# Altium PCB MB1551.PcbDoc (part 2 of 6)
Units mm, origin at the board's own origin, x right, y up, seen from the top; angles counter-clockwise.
Board outline 100 x 70 mm, 6 copper layers (Top Layer, Signal Layer 1, Signal Layer 2, Signal Layer 3, Signal Layer 4, Bottom Layer), stack 1.49 mm thick; 325 components, 276 nets, 1540 pads, 1100 vias.

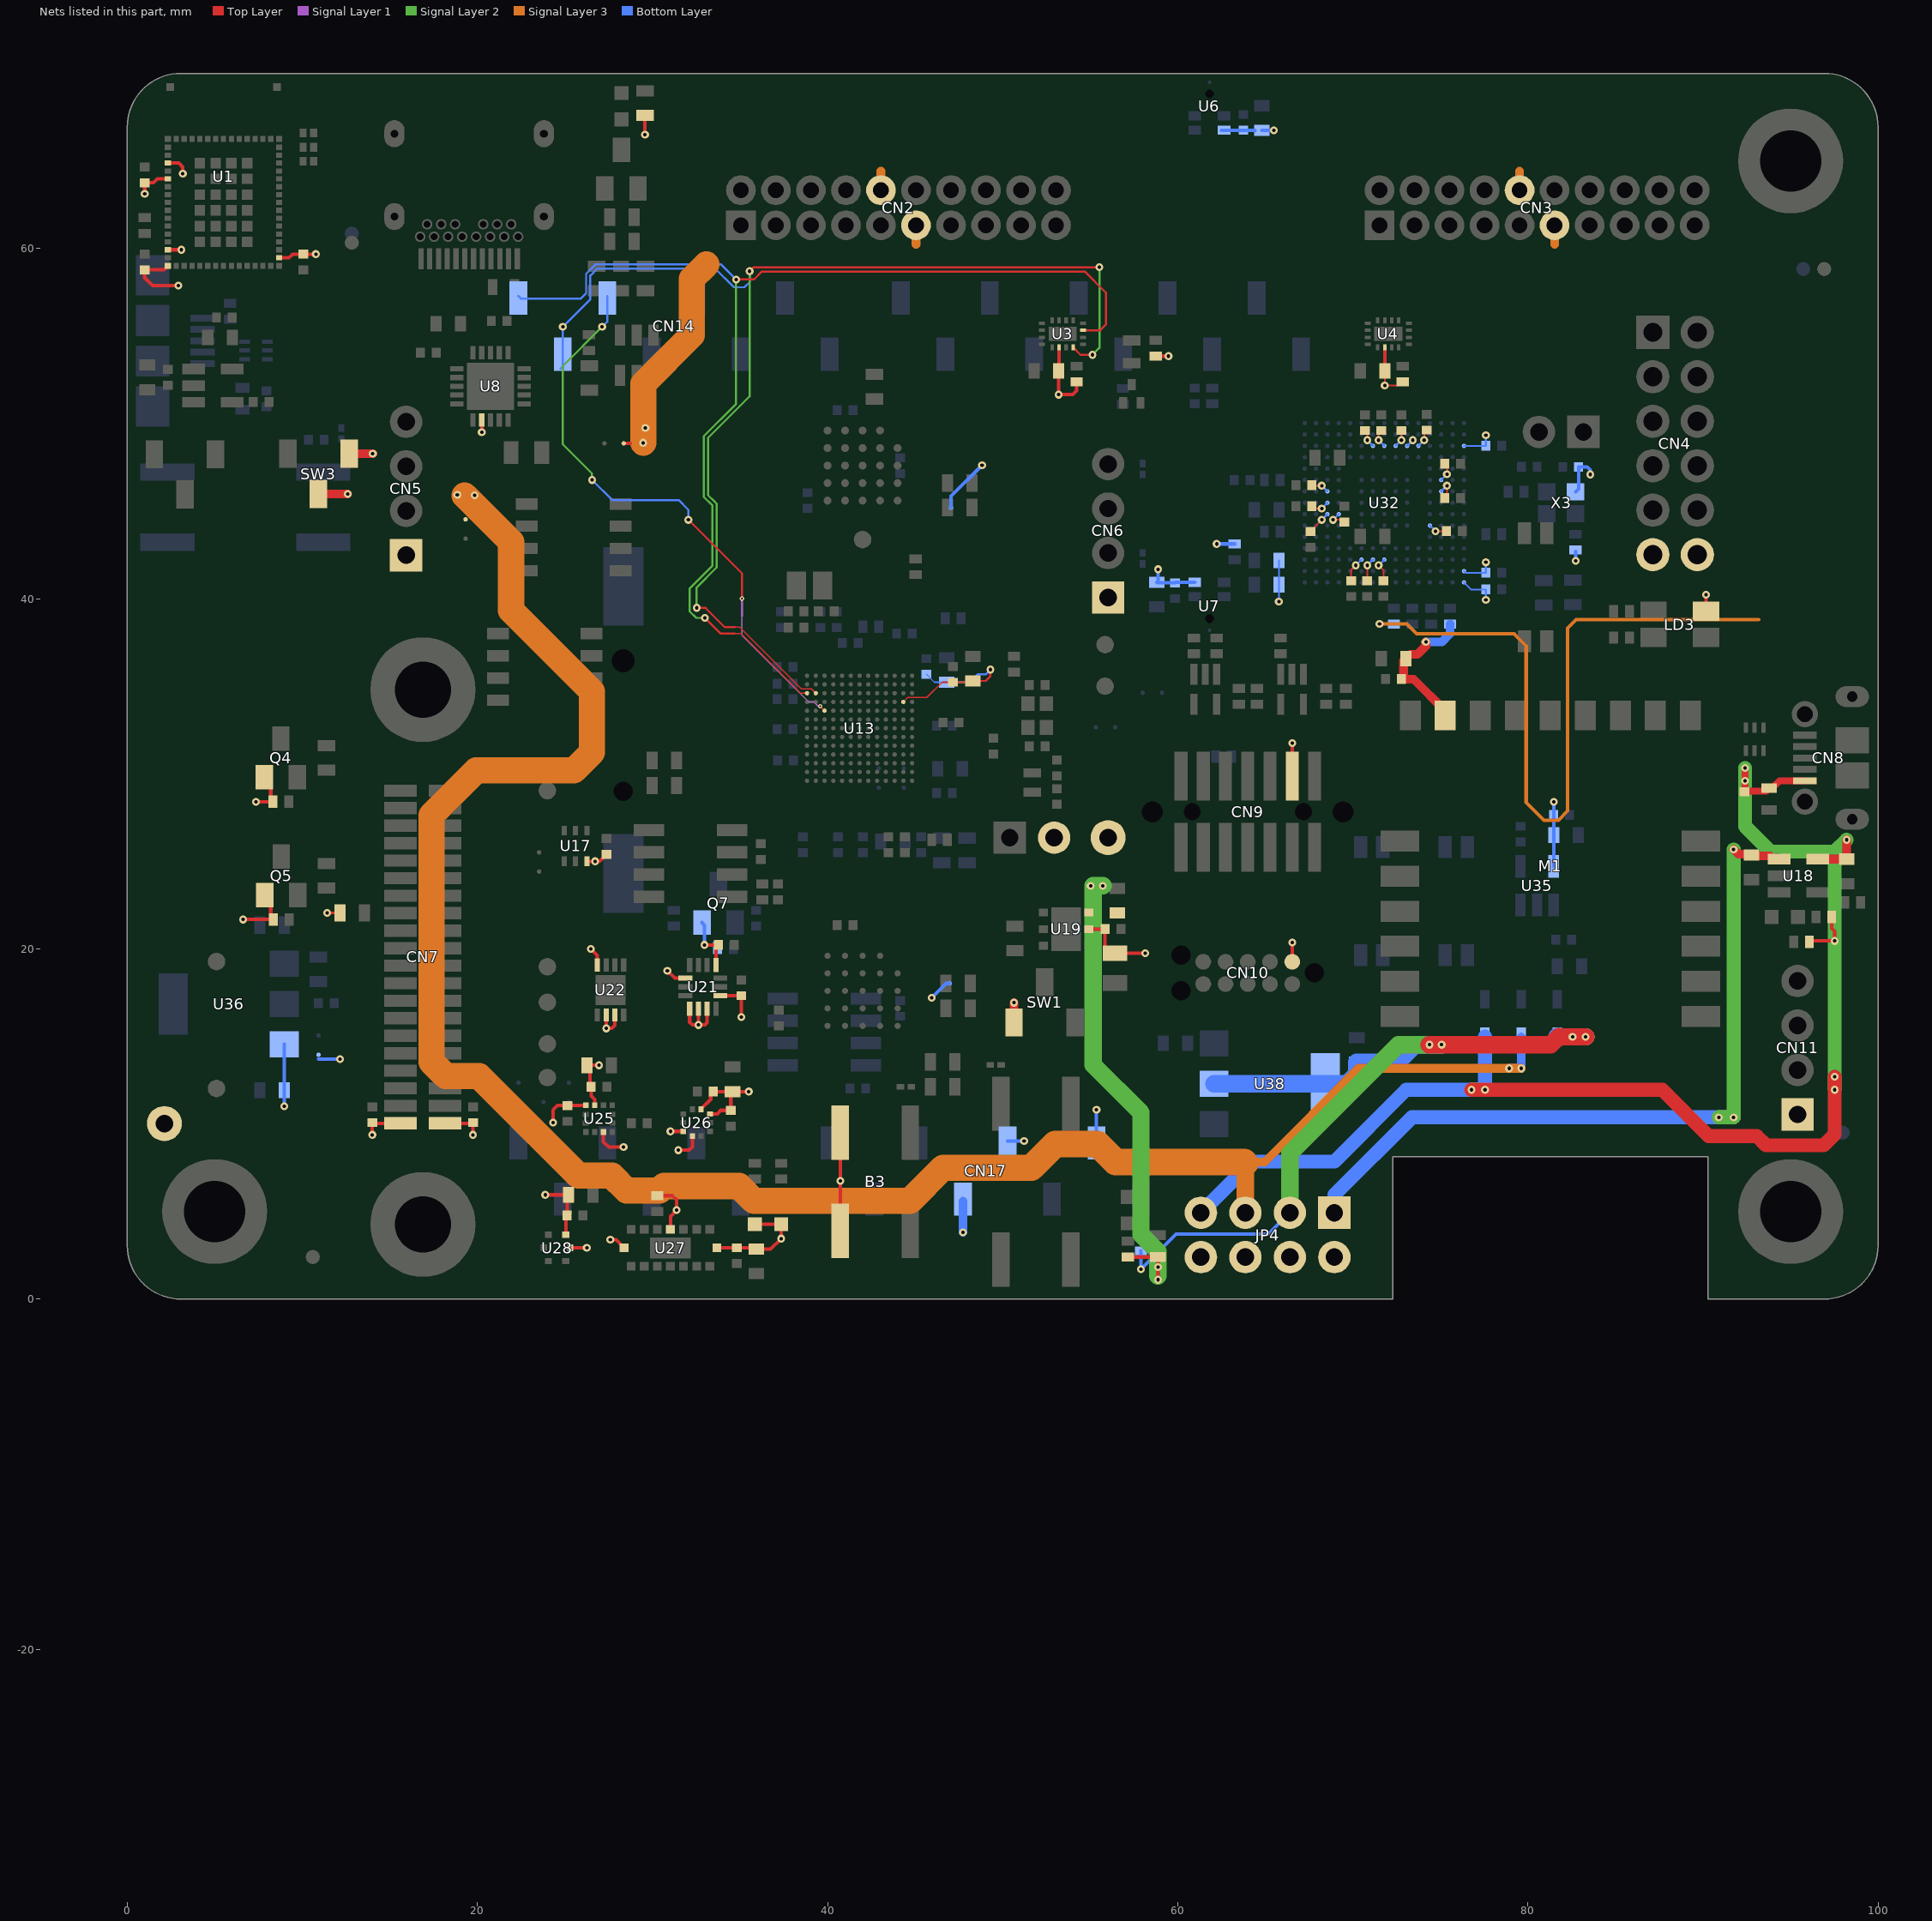
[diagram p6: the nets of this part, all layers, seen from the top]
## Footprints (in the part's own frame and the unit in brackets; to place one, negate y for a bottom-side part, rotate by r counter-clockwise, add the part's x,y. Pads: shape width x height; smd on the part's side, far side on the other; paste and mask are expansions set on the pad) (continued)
ICC_UFQFN16-EPAD_2P6X1P8_P040 [mm]
  rect 0.2x0.35 smd mask+0.05: 1(-0.6,-0.775) 2(-0.2,-0.775) 3(0.2,-0.775) 4(0.6,-0.775) 9(0.6,0.775) 10(0.2,0.775) 11(-0.2,0.775) 12(-0.6,0.775)
  rect 0.35x0.2 smd mask+0.05: 5(1.175,-0.6) 6(1.175,-0.2) 7(1.175,0.2) 8(1.175,0.6) 13(-1.175,0.6) 14(-1.175,0.2) 15(-1.175,-0.2) 16(-1.175,-0.6)
  rect 1.6x0.8 smd mask+0.05: 17(0,0)
  silkscreen extent -1.33,-0.92 1.33,0.92, body extent -1.33,-0.92 1.33,0.92, height 0.56
ICC_VISHAY_VEML6030_2X2_P065 [mm] "MCD-02336"
  rect 0.55x0.3 smd mask+0.05: 1(0.875,-0.65) 2(0.875,0) 3(0.875,0.65) 4(-0.875,0.65) 5(-0.875,0) 6(-0.875,-0.65)
  silkscreen extent -1.05,-1.17 1.22,1.05, body extent -1,-1 1,1, height 0.87
L0805_H0P9 [mm]
  rect 1.1x1.6 smd mask+0.05: 1(-0.75,0) 2(0.75,0)
  silkscreen extent -0.08,-0.7 0.08,0.7, body extent -1.07,-0.7 1.07,0.7, height 1.2
LED_0603_GREEN [mm]
  rect 0.8x0.8 smd mask+0.05: 1(-0.75,0) 2(0.75,0)
  silkscreen extent -0.25,-0.4 1.25,0.4, body extent -0.8,-0.4 0.8,0.4, height 0.6
LED_0603_OSRAM_LG-Q396-PS-35_GREEN_1A2K_H0P4 [mm]
  rect 0.8x0.8 smd mask+0.05: 1(-0.75,0) 2(0.75,0)
  silkscreen extent -0.85,-0.53 1.28,0.53, body extent -0.85,-0.45 0.85,0.45, height 0.6
LED_0603_RED [mm]
  rect 0.8x0.8 smd mask+0.05: 1(-0.75,0) 2(0.75,0)
  silkscreen extent -0.25,-0.4 1.25,0.4, body extent -0.8,-0.4 0.8,0.4, height 0.6
LED_0603_SMD-B_BLUE_H0P4 [mm]
  rect 0.6x1 smd mask+0.05: 1(-0.65,0) 2(0.65,0)
  silkscreen extent -0.23,-0.45 1.07,0.45, body extent -0.85,-0.45 0.85,0.45, height 0.5
LED_0603_VISHAY_VLMS1300-GS08_RED_1A2K_H0P8 [mm]
  rect 0.8x0.8 smd mask+0.05: 1(-0.75,0) 2(0.75,0)
  silkscreen extent -0.85,-0.53 1.28,0.53, body extent -0.85,-0.45 0.85,0.45, height 0.8
LED_BI-GR_HSMF-A201-A00J1 [mm] "MCD-00051"
  rect 1.1x1.5 smd mask+0.05: 1(-0.75,-1.5) 2(-0.75,1.5) 3(0.75,1.5) 4(0.75,-1.5)
  silkscreen extent -1.65,-1.85 1.5,1.7, body extent -1.5,-1.85 1.5,1.85, height 2.1
LOGO_ETIQUETTE [mm]
  silkscreen extent 0,0 27,10
MIC_STM_MP23DB01MMTR [mm]
  rect 0.725x0.522 smd mask+0.05: 1(-0.838,1.364) 2(-0.838,0.542) 4(0.838,0.542) 5(0.838,1.364)
  round 0.2 smd mask+0.05: 3(0,-1.373)
  round 0 hole 0.5 unplated mask+0.05: 6(0,-0.71)
  Top Layer circle w0.3: c0,-0.71 r0.663
  silkscreen extent -1.33,-1.75 1.33,1.75, body extent -1.33,-1.76 1.33,1.75, height 1.09
MIRE_PLACE_SMD_0P8MM [mm]
  round 0.8 smd paste-10 mask+0.2: 1(0,0)
  Top Layer keep-out circle w0.01: c0,0 r0.804
MOD_DORY_STM_86P_7P3X11_H1P342 [mm] "MCD-01965"
  rect 0.35x0.35 smd mask+0.038: 1(-3.175,2.075) 17(-3.175,-5.175) 31(3.175,-5.175) 47(3.175,2.075)
  rect 0.35x0.3 smd mask+0.038: 2(-3.175,1.6) 3(-3.175,1.15) 4(-3.175,0.7) 5(-3.175,0.25) 6(-3.175,-0.2) 7(-3.175,-0.65) 8(-3.175,-1.1) 9(-3.175,-1.55) 10(-3.175,-2) 11(-3.175,-2.45) 12(-3.175,-2.9) 13(-3.175,-3.35) 14(-3.175,-3.8) 15(-3.175,-4.25) 16(-3.175,-4.7) 32(3.175,-4.7) 33(3.175,-4.25) 34(3.175,-3.8) 35(3.175,-3.35) 36(3.175,-2.9) 37(3.175,-2.45) 38(3.175,-2) 39(3.175,-1.55) 40(3.175,-1.1) 41(3.175,-0.65) 42(3.175,-0.2) 43(3.175,0.25) 44(3.175,0.7) 45(3.175,1.15) 46(3.175,1.6)
  rect 0.3x0.35 smd mask+0.038: 18(-2.7,-5.175) 19(-2.25,-5.175) 20(-1.8,-5.175) 21(-1.35,-5.175) 22(-0.9,-5.175) 23(-0.45,-5.175) 24(0,-5.175) 25(0.45,-5.175) 26(0.9,-5.175) 27(1.35,-5.175) 28(1.8,-5.175) 29(2.25,-5.175) 30(2.7,-5.175) 48(2.7,2.075) 49(2.25,2.075) 50(1.8,2.075) 51(1.35,2.075) 52(0.9,2.075) 53(0.45,2.075) 54(0,2.075) 55(-0.45,2.075) 56(-0.9,2.075) 57(-1.35,2.075) 58(-1.8,2.075) 59(-2.25,2.075) 60(-2.7,2.075)
  rect 0.6x0.6 smd mask+0.038: 61(-1.35,0.7) 62(-1.35,-0.2) 63(-1.35,-1.1) 64(-1.35,-2) 65(-1.35,-2.9) 66(-1.35,-3.8) 67(-0.45,-3.8) 68(0.45,-3.8) 69(1.35,-3.8) 70(1.35,-2.9) 71(1.35,-2) 72(1.35,-1.1) 73(1.35,-0.2) 74(1.35,0.7) 75(0.45,0.7) 76(-0.45,0.7) 77(-0.45,-0.2) 78(-0.45,-1.1) 79(-0.45,-2) 80(-0.45,-2.9) 81(0.45,-2.9) 82(0.45,-2) 83(0.45,-1.1) 84(0.45,-0.2)
  rect 0.43x0.43 smd mask+0.05: 85(-3.05,5.035) 86(3.05,5.035)
  silkscreen extent -3.85,-5.69 3.7,5.72, body extent -3.7,-5.62 3.7,5.55, height 1.41
MOD_WIFI_MXCHIP_EMW3080-BP [mm] "MCD-01500"
  rect 2.2x1.2 smd mask+0.05: 3(-8.6,17) 4(-8.6,15) 5(-8.6,13) 6(-8.6,11) 7(-8.6,9) 8(-8.6,7) 18(8.6,7) 19(8.6,9) 20(8.6,11) 21(8.6,13) 22(8.6,15) 23(8.6,17)
  rect 1.2x1.7 smd mask+0.05: 9(-8,-0.175) 10(-6,-0.175) 11(-4,-0.175) 12(-2,-0.175) 13(0,-0.175) 14(2,-0.175) 15(4,-0.175) 16(6,-0.175) 17(8,-0.175)
  Top Layer pour cut-out: -8.75,-0.85 -8.75,2.15 -7.25,2.15 -7.25,-0.85
  Top Layer pour cut-out: -6.75,-0.85 -6.75,2.15 -5.25,2.15 -5.25,-0.85
  Top Layer pour cut-out: -4.75,-0.85 -4.75,2.15 -3.25,2.15 -3.25,-0.85
  Top Layer pour cut-out: -2.75,-0.85 -2.75,2.15 -1.25,2.15 -1.25,-0.85
  Top Layer pour cut-out: -0.75,-0.85 -0.75,2.15 0.75,2.15 0.75,-0.85
  Top Layer pour cut-out: 1.25,-0.85 1.25,2.15 2.75,2.15 2.75,-0.85
  Top Layer pour cut-out: 3.25,-0.85 3.25,2.15 4.75,2.15 4.75,-0.85
  Top Layer pour cut-out: 5.25,-0.85 5.25,2.15 6.75,2.15 6.75,-0.85
  Top Layer pour cut-out: 7.25,-0.85 7.25,2.15 8.75,2.15 8.75,-0.85
  Keep-Out Layer region: 9,33 -9,33 -9,25 9,25
  silkscreen extent -9,0 9,33, body extent -9,0 9,33, height 2.45
MOS_SOT23 [mm]
  rect 1x1.4 smd mask+0.05: 1(-0.95,-1.1) 2(0.95,-1.1) 3(0,1.1)
  silkscreen extent -1.63,-0.82 1.63,0.82, body extent -1.56,-1.25 1.56,1.25, height 1.1
MOS_SOT23-5L [mm]
  rect 0.6x1.3 smd mask+0.05: 1(-0.95,-1.1) 2(0,-1.1) 3(0.95,-1.1) 4(0.95,1.1) 5(-0.95,1.1)
  silkscreen extent -1.6,-0.95 1.6,0.97, body extent -1.52,-1.25 1.52,1.25, height 1.45
NPN_SOT23 [mm]
  rect 1x1.4 smd mask+0.05: 1(-0.95,-1.1) 2(0.95,-1.1) 3(0,1.1)
  silkscreen extent -1.63,-0.82 1.63,0.82, body extent -1.56,-1.25 1.56,1.25, height 1.1
NPN_SOT416-FL_EMT3F_1616_SC89 [mm]
  rect 0.46x0.65 smd mask+0.05: 1(-0.5,-0.525) 2(0.5,-0.525) 3(0,0.525)
  silkscreen extent -0.85,-0.48 0.85,0.48, body extent -0.85,-0.85 0.85,0.85, height 0.85
OSC_NDK_NZ2520SB_4P [mm]
  rect 1x1 smd mask+0.05: 1(-0.825,-0.625) 2(0.825,-0.625) 3(0.825,0.625) 4(-0.825,0.625)
  silkscreen extent -1.43,-1.22 1.2,1.05, body extent -1.3,-1.05 1.3,1.05, height 0.91
PowerFLAT_5x6 [mm] "MCD-02152"
  rect 0.65x1.25 smd mask+0.05: 1(1.905,2.675) 2(0.635,2.675) 3(-0.635,2.675) 4(-1.905,2.675) 5(-1.905,-2.675) 6(-0.635,-2.675) 7(0.635,-2.675) 8(1.905,-2.675)
  Top Layer region: 0.2,-3.3 0.95,-3.3 0.95,-2.75 1.575,-2.75 1.575,-3.3 2.3,-3.3 2.3,-2.3 2.7,-2.3 2.7,-1.5 2.3,-1.5 2.3,0.15 2.7,0.15 2.7,0.975 2.3,0.975 2.3,1.15 0.2,1.15
  Top Layer region: -0.2,-3.3 -0.95,-3.3 -0.95,-2.75 -1.575,-2.75 -1.575,-3.3 -2.3,-3.3 -2.3,-2.3 -2.7,-2.3 -2.7,-1.5 -2.3,-1.5 -2.3,0.15 -2.7,0.15 -2.7,0.975 -2.3,0.975 -2.3,1.15 -0.2,1.15
  silkscreen extent -2.5,-3 2.5,3, body extent -2.6,-3.08 2.6,3.07, height 1
PTH_M1261-3005-N_3P5X6_M3_H14 [mm]
  round 6 hole 3.5 mask+0.05: 1(0,0)
  silkscreen extent -3.25,-3.25 3.25,3.25, body extent -2.5,-2.5 2.5,2.5, height 14
R0402 [mm]
  rect 0.51x0.7 smd mask+0.05: 1(-0.45,0) 2(0.45,0)
  silkscreen extent 0,-0.3 0,0.3, body extent -0.52,-0.3 0.52,0.3, height 0.4
R0603 [mm]
  rect 0.64x1 smd mask+0.05: 1(-0.7,0) 2(0.7,0)
  silkscreen extent -1.05,-0.58 1.05,0.58, body extent -0.9,-0.5 0.9,0.5, height 0.56
R0805_H0P5 [mm] "MCD-01537"
  rect 0.85x1.3 smd mask+0.05: 1(-0.875,0) 2(0.875,0)
  silkscreen extent -0.33,-0.67 0.33,0.67, body extent -1.05,-0.68 1.05,0.68, height 0.6
REG_SOT23-5L [mm]
  rect 0.6x1.3 smd mask+0.05: 1(-0.95,-1.1) 2(0,-1.1) 3(0.95,-1.1) 4(0.95,1.1) 5(-0.95,1.1)
  silkscreen extent -1.6,-0.95 1.6,0.97, body extent -1.52,-1.25 1.52,1.25, height 1.1
REG_SOT223-TAB [mm]
  rect 1.5x1.65 smd mask+0.05: 1(-2.3,-3.175) 2(0,-3.175) 3(2.3,-3.175)
  rect 3.5x1.65 smd mask+0.05: 4(0,3.175)
  silkscreen extent -3.35,-2.15 3.35,2.12, body extent -3.35,-3.48 3.35,3.48, height 1.8
SOLDER-BRIDGE_R0603-0R [mil]
  round 10 smd paste-393.7: 1(-19.68,0) 2(23.62,0)
  Top Layer region: -47.24,-19.68 -47.24,19.69 -15.75,19.69 3.94,0 -15.75,-19.68 -47.24,-19.68
  Top Layer region: -5.91,19.69 13.78,0 -5.91,-19.68 47.24,-19.68 47.24,19.69 -5.91,19.69
  silkscreen extent -50,-23 50,23, body extent -36,-20 36,20, height 22
SWI_C&K_KSC321GLFS_BLACK [mm] "BLACK"
  rect 3.1x1 smd mask+0.05: 1(-4.45,2) 2(4.45,2) 3(-4.45,-2) 4(4.45,-2)
  silkscreen extent -3.25,-3.25 3.25,3.25, body extent -5,-3.25 5,3.25, height 3.5
SWI_C&K_KSC721JLFS_BLUE [mm] "MCD-01800"
  rect 3.1x1 smd mask+0.05: 1(-2.8,2) 2(2.8,2) 3(-2.8,-2) 4(2.8,-2)
  silkscreen extent -3.25,-3.25 3.25,3.25, body extent -3.4,-3.25 3.4,3.25, height 4.3
SWI_CJS-1200A1 [mm] "MCD-02279"
  rect 1x1.6 smd mask+0.05: 1(-1.75,-1.15) 2(0,1.15) 3(1.75,-1.15)
  silkscreen extent -2.7,-1.25 2.7,1.25, body extent -2.7,-1.4 2.7,1.4, height 2.6
SWI_MULTICOMP_MCDHN-02F-V_4P [mm] "MCD-02105"
  rect 0.76x1.25 smd mask+0.05: 1(-0.635,-3.075) 2(0.635,-3.075) 3(0.635,3.075) 4(-0.635,3.075)
  silkscreen extent -1.89,-2.25 1.89,2.25, body extent -1.89,-3.35 1.88,3.35, height 1.6
TP_PTH_1MM_2MM [mm] "MCD-01506"
  round 2 hole 1 mask+0.05: 1(0,0)
  silkscreen extent -1.2,-1.2 1.2,1.2
TP_SMD_1MM [mm]
  round 1 smd paste-10 mask+0.05: 1(0,0)
  silkscreen extent -0.7,-0.7 0.7,0.7

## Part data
B1 B2: library part MCD-00175, "Switch HW BLACK High3.5mm 2Newtons", Manufacturer=C&K, Manufacturer_Part_Number=KSC321GLFS
B3: library part MCD-01800, "Switch HW BLUE High4.3mm 2.25 Newtons, BEND type", Manufacturer=C&K, Manufacturer_Part_Number=KSC721JLFS
C1 C2 C3 C17 C39 C40 C43 C56 C66 C67 C90 C91 C92 C93 C95 C97 C98 C99 C100 C101 C103 C107 C109 C110 C111 C119: library part MCD-00006, "Capacitor, MLCC, 100nF, 16V, X7R, 10%, 0402, T=0.5mm", Alternate_Manufacturer=MURATA, Alternate_Manufacturer_Part_Number=GCM155R71C104KA55D, Manufacturer=YAGEO, Manufacturer_Part_Number=CC0402KRX7R7BB104, Package=C0402
C4: library part MCD-00637, "Capacitor, MLCC, 10pF, 50V, NPO, 5%, 0603, T=0,8mm", Manufacturer=YAGEO, Manufacturer_Part_Number=CC0603JRNPO9BN100, Package=C0603
C5 C6 C8 C9 C38 C52 C53 C84 C94 C102 C106 C113 C118: library part MCD-00010, "Capacitor, MLCC, 1uF, 16V, X5R, 10%, 0603, T=0,8mm", Manufacturer=YAGEO, Manufacturer_Part_Number=CC0603KRX5R7BB105, Package=C0603
C10: library part MCD-00198, "Capacitor, MLCC, 1nF, 16V, X7R, +/-10%, 0402, T=0.5mm", Manufacturer=YAGEO, Manufacturer_Part_Number=CC0402KRX7R7BB102, Package=0402
C11: library part MCD-01099, "Capacitor,100nF,50V,X7R,10%,0603", Manufacturer=YAGEO, Manufacturer_Part_Number=CC0603KRX7R9BB104, Package=C0603
C12: library part MCD-00011, "Capacitor,10nF,16V,X7R,10%,0402,YAGEO", Manufacturer=YAGEO, Manufacturer_Part_Number=CC0402KRX7R7BB103
C13 C14 C15 C16 C21 C22 C23 C24 C25 C28 C29 C31 C32 C33 C42 C51 C57 C59 C63 C64 C65 C68 C71 C72 C77 C79 C80 C85 C87 C104 C112 C125 C126 C127: library part MCD-00006, "Capacitor, MLCC, 100nF, 16V, X7R, 10%, 0402, T=0.5mm", Manufacturer=YAGEO, Manufacturer_Part_Number=CC0402KRX7R7BB104, Package=C0402
C18: library part MCD-00012, "Capacitor,2.2uF,10V, X5R,10%,0603,YAGEO", Alternate_Manufacturer=KEMET, Alternate_Manufacturer_Part_Number=C0603C225K8PACTU, Manufacturer=YAGEO, Manufacturer_Part_Number=CC0603KRX5R6BB225
C19 C26: library part MCD-00006, "Capacitor,100nF,16V,X7R,10%,0402,YAGEO", Manufacturer=YAGEO, Manufacturer_Part_Number=CC0402KRX7R7BB104
C20 C30 C37 C83: library part MCD-00012, "Capacitor, MLCC, 2.2uF, 10V, X5R, 10%, 0603, T=0,8mm", Alternate_Manufacturer=KEMET, Alternate_Manufacturer_Part_Number=C0603C225K8PACTU, Manufacturer=YAGEO, Manufacturer_Part_Number=CC0603KRX5R6BB225, Package=C0603
C27: library part MCD-00243, "Capacitor,10uF,6V3,X5R,10%,0603,YAGEO", Manufacturer=YAGEO, Manufacturer_Part_Number=CC0603KRX5R5BB106
C34 C36 C48 C49: library part MCD-01823, "Capacitor,MLCC,2.2uF,6V3,X5R,10%,0402,T=0.5", Manufacturer=MURATA, Manufacturer_Part_Number=GRM155R60J225KE95D, Package=C0402
C35 C47 C75: library part MCD-00205, "Capacitor, MLCC, 100pF, 50V, NPO, 5%, 0402, T=0,5mm", Manufacturer=YAGEO, Manufacturer_Part_Number=CC0402JRNPO9BN101, Package=C0402
C41 C44: library part MCD-02215, "Capacitor, MLCC, 0.5pF, 50V, C0G, +-0.1pF, 0402, T=0.5mm", Alternate_Manufacturer=N/A, Manufacturer=MURATA, Manufacturer_Part_Number=GJM1555C1HR50BB01D, Package=C0402
C45 C46: library part MCD-00556, "Capacitor, MLCC, 3.9pF, 50V, NPO, +/-0.25pF, 0402, T=0.5mm", Manufacturer=YAGEO, Manufacturer_Part_Number=CC0402CRNPO9BN3R9, Package=0402
C50: library part MCD-01716, "Capacitor, MLCC, 10uF, 6V3, X5R, +/-20%, 0402, T=0.5mm", Manufacturer=YAGEO, Manufacturer_Part_Number=CC0402MRX5R5BB106, Package=C0402
C54 C62 C73 C86 C108: library part MCD-00009, "Capacitor, MLCC, 4.7uF, 16V, X5R, 10%, 0603, T=0.8mm", Manufacturer=YAGEO, Manufacturer_Part_Number=CC0603KRX5R7BB475, Package=C0603
C55 C60 C76 C78 C82 C114: library part MCD-00102, "Capacitor, MLCC, 100nF, 16V, X7R, 10%, 0402, T=0,5mm", Alternate_Manufacturer=MURATA, Alternate_Manufacturer_Part_Number=GCM155R71C104KA55D, Manufacturer=YAGEO, Manufacturer_Part_Number=CC0402KRX7R7BB104, Package=C0402
C58: library part MCD-00014, "Capacitor, MLCC, 10uF, 25V, X5R, 10%, 0805, T=0,85mm", Manufacturer=YAGEO, Manufacturer_Part_Number=CC0805KRX5R8BB106, Package=C0805
C61: library part MCD-01124, "Capacitor, MLCC, 10µF, 10V, X5R, 10%, 0603, T=0.8mm", Manufacturer=MURATA, Manufacturer_Part_Number=GRM188R61A106KAAL, Package=C0603
C69: library part MCD-00602, "Capacitor, MLCC, 220nF, 16V, 0402, X7R, 10%, T=0,5mm", Manufacturer=MURATA, Manufacturer_Part_Number=GRM155R71C223KA01J, Package=C0402
C70: library part MCD-01540, "Capacitor,X5R,2.2uF, 15%, 50V, 0603", Manufacturer=MURATA, Manufacturer_Part_Number=GRM188R61H225KE11, Package=0603
C74: library part MCD-00006, "Capacitor,100nF,16V,X7R,10%,0402", Manufacturer=YAGEO, Manufacturer_Part_Number=CC0402KRX7R7BB104, Package=C0402
C81: library part MCD-00016, "Capacitor, MLCC, 20pF, 50V, NPO, 5%, 0402, T=0,5mm", Manufacturer=YAGEO, Manufacturer_Part_Number=CC0402JRNPO9BN200, Package=C0402
C88 C89 C96 C115: library part MCD-01355, "Capacitor, MLCC, 10uF, 4V, X5R, 20%, 0402, T=0,5mm", Manufacturer=MURATA, Manufacturer_Part_Number=GRM155R60G106ME44, Package=C0402
C105: library part MCD-00011, "Capacitor, MLCC, 10nF, 16V, X7R, 10%, 0402, T=0.5mm", Manufacturer=YAGEO, Manufacturer_Part_Number=CC0402KRX7R7BB103, Package=C0402
C116 C117: library part MCD-00099, "Capacitor, MLCC, 10uF, 10V, X5R, 10%, 0603, T=0,8mm", Manufacturer=MURATA, Manufacturer_Part_Number=GRM188R61A106KE69D, Package=C0603
C120 C121: library part MCD-01579, "Capacitor, MLCC, 330pF, 50V, NPO, +/-5%, 0402, T=0,5mm", Manufacturer=YAGEO, Manufacturer_Part_Number=CC0402JRNPO9BN331, Package=C0402
C122 C123 C124: library part MCD-02284, "Capacitor, MLCC, 3.3pF, 50V, NPO, +-0.05pF, 0201, T=0.3mm\".", Alternate_Manufacturer=N/A, Manufacturer=MURATA, Manufacturer_Part_Number=GRM0335C2A3R3WA01J, Package=C0201
CN1: library part MCD-01108, "USB tyce C certified receptacle for 1.6mm pcb height", Manufacturer="CHANT SINCERE (COXOC)", Manufacturer_Part_Number=317JD24BZTF3K3C3
CN2 CN3: library part MCD-00309, "Socket 10x2, 2.00mm, RA, TH, Height 6.35mm/2.29mm", Manufacturer=SAMTEC, Manufacturer_Part_Number=SQT-110-01-F-D-RA
CN4: library part MCD-00308, "Socket, 6x2, 2.54mm, TH, RA, Height 8.51mm/7.62mm", Manufacturer=SAMTEC, Manufacturer_Part_Number=SSW-106-02-F-D-RA
CN5 CN6 CN11: library part MCD-00029, "Header, 4x1, 2,54mm, VR, TH, Height 5.84mm/2.54mm", Manufacturer=SAMTEC, Manufacturer_Part_Number=TSW-104-07-x-S
CN7: library part MCD-00138, "Socket, 20x2, 1.0mm, VR, SMT, Height 2.26mm. Symbol & Footprint dedicated to MB1183 & MB1379 camera modules (not in line with Samtec datasheet)", Manufacturer=SAMTEC, Manufacturer_Part_Number=CLM-120-02-L-D
CN8: library part MCD-00028, "USB-MICRO-B, 0.65mm, RA, SMT, Bottom Mount,", Manufacturer=MOLEX, Manufacturer_Part_Number=1050170001
CN9: library part MCD-01226, "Header 5x2, 1.27mm, Dual row, Straight, Surface mount, vertical male connector. 3.05mm lead. Mates with FFSD connector. Footprint compatible with FTSH-107-01-L-DV,-K,-A,-P,-ES (STDC14 MEDIUM)", Manufacturer=SAMTEC, Manufacturer_Part_Number=FTSH-105-01-L-DV-K
CN10: library part MCD-00031, "Tag_Connector Header, 10x2, No legs", Manufacturer="TAG-CONNECT LLC", Manufacturer_Part_Number=TC2050-IDC-NL-FP
CN12: library part MCD-01075, "USB, micro AB receptacle,10104111-0001LF", Manufacturer=FCI, Manufacturer_Part_Number=10104111-0001LF
CN13: library part MCD-02342, "Socket, 10x1, 2.54mm, VR, SMT, Height 7.37mm", Manufacturer=SAMTEC, Manufacturer_Part_Number=SSM-110-L-SV, Package="Surface Mount"
CN14 CN17: library part MCD-02345, "Socket, 8x1, 2.54mm, VR, SMT, Height 7.37mm", Manufacturer=SAMTEC, Manufacturer_Part_Number=SSM-108-L-SV, Package="Surface Mount"
CN15: library part MCD-00558, "Battery Coin Cell holder, CR1220_12mm, Height 4.25mm", Manufacturer=HARWIN, Manufacturer_Part_Number=S8411-45R
CN16: library part MCD-02346, "Socket, 6x1, 2.54mm, VR, SMT, Height 7.37mm", Manufacturer=SAMTEC, Manufacturer_Part_Number=SSM-106-L-SV, Package="Surface Mount"
D2 D3 D4: library part MCD-00034, Manufacturer=STMICROELECTRONICS
H1 H3 H4: library part MCD-00035, "POSITION HOLE C6D3R5"
JP1 JP3: library part MCD-00045, "Header, 2x1, 2,54mm, VR, TH, Height 5.84mm/2.54mm", Manufacturer=SAMTEC, Manufacturer_Part_Number=TSW-102-07-x-S
JP4: library part MCD-00633, "Header, 4x2, 2,54mm, VR, TH, Height 5.84mm/2.54mm", Manufacturer=SAMTEC, Manufacturer_Part_Number=TSW-104-07-x-D
L1: library part MCD-01060, "Inductor, 2.2uH, 20%, Isat 0.7A, DCR 0.156Ohm, 0805", Manufacturer=MURATA, Manufacturer_Part_Number=LQM21PN2R2MGH, Package=L0805
LD1: library part MCD-00050, "LED, Green, 0603", Manufacturer=EVERLIGHT, Manufacturer_Part_Number=19-213SYGC/S530-E2/TR8, Package="LED 0603"
LD2: library part MCD-01131, "LED Blue, 0603 SMD, Forward Voltage Min=2,8V, Max=3,1V", Manufacturer=EVERLIGHT, Manufacturer_Part_Number=19-217-BHC-ZL1M2RY-3T, Package=0603
LD3: library part MCD-00051, "LED Bicolor", Alternate_Manufacturer=EVERLUCK, Alternate_Manufacturer_Part_Number=LE-RGW35280, Manufacturer="AVAGO TECHNOLOGIES", Manufacturer_Part_Number=HSMF-A201-A00J1
LD4: library part MCD-00049, "LED, Red, 0603", Manufacturer=EVERLIGHT, Manufacturer_Part_Number=19-213-R6C-AP1Q2B/3T, Package="LED 0603"
LD5 LD7: library part MCD-00588, "LED Green, 0603 SMD, Forward Voltage Typ=2V, Max=2.5V", Alternate_Manufacturer="VISHAY SEMICONDUCTOR OPTO DIVISION", Alternate_Manufacturer_Part_Number=VLMTG1300-GS08, Manufacturer="OSRAM OPTO SEMICONDUCTORS", Manufacturer_Part_Number="LG Q396-PS-35", Package="LED 0603"
LD6: library part MCD-00587, "LED Red, 0603 SMD, 2V Forward Voltage", Alternate_Manufacturer="OSRAM OPTO SEMICONDUCTORS", Alternate_Manufacturer_Part_Number="LS Q976-NR-1", Manufacturer=VISHAY, Manufacturer_Part_Number=VLMS1300-GS08, Package="LED 0603"
M1: library part MCD-01500, "Wi-Fi module 33x18mm, UART-SPI interface", Manufacturer=MXCHIP
Q1: library part MCD-00073, "NPN Bipolar Transistor", Manufacturer=NXP, Manufacturer_Part_Number=BSR14
Q2 Q6: library part MCD-02152, "Dual N-channel 30 V, 0.016 Ω typ., 40 A, STripFET™ H5 Power MOSFET", Alternate_Manufacturer=N/A, Manufacturer=STMICROELECTRONICS, Package="PowerFLAT 5x6"
Q3: library part MCD-00280, "Buffer transistor", Manufacturer=ROHM
Q4 Q5: library part MCD-01164, "N-channel Digital FET", Manufacturer=FAIRCHILD, Manufacturer_Part_Number=FDV303N, Package=SOT-23
Q7: library part MCD-01219, "MOSFET, P-Channel , Vds: -20V, Id: -2.8A, Vgs(th): -0.9V, Vgs(max): +/-12V, Rdson:135mohm@Vgs=-1.8V, Qg=7.7nC", Manufacturer=NXP, Package=SOT-23-3
R1: library part MCD-00225, "Resistor,510R,0603,1%,1/10W", Manufacturer=YAGEO, Manufacturer_Part_Number=RC0603FR-07510RL, Package=R0603
R2: library part MCD-00430, "Resistor,22K,0603,1%,1/10W", Manufacturer=YAGEO, Manufacturer_Part_Number=RC0603FR-0722KL, Package=R0603
R3 R10 R11 R31 R43 R52 R53 R66: library part MCD-00053, "Resistor,10K,0402,1%,1/16W", Manufacturer=YAGEO, Manufacturer_Part_Number=RC0402FR-0710KL, Package=R0402
R4: library part MCD-00222, "Resistor,47K,0603,1%,1/10W", Manufacturer=YAGEO, Manufacturer_Part_Number=RC0603FR-0747KL, Package=R0603
R5: library part MCD-00458, "Resistor,330K,0603,1%,1/10W", Manufacturer=YAGEO, Manufacturer_Part_Number=RC0603FR-07330KL, Package=R0603
R6: library part MCD-01171, "Resistor,49K9,0603,1%", Manufacturer=YAGEO, Manufacturer_Part_Number=RC0603FR-0749K9L, Package=R0603
R7 R12 R15 R32 R35 R37 R64 R65: library part MCD-00220, "Resistor,10K,0603,1%,1/10W", Manufacturer=YAGEO, Manufacturer_Part_Number=RC0603FR-0710KL, Package=R0603
R8: library part MCD-00433, "Resistor,2K4,0402,1%,1/16W", Manufacturer=YAGEO, Manufacturer_Part_Number=RC0402FR-072K4L, Package=R0402
R9: library part MCD-00064, "Resistor,510R,0402,1%,1/16W", Manufacturer=YAGEO, Manufacturer_Part_Number=RC0402FR-07510RL, Package=R0402
R13: library part MCD-02151, "Current Detection Resistor, 0R047, 0805, 1%, 1/4W", Alternate_Manufacturer=N/A, Manufacturer=YAGEO, Manufacturer_Part_Number=RL0805FR-7W0R047L, Package=R0805
R14 R26 R30 R38: library part MCD-00056, "Resistor,0R,0603,5%,1/10W", Manufacturer=YAGEO, Manufacturer_Part_Number=RC0603JR-070RL, Package=R0603
R16 R17: library part MCD-00062, "Resistor,330R,0402,1%,1/16W", Manufacturer=YAGEO, Manufacturer_Part_Number=RC0402FR-07330RL, Package=R0402
R18 R19 R20 R22 R23 R24: library part MCD-00481, "Resistor,47R,0402,1%,1/16W", Manufacturer=YAGEO, Manufacturer_Part_Number=RC0402FR-0747RL, Package=R0402
R21 R47 R48: library part MCD-00052, "Resistor,0R,0402,5%,1/16W", Manufacturer=YAGEO, Manufacturer_Part_Number=RC0402JR-070RL, Package=R0402
R25 R49 R50 R58: library part MCD-00119, "Resistor,100R,0402,1%,1/16W", Manufacturer=YAGEO, Manufacturer_Part_Number=RC0402FR-07100RL, Package=R0402
R27 R28 R59 R60: library part MCD-00352, "Resistor,3K3,0603,1%,1/10W", Manufacturer=YAGEO, Manufacturer_Part_Number=RC0603FR-073K3L, Package=R0603
R29 R34 R54 R55 R56: library part MCD-00065, "Resistor,4K7,0402,1%,1/16W", Alternate_Manufacturer=YAGEO, Alternate_Manufacturer_Part_Number=RT0402FRE074K7L, Manufacturer_Part_Number=RC0402FR-074K7L, Package=R0402
R33 R63: library part MCD-00061, "Resistor,1K,0402,1%,1/16W", Manufacturer=YAGEO, Manufacturer_Part_Number=RC0402FR-071KL, Package=R0402
R36 R46: library part MCD-00059, "Resistor,100K,0402,1%,1/16W", Alternate_Manufacturer=YAGEO, Alternate_Manufacturer_Part_Number=RT0402FRE07100KL, Manufacturer_Part_Number=RC0402FR-07100KL, Package=R0402
R39: library part MCD-00418, "Resistor,200R,0603,1%,1/10W", Manufacturer=YAGEO, Manufacturer_Part_Number=RC0603FR-07200RL, Package=R0603
R40: library part MCD-00422, "Resistor,20K,0603,1%,1/10W", Manufacturer=YAGEO, Manufacturer_Part_Number=RC0603FR-0720KL, Package=R0603
R41: library part MCD-00461, "Resistor,360R,0402,1%,1/16W", Manufacturer=YAGEO, Manufacturer_Part_Number=RC0402FR-07360RL, Package=R0402
R42: library part MCD-00441, "Resistor,270R,0402,1%,1/16W", Manufacturer=YAGEO, Manufacturer_Part_Number=RC0402FR-07270RL, Package=R0402
R44: library part MCD-00499, "Resistor,620R,0402,1%,1/16W", Manufacturer=YAGEO, Manufacturer_Part_Number=RC0402FR-07620RL, Package=R0402
R45 R71: library part MCD-00053, "Resistor, 10K, 0402, +/-1%, 1/16W", Manufacturer=YAGEO, Manufacturer_Part_Number=RC0402FR-0710KL, Package=0402
R51: library part MCD-00185, "Resistor,3K,0402,1%,1/16W", Manufacturer=YAGEO, Manufacturer_Part_Number=RC0402FR-073KL, Package=R0402
R57: library part MCD-00055, "Resistor,2K7,0402,1%,1/16W", Manufacturer=YAGEO, Manufacturer_Part_Number=RC0402FR-072K7L, Package=R0402
R61: library part MCD-00394, "Resistor,150,0603,1%,1/10W", Manufacturer=YAGEO, Manufacturer_Part_Number=RC0603FR-07150RL, Package=R0603
R62: library part MCD-00338, "Resistor,120R,0603,1%,1/10W", Manufacturer=YAGEO, Manufacturer_Part_Number=RC0603FR-07120RL, Package=R0603
R67 R68 R69 R70: library part MCD-00455, "Resistor, 33R, 0402, +/-1%, 1/16W", Manufacturer=YAGEO, Manufacturer_Part_Number=RC0402FR-0733RL, Package=0402
R72: library part MCD-00059, "Resistor, 100K, 0402, +/-1%, 1/16W", Manufacturer=YAGEO, Manufacturer_Part_Number=RC0402FR-07100KL, Package=0402
SB2 SB3 SB4 SB5 SB6 SB7 SB8 SB9 SB10 SB11 SB12 SB13 SB15 SB16 SB17: library part MCD-00071, "Solder Bridge ON"
SW1 SW3 SW6: library part MCD-02279, "SLIDE SWITCHE (SMD) serie CJS", Alternate_Manufacturer=N/A, Manufacturer="NIDEC Copal", Package="SMD Package"
SW2 SW4 SW5: library part MCD-02105, "DIP Switch Slide Type x2 poles 25mA 24VDC 100mR SMD", Alternate_Manufacturer=N/A, Manufacturer=MULTICOMP, Manufacturer_Part_Number=MCDHN-02F-V
TP1 TP2 TP3 TP4 TP6 TP7 TP8 TP9 TP10 TP11: library part MCD-00074, "Test Point 1mm", Manufacturer=n/a
TP5 TP12: library part MCD-01506, "Test Point trought hole 1mm/2mm", Manufacturer=n/a
U1: library part MCD-01965, "STM32 BLE module based on STM32WB55", Alternate_Manufacturer=N/A, Manufacturer=STMICROELECTRONICS, Manufacturer_HQ_COO=EU, Manufacturer_Part_Number=STM32WB5MMGH6, Package=WLCSP100
U2: library part MCD-01207, "High power Transient voltage suppressor:25V/35A EOS and ESD transients protection.", Manufacturer=STMICROELECTRONICS, Manufacturer_Part_Number=ESDA25P35-1U1M, Package=QFN1610
U3 U4: library part MCD-00317, "Low voltage high bandwidth quad SPDT switch", Manufacturer=STMICROELECTRONICS
U5: library part MCD-00163, "Very low capacitance ESD protection", Manufacturer=STMICROELECTRONICS
U6 U7: library part MCD-02122, "MEMS sensors , omnidirectionnal digital microphone", Alternate_Manufacturer=N/A, Manufacturer=STMICROELECTRONICS, Manufacturer_Part_Number=MP23DB01HPTR, Package="RHLGA 5"
U8: library part MCD-02130, "USB Type-C Port Protection for USB DRP Power Delivery, PPS compliant", Alternate_Manufacturer=N/A, Manufacturer=STMICROELECTRONICS, Package=QFN-20L
U9: library part MCD-00246, "Memory,Octo-SPI-NOR,512Mb,2048x16,133MHz,3V,DTR,BGA24, CMOS MXSMIO", Manufacturer=MACRONIX, Manufacturer_Part_Number=MX25LM51245GXDI00, Package=BGA24
U10: library part MCD-00086, "Ultra low drop-low noise BiCMOS voltage, regulators low ESR capacitors compatible", Manufacturer=STM
U11 U12: library part MCD-00136, "Dual Transil array for ESD protection", Manufacturer=STMICROELECTRONICS
U13: library part MCD-02055, "STM32U585AII6Q MCU,Low Power BGA169 7x7, pitch0.5, with encryption, Q for Int SMPS.", Manufacturer=STMICROELECTRONICS, Package=BGA169
U14 U30: library part MCD-00649, "Common mode filter with ESD protection for USB 2.0 interface", Manufacturer=STMICROELECTRONICS
U15 U29: library part MCD-01026, "High power transient voltage suppressor", Manufacturer=STMICROELECTRONICS, Manufacturer_Part_Number=ESDA7P120-1U1M, Package=QFN1610
U16: library part MCD-02399, "Authentication, state-of-the-art security for peripherals and IoT devices", Manufacturer=STMICROELECTRONICS, Manufacturer_Part_Number=STSAFA110S8SPL03, Package=SO8N
U17: library part MCD-02336, "High Accuracy Ambient Light Sensor with I2C Interface", Manufacturer=VISHAY, Package="surface mount"
U18: library part MCD-00159, "500mA, Enhanced single channel power switches with active high enable pin", Alternate_Manufacturer="TEXAS INSTRUMENTS", Alternate_Manufacturer_Part_Number=TPS2051C, Manufacturer=STMICROELECTRONICS
U19: library part MCD-01127, "IC REG LDO 3.3V 1.3A 6DFN", Manufacturer=STMICROELECTRONICS, Package=DFN6
U20: library part MCD-01391, "Memory, DDR Octal SPI PSRAM, 64Mb, 8Mx8, up to 133MHz@3V0, 104MHz@3V3, PASR", Manufacturer=APMEMORY, Manufacturer_Part_Number=APS6408L-3OB-BA, Package="MiniBGA 24 6x8x1.2"
U21: library part MCD-02160, "iNEMO inertial module: 3D accelerometer and 3D gyroscope, with digital output for industrial applications", Alternate_Manufacturer=N/A, Manufacturer=STMICROELECTRONICS, Package=LGA-14L
U22: library part MCD-01871, "I2C Memory 3V3, 256Kbits, 2x3,0.55mm, UFDFPN8", Manufacturer=STMICROELECTRONICS, Manufacturer_Part_Number=M24256-DFMC6TG
U23 U24 U33 U34 U39: library part MCD-00170, "ESD protection 6V1", Manufacturer=STMICROELECTRONICS, Manufacturer_Part_Number=ESDALC6V1-1U2
U25: library part MCD-01713, "High-accuracy, ultra-low-power, 3-axis, digital output magnetometer", Manufacturer=STMICROELECTRONICS, Package=LGA-12
U26: library part MCD-01702, "High-performance MEMS nano pressure sensor:260-1260 hPa absolute digital output barometer", Manufacturer=STMICROELECTRONICS, Package=HLGA-10L
U27: library part MCD-02257, "Time-of-Flight mini depth camera", Alternate_Manufacturer=N/A, Manufacturer=STMICROELECTRONICS, Manufacturer_HQ_COO=EU, Manufacturer_Part_Number=VL53L5CXV0GC/1, Package="Optical LGA16 without liner"
U28: library part MCD-01447, "Capacitive digital sensor for relative humidity and temperature", Manufacturer=STMICROELECTRONICS, Package=HLGA-6L
U31: library part MCD-00251, "High power transient voltage suppressor, 7V breakdown", Manufacturer=STMICROELECTRONICS, Manufacturer_Part_Number=ESDA7P60-1U1M
U32: library part MCD-00596, "STM32F723IEK  (STM32F7) BGA176", Manufacturer=STMICROELECTRONICS, Manufacturer_Part_Number=STM32F723IEK6
U35: library part MCD-00086, "Ultra low drop-low noise BiCMOS voltage, regulators low ESR capacitors compatible", Manufacturer=STMICROELECTRONICS
U36: library part MCD-00721, "LDO Voltage Regulator, Adjustable, 15V in, 1.1V drop, 1.25V to 15V/0.8A out, SOT-223-3", Manufacturer=STMICROELECTRONICS, Manufacturer_Part_Number=LD1117STR, Package=SOT223
U37: library part MCD-01790, "Quad-SPI PSRAM APS1604M-3SQR-SN with SOP-8L package", Manufacturer=APMEMORY, Package=SO8
U38: library part MCD-00088, "IC REG LDO 5V 0.8A SOT223", Manufacturer=STMICROELECTRONICS
X1: library part MCD-01476, "Crystal 16 MHz, 8pF, -+20 PPM, R=200Ω, SMD", Manufacturer=NDK, Manufacturer_Part_Number="NX2016SA 16 MHz EXS00A-CS07826", Package=NX2016SA
X2: library part MCD-02291, "Crystal 32.768kHz, 9pF, -+20ppm, 70Kohm max, SMD", Alternate_Manufacturer=N/A, Manufacturer=NDK, Manufacturer_Part_Number="NX1610SE 32.768KHz EXS00A-MU01499", Package=NX1610SE
X3: library part MCD-00597, "Oscillator 25Mhz, +-50ppm, Vcc:3.3V typ, square wave: [0.1Vcc;0.9Vcc], Enable pin, SMD", Alternate_Manufacturer=NDK, Alternate_Manufacturer_Part_Number="NZ2520SB 25MHz END4869B", Manufacturer_Part_Number="NZ2520SH 25MHz END4869C"

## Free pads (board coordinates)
  round 0.508 on Mech16: 1(23.967,-32.118) 1(72.814,-32.118)

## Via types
v1: diameter 0.45, hole 0.2, Top Layer to Bottom Layer, tented both sides, 922 vias
v2: diameter 0.25, hole 0.1, Top Layer to Signal Layer 1, tented top, 142 vias
v3: diameter 0.25, hole 0.1, Signal Layer 1 to Signal Layer 2, 36 vias

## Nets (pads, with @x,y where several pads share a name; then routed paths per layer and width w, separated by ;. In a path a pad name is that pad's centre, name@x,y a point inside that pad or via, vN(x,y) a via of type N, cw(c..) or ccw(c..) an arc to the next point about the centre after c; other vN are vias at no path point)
2V8: C66.2 C67.2 CN7.39 CN7.40 Q4.1 Q5.1 R29.2 R34.2 SB9.2 TP12.1 | length 11.8
  Top Layer w0.2: v1(6.625,21.675) R34.2@8.35,21.675 8.2,21.825 8.2,22.725 Q5.1@7.85,23.075 ; v1(7.35,28.4) R29.2@8.325,28.4 8.2,28.525 8.2,29.425 Q4.1@7.825,29.8 ; v1(14,9.375) C66.2@14,10.075 14.04,10.035 CN7.39@15.61,10.035 ; CN7.40@18.16,10.035 19.71,10.035 C67.2@19.75,10.075 v1(19.75,9.375)
  Bottom Layer w0.2: 10.925,13.7 v1(12.15,13.7)
3V3: B3.3 B3.4 C5.1 C6.1 C8.2 C9.2 C37.2 C40.2 C51.1 C56.1 C57.1 C58.2 C59.1 C61.2 C62.2 C63.1 C64.1 C65.1 C68.1 C70.2 C71.1 C72.1 C73.2 C126.1 C127.1 CN4.6 CN4.12 CN9.3 CN10.1 CN11.1 CN17.2 CN17.4 JP3.2 LD6.1 LD7.1 M1.16 Q7.2 R1.1 R9.1 R10.2 R11.2 R32.2 R43.2 R54.2 R66.2 R72.2 SB2.1 SB8.1 SW1.1 SW3.1 TP5.1 U3.2 U4.2 U6.5 U7.5 U8.2 U17.6 U19.2 U21.1 U21.2 U21.3 U21.5 U21.8 U21.12 U22.2 U22.3 U22.8 U25.3 U25.9 U25.10 U26.1 U26.5 U26.6 U26.10 U27.A4 U27.B1 U27.B7 U28.1 U28.6 | length 95.3
  Top Layer w0.1: C9.2@71.825,53.2 C9.2@71.825,53 v1(71.825,52.175) 72.65,52.175 R11.2@72.85,52.375
  Top Layer w0.15: v1(11.425,22.05) R32.2@12.15,22.05
  Top Layer w0.2: v1(20.25,49.5) U8.2@20.25,50.2 ; v1(23.875,5.95) C70.2@25.2,5.95 25.125,5.875 C71.1@25.125,4.775 25.05,4.7 U28.1@25.05,3.675 ; v1(24.325,10.075) 24.325,10.8 24.575,11.05 26.187,11.05 U25.10@26.2,11.063 ; U28.6@25.3,2.925 v1(26.25,2.925) ; U17.6@26.255,25 26.975,25 27.195,25.22 27.195,25.245 27.35,25.4 C51.1@27.375,25.4 ; v1(26.475,20) 26.856,19.619 U22.8@26.856,19.072 ; U25.9@26.7,11.063 26.7,11.4 26.5,11.6 C63.1@26.5,12.125 26.425,12.2 26.425,13.175 C61.2@26.25,13.35 v1(26.95,13.35) ; U25.3@27.2,9.537 27.2,8.975 27.5,8.675 v1(28.35,8.675) ; U22.2@27.356,16.222 v1(27.356,15.456) 27.681,15.456 27.856,15.631 U22.3@27.856,16.222 ; v1(27.595,3.384) 27.916,3.384 U27.B1@28.375,2.925 ; v1(29.575,66.5) R1.1@29.575,67.6 ; R43.2@30.275,5.9 31.141,5.9 31.375,5.666 v1(31.375,5.075) 31.025,4.725 U27.A4@31.025,3.975 ; v1(30.85,18.75) 31.275,18.325 U21.12@31.875,18.325 ; v1(31.025,9.575) U26.5@31.763,9.575 ; v1(31.475,8.5) 32.088,8.5 32.275,8.688 U26.6@32.275,9.313 ; U21.1@32.125,16.575 32.125,15.8 32.275,15.65 v1(32.625,15.65) ; U21.2@32.625,16.575 v1(32.625,15.65) ; U26.1@32.775,10.838 32.775,10.85 33.325,11.4 33.325,11.7 C64.1@33.475,11.85 C62.2@34.575,11.85 ; v1(32.975,20.225) C57.1@33.775,20.225 33.625,20.075 U21.8@33.625,19.075 ; U21.3@33.125,16.575 33.125,15.775 33,15.65 v1(32.625,15.65) ; U26.10@33.288,10.575 33.7,10.575 33.9,10.775 C68.1@34.475,10.775 34.475,11.75 C62.2@34.575,11.85 ; U27.B7@33.675,2.925 C72.1@34.825,2.925 35.85,2.925 C73.2@35.925,2.85 36.75,2.85 v1(37.35,3.45) LD7.1@37.35,4.275 LD6.1@35.85,4.275 ; U21.5@33.875,17.325 C59.1@35.075,17.325 v1(35.075,16.1) ; v1(35.5,11.85) C62.2@34.575,11.85 ; B3.4@40.725,3.9 B3.3@40.725,9.5 ; U3.2@53.225,54.35 53.225,53.025 C8.2@53.2,53 v1(53.2,51.65) 54,51.65 54.225,51.875 R10.2@54.225,52.375 ; U19.2@54.925,21.125 C56.1@55.85,21.125 55.85,19.75 C58.2@56.425,19.75 v1(58.15,19.75) ; R9.1@58.75,53.85 v1(59.475,53.85) ; CN10.1@66.54,19.26 v1(66.54,20.365) ; CN9.3@66.54,29.857 v1(66.54,31.747) ; C9.2@71.825,53.2 U4.2@71.825,54.35
  Top Layer w0.5: SW3.1@12.675,48.275 v1(14.025,48.275) ; SW1.1@50.65,15.8 v1(50.65,16.925) ; v1(74.175,37.525) 74.175,37.3 73.7,36.825 73.275,36.825 C37.2@73.025,36.575 72.9,36.45 72.9,35.525 C40.2@72.775,35.4 73.475,35.4 75.28,33.595 M1.16@75.28,33.322
  Bottom Layer w0.2: Q7.2@32.825,21.5 32.975,21.35 v1(32.975,20.225) 33.57,20.225 33.725,20.07 R72.2@33.725,20.05 ; v1(45.95,17.2) 46.775,18.025 SB8.1@46.975,18.025 ; SB2.1@47.05,45.2 47.05,45.85 v1(48.825,47.625) ; CN17.4@50.28,9.024 v1(51.226,9.024) ; CN17.2@55.36,9.024 v1(55.36,10.81) ; v1(58.875,41.675) 58.875,41.003 C6.1@58.799,40.927 58.824,40.902 C127.1@59.849,40.902 59.882,40.935 U7.5@60.974,40.935 ; v1(62.225,43.125) R66.2@63.25,43.125 ; U6.5@62.513,66.742 64.401,66.742 C5.1@64.412,66.731 ; C5.1@64.8,66.75 v1(65.494,66.75)
  Bottom Layer w0.5: v1(74.175,37.525) 75.076,37.525 75.55,37.999 R54.2@75.55,38.55
  other v1: 40.725,6.75 26.725,25
3V3_BT: C1.2 C2.2 C3.2 CN5.1 SW3.2 U1.4 U1.6 U1.15 U1.17 U1.32 | length 12
  Top Layer w0.2: v1(1,63.125) C1.2@1,63.75 1.5,63.75 1.725,63.975 U1.6@2.325,63.975 ; U1.17@2.325,59 2.1,58.775 C2.2@1,58.775 1,58.325 1.45,57.875 v1(2.925,57.875) ; U1.15@2.325,59.925 v1(3.1,59.925) ; U1.4@2.325,64.875 2.95,64.875 3.175,64.65 v1(3.175,64.275) ; U1.32@8.675,59.475 9.25,59.475 9.45,59.675 C3.2@10.05,59.675 v1(10.775,59.675)
  Top Layer w0.5: SW3.2@10.925,45.975 v1(12.588,45.975)
3V3_STLK: C13.1 C14.1 C15.1 C16.1 C21.1 C22.1 C23.1 C24.1 C25.1 C28.1 C29.1 C31.1 C32.1 C33.1 C77.1 C80.1 C84.2 C85.1 C86.2 C87.1 C104.2 C106.2 CN6.1 LD3.4 R53.1 U32.C1 U32.C5 U32.C6 U32.C7 U32.C8 U32.C9 U32.F3 U32.G3 U32.G13 U32.H13 U32.J12 U32.J13 U32.K4 U32.N8 U32.N9 U32.N10 U32.P1 U32.R1 U35.5 X3.4 | length 32.9
  Top Layer w0.1: C29.1@67.575,43.825 67.575,43.85 v1(68.225,44.5) ; C24.1@67.575,45.2 C24.1@67.65,45.275 67.775,45.15 v1(68.225,45.15) ; C22.1@67.65,46.475 67.675,46.45 v1(68.225,46.45) ; v1(68.875,44.5) 69.4,44.5 C25.1@69.525,44.375 ; C31.1@69.9,41.025 69.9,41.625 v1(70.175,41.9) ; C14.1@70.7,49.6 70.825,49.475 v1(70.825,49.05) ; C32.1@70.825,41.025 v1(70.825,41.9) ; v1(71.475,41.9) 71.75,41.625 C33.1@71.75,41.025 ; v1(71.475,49.05) 71.475,49.45 C15.1@71.625,49.6 ; v1(72.775,49.05) C16.1@72.775,49.6 ; v1(74.075,49.05) 74.075,49.475 C13.1@74.225,49.625 ; v1(74.725,43.85) C28.1@75.35,43.85 ; C23.1@75.25,45.75 75.375,45.875 v1(75.375,46.45) ; C21.1@75.25,47.7 75.375,47.575 v1(75.375,47.1)
  Top Layer w0.2: LD3.4@90.175,39.275 v1(90.175,40.225)
  Bottom Layer w0.1: v1(65.775,39.825) C86.2@65.775,40.8 C84.2@65.775,42.175 ; U32.R1@76.35,40.925 76.75,40.525 C87.1@77.6,40.525 v1(77.6,39.925) ; U32.P1@76.35,41.575 76.45,41.475 C85.1@77.6,41.475 v1(77.6,42.075) ; U32.C1@76.35,48.725 C77.1@77.6,48.725 v1(77.6,49.325)
  Bottom Layer w0.12: v1(68.225,44.5) U32.J13@68.55,44.825 ; v1(68.225,45.15) U32.H13@68.55,45.475 ; v1(68.225,46.45) U32.G13@68.55,46.125 ; v1(68.875,44.5) U32.J12@69.2,44.825 ; v1(70.175,41.9) U32.N10@70.5,42.225 ; v1(70.825,41.9) U32.N9@71.15,42.225 ; v1(70.825,49.05) U32.C9@71.15,48.725 ; v1(71.475,41.9) U32.N8@71.8,42.225 ; v1(71.475,49.05) U32.C8@71.8,48.725 ; U32.C7@72.45,48.725 v1(72.775,49.05) ; U32.C6@73.1,48.725 v1(73.425,49.05) ; U32.C5@73.75,48.725 v1(74.075,49.05) ; U32.K4@74.4,44.175 v1(74.725,43.85) ; U32.G3@75.05,46.125 v1(75.375,46.45) ; U32.F3@75.05,46.775 v1(75.375,47.1)
  Bottom Layer w0.2: U35.5@81.475,24.7 C106.2@81.475,26.5 C104.2@81.475,27.65 v1(81.475,28.4) ; v1(82.725,42.155) R53.1@82.725,42.705 ; X3.4@82.725,46.1 82.895,46.27 C80.1@82.895,47.52 83.38,47.52 83.559,47.341 v1(83.559,47.092)
5V: C54.2 C118.2 CN2.6 CN2.15 CN3.6 CN3.15 CN17.5 JP4.2 JP4.4 JP4.6 JP4.8 R44.2 R57.1 SB16.2 U19.3 U29.1 U36.3 | length 92.3
  Top Layer w0.2: SB16.2@28.355,48.869 28.719,48.869 ; R44.2@57.15,2.4 U29.1@58.875,2.4 v1(58.875,1.825) v1(58.875,1.1)
  Signal Layer 2 w1: v1(55.725,23.6) 55.175,23.6 55.175,13.375 57.9,10.65 57.9,3.7 58.875,2.725 v1(58.875,1.825) 58.875,1.325
  Signal Layer 3 w0.2: v1(71.525,38.55) 73.079,38.55 73.644,37.985 79.215,37.985 79.9,37.3 79.9,28.375 80.925,27.35 81.75,27.35 82.27,27.87 82.27,38.32 82.75,38.8 93.175,38.8
  Signal Layer 3 w0.5: CN2.15@43.05,63.325 43.05,64.418 ; 45.05,60.232 CN2.6@45.05,61.325 ; CN3.15@79.525,63.325 79.525,64.418 ; 81.525,60.232 CN3.6@81.525,61.325
  Signal Layer 3 w1.5: v1(29.475,48.9) 29.475,52.275 32.246,55.046 32.246,58.256 33.075,59.085
  Bottom Layer w0.1: v1(71.525,38.55) R57.1@72.35,38.55
  Bottom Layer w0.2: v1(8.975,11) C118.2@8.975,11.925 U36.3@8.975,14.55
  Bottom Layer w0.5: v1(47.74,3.81) CN17.5@47.74,5.595
  other v1: 55.025,23.6 29.6,49.75
5V_UCPD: D3.1 JP4.5 SB15.2 | length 117.6
  Signal Layer 3 w0.5: 63.8,7.825 64.975,7.825 70.325,13.175 v1(78.925,13.175) v1(79.625,13.175)
  Signal Layer 3 w1: JP4.5@63.865,4.93 63.865,7.76
  Signal Layer 3 w1.5: 19.275,45.895 21.925,43.245 21.925,39.325 26.55,34.7 26.55,31.225 25.517,30.192 19.942,30.192 17.375,27.625 17.375,13.55 18.2,12.725 20.1,12.725 25.78,7.045 27.679,7.045 28.524,6.2 30.4,6.2 30.65,6.45 34.95,6.45 35.8,5.6 44.7,5.6 46.6,7.5 51.65,7.5 53,8.85 55.425,8.85 56.45,7.825 63.8,7.825 63.865,7.76
  Bottom Layer w0.5: v1(78.925,13.175) v1(79.625,13.175) D3.1@79.625,14.98
  other v1: 19.85,45.9 18.85,45.925
5V_USB_CHGR: C47.2 C53.2 CN8.1 D4.1 JP4.7 R33.2 R36.2 U15.1 U18.5 | length 82.1
  Top Layer w0.2: v1@92.4,30.25 v1(92.4,30.325) ; R36.2@96.075,20.4 96.125,20.45 v1(97.525,20.45) 97.525,21 97.35,21.175 R33.2@97.35,21.825
  Top Layer w0.4: v1@92.4,30.25 v1(92.4,29.6) 92.4,29 93.6,29 U15.1@93.775,29.175 93.95,29.175 94.375,29.6 CN8.1@95.825,29.6
  Top Layer w0.5: U18.5@96.55,25.125 C53.2@98.2,25.125 v1(98.2,26.225)
  Top Layer w0.8: v1(76.775,11.95) v1(77.55,11.95) 87.675,11.95 90.325,9.3 93.075,9.3 93.6,8.775 96.9,8.775 97.525,9.4 v1(97.525,11.95) v1(97.525,12.7)
  Signal Layer 2 w0.8: v1(92.4,30.325) 92.4,27 93.85,25.55 97.525,25.55 ; v1(97.525,11.95) v1(97.525,12.7) v1(97.525,20.45) 97.525,25.55 ; v1(98.2,26.225) 97.525,25.55
  Bottom Layer w0.8: JP4.7@61.325,4.93 64.245,7.85 68.95,7.85 73.05,11.95 v1(77.55,11.95) D4.1@77.55,14.98
5V_USB_STLK: C52.2 JP4.1 U18.1 | length 44.6
  Top Layer w0.5: v1(91.75,25.675) 92.012,25.413 92.712,25.413 92.81,25.315 93.81,25.315 93.95,25.175 94.3,25.175 U18.1@94.35,25.125
  Signal Layer 2 w0.8: v1(90.9,10.375) v1(91.75,10.375) v1(91.75,25.675)
  Bottom Layer w0.8: JP4.1@68.945,4.93 68.945,5.945 73.375,10.375 v1(90.9,10.375) v1(91.75,10.375)
5V_VIN: C116.2 D2.1 JP4.3 R63.2 U38.2 U38.4 | length 51.3
  Top Layer w1: v1(74.375,14.525) v1(75.075,14.525) 81.3,14.525 81.755,14.98 81.76,14.975 v1(82.55,14.975) v1(83.3,14.975)
  Signal Layer 2 w1: JP4.3@66.405,4.93 66.405,8.33 72.6,14.525 v1(74.375,14.525) v1(75.075,14.525)
  Signal Layer 3 w1: v1(82.55,14.975) v1(83.3,14.975)
  Bottom Layer w0.2: R63.2@57.9,2.75 v1(57.9,1.7) 59.9,3.7 65.175,3.7 JP4.3@66.405,4.93
  Bottom Layer w1: U38.2@62.075,12.3 U38.4@68.425,12.3 69.675,12.3 70.225,12.85 C116.2@70.225,13.52 72.545,13.52 73.55,14.525 v1(74.375,14.525) v1(75.075,14.525) ; D2.1@81.675,14.98 81.68,14.975 v1(82.55,14.975) v1(83.3,14.975)
AGND: C38.2 C39.1 C94.2 C95.1 SB3.2 U13.K2 | length 10.1
  Top Layer w0.08: U13.K2@44.329,34.1 44.579,34.35 45.669,34.35 46.544,35.225 C39.1@47.15,35.225 C38.2@47.975,35.225
  Top Layer w0.12: C38.2@47.975,35.225 48.225,35.225 C38.2@48.3,35.3 49.025,35.3 49.3,35.575 v1(49.3,35.95)
  Bottom Layer w0.08: C95.1@45.65,35.675 46.1,35.225 C94.2@46.8,35.225 47.975,35.225
  Bottom Layer w0.12: 47.975,35.225 48.125,35.225 SB3.2@48.3,35.4 48.575,35.675 49.025,35.675 v1(49.3,35.95)
ARD.D0_RX: CN14.1 U3.7 U13.L13 | length 68.5
  Top Layer w0.08: 34.7,38 35.05,38 38.45,34.6 U13.L13@38.829,34.6
  Top Layer w0.12: v1(33,38.9) 33.9,38 34.7,38 ; v1(34.78,58.225) 35.8,58.225 36.26,58.685 54.69,58.685 55.9,57.475 55.9,55.65 55.575,55.325 U3.7@54.6,55.325
  Signal Layer 2 w0.12: v1(33,38.9) 32.5,38.9 32.12,39.28 32.12,40.57 33.43,41.88 33.43,45.316 32.935,45.811 32.935,49.278 34.78,51.123 v1(34.78,58.225)
  Bottom Layer w0.12: CN14.1@22.34,57.284 22.483,57.142 25.917,57.142 26.21,57.435 26.21,58.55 26.745,59.085 33.92,59.085 v1(34.78,58.225)
ARD.D1_TX: CN14.2 U3.4 U13.L12 | length 72.7
  Top Layer w0.08: 34.7,38.375 34.979,38.375 38.504,34.85 39.079,34.85 U13.L12@39.329,34.6
  Top Layer w0.12: v1(32.525,39.475) 33.025,39.475 34.125,38.375 34.7,38.375 ; v1(35.55,58.7) 35.775,58.925 v1(55.525,58.925) ; U3.4@54.025,54.35 54.45,53.925 v1(55.125,53.925)
  Signal Layer 2 w0.12: v1(32.525,39.475) 32.525,40.636 33.67,41.781 33.67,45.416 33.524,45.561 33.175,45.911 33.175,49.179 35.55,51.554 v1(35.55,58.7) ; v1(55.125,53.925) 55.525,54.325 v1(55.525,58.925)
  Bottom Layer w0.12: CN14.2@24.755,53.15 24.88,53.275 24.88,53.855 v1(24.88,55.53) 26.45,57.1 26.45,58.45 26.845,58.845 33.587,58.845 34.652,57.78 35.255,57.78 35.55,58.075 v1(35.55,58.7)
ARD.D2_IO: CN14.3 U13.J11 | length 33.4
  Top Layer w0.08: v2(39.579,33.85) U13.J11@39.829,33.6
  Top Layer w0.12: v1(32.05,44.5) 35.113,41.437 v2(35.113,40)
  Signal Layer 1 w0.08: 35.113,39 35.113,37.912 38.925,34.1 39.221,34.1 39.471,33.85 v2(39.579,33.85)
  Signal Layer 1 w0.12: 35.113,39 v2(35.113,40)
  Signal Layer 2 w0.12: v1(26.55,46.775) 26.55,47.142 24.875,48.817 24.875,53.275 v1(27.125,55.525)
  Bottom Layer w0.12: v1(26.55,46.775) 27.7,45.625 31.491,45.625 32.05,45.066 v1(32.05,44.5) ; v1(27.125,55.525) 27.42,55.82 CN14.3@27.42,57.284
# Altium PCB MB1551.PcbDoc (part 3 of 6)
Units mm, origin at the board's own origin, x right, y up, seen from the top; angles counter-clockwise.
Board outline 100 x 70 mm, 6 copper layers (Top Layer, Signal Layer 1, Signal Layer 2, Signal Layer 3, Signal Layer 4, Bottom Layer), stack 1.49 mm thick; 325 components, 276 nets, 1540 pads, 1100 vias.

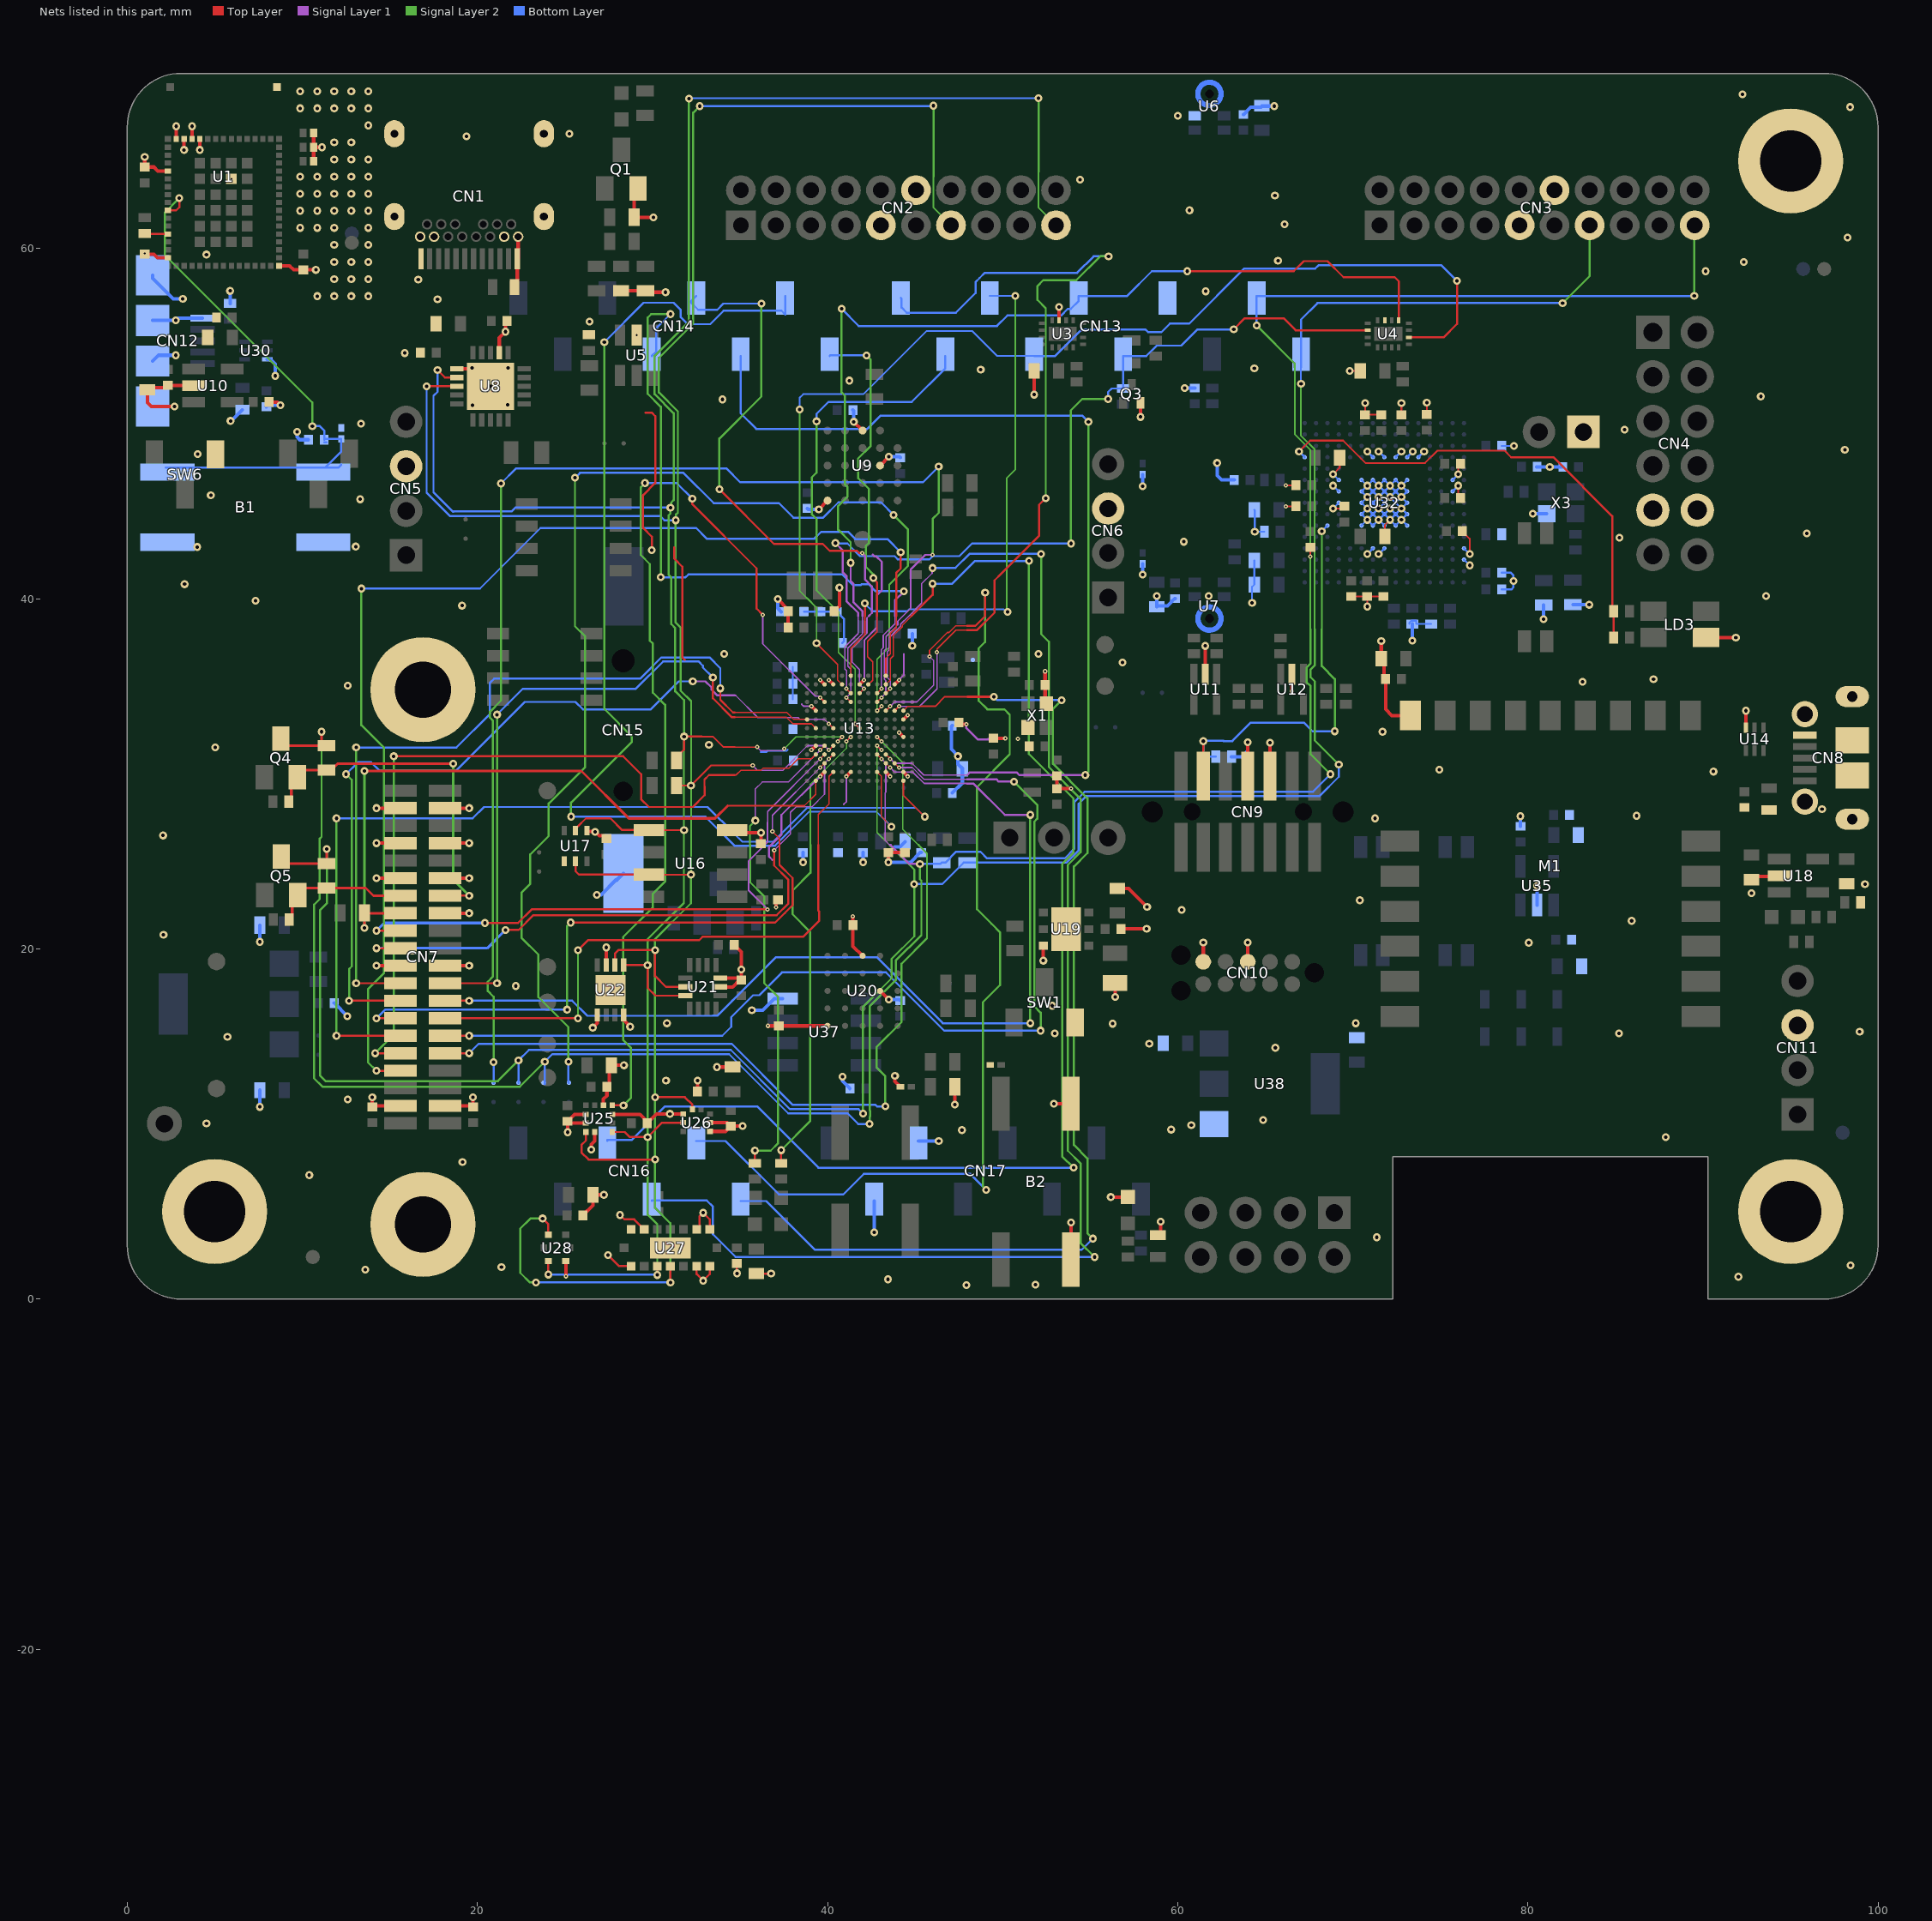
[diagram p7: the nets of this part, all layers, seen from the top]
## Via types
v1: diameter 0.45, hole 0.2, Top Layer to Bottom Layer, tented both sides, 922 vias
v2: diameter 0.25, hole 0.1, Top Layer to Signal Layer 1, tented top, 142 vias
v3: diameter 0.25, hole 0.1, Signal Layer 1 to Signal Layer 2, 36 vias

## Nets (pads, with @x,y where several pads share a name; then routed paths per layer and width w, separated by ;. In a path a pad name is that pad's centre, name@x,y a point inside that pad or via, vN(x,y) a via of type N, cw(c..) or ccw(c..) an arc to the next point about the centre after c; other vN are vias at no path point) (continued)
ARD.D3_TIM: CN14.4 U13.L5 | length 40.2
  Top Layer w0.08: U13.L5@42.829,34.6 v2(43.079,34.85)
  Signal Layer 1 w0.08: v2(43.079,34.85) 43.079,37.104 43.179,37.204 43.179,37.904 43.85,38.575 43.85,39
  Signal Layer 1 w0.12: 43.85,39 43.85,39.9 44.35,40.4 v1(44.35,40.425)
  Signal Layer 2 w0.12: v1(30.475,41.225) 30.475,50.95 29.725,51.7 29.725,56.05 29.925,56.25 v1(31.025,56.25)
  Bottom Layer w0.12: CN14.4@29.96,53.855 30.225,54.12 30.225,55.45 v1(31.025,56.25) ; v1(30.475,41.225) 30.48,41.22 31.893,41.22 32.053,41.38 40.845,41.38 41.455,40.77 41.897,40.77 41.957,40.83 42.343,40.83 42.748,40.425 v1(44.35,40.425)
ARD.D4_INT: CN14.5 U13.L7 | length 35.2
  Top Layer w0.08: U13.L7@41.829,34.6 v2(42.079,34.85)
  Top Layer w0.12: v1(33.82,46.25) 36.945,43.125 39.725,43.125 40.12,42.73 41.683,42.73 41.798,42.615 41.96,42.615 v2(41.975,42.6)
  Signal Layer 1 w0.08: v2(42.079,34.85) 41.829,35.1 41.829,35.946 41.4,36.375 41.4,37.173 42.25,38.023 42.25,38.9 42.35,39
  Signal Layer 1 w0.12: v2(41.975,42.6) 42.13,42.445 42.13,41.097 42.53,40.697 42.53,39.18 42.35,39
  Signal Layer 2 w0.12: v1(33.82,46.25) 33.82,49.145 36.225,51.55 v1(36.225,56.85)
  Bottom Layer w0.12: CN14.5@32.5,57.284 32.163,56.947 32.615,56.495 33.695,56.495 34.05,56.85 v1(36.225,56.85)
ARD.D5_TIM: CN14.6 U13.D4 | length 56.2
  Top Layer w0.08: U13.D4@43.329,31.1 v2(43.579,30.85)
  Signal Layer 1 w0.08: v2(43.579,30.85) 43.829,30.6 44.825,30.6 45.5,29.925 47.975,29.925
  Signal Layer 1 w0.12: 47.975,29.925 48.131,30.081 50.794,30.081 50.95,29.925 v1(54.725,29.925)
  Signal Layer 2 w0.12: v1(54.725,29.925) 54.9,30.1 v1(54.9,50.1)
  Bottom Layer w0.12: CN14.6@35.04,53.855 35.04,50.585 35.93,49.695 42.27,49.695 43.025,50.45 54.55,50.45 v1(54.9,50.1)
ARD.D6_TIM: CN14.7 U13.B5 | length 66.3
  Top Layer w0.08: U13.B5@42.829,30.1 43.079,29.85 43.079,27.546 v1(43.65,26.975)
  Signal Layer 2 w0.12: v1(25.35,27.55) 25.35,28.347 28.825,31.822 28.825,32.125 27.25,33.7 27.25,36.1 v1(27.25,54.65)
  Bottom Layer w0.1: 37.034,25.925 38.934,27.825 42.8,27.825 v1(43.65,26.975)
  Bottom Layer w0.12: v1(25.35,27.55) 33.025,27.55 34.7,25.875 36.984,25.875 37.034,25.925 ; v1(27.25,54.65) 29.5,56.9 31.2,56.9 31.6,56.5 31.6,56.09 32.015,55.675 33.3,55.675 34.07,56.445 37.365,56.445 37.58,56.23 CN14.7@37.58,57.284
ARD.D7_IO: CN14.8 U13.M6 | length 22.3
  Top Layer w0.08: U13.M6@42.329,35.1 42.336,35.1 42.579,35.343 42.579,36.396 42.285,36.69 42.285,37.563 42.825,38.103 42.825,39
  Top Layer w0.12: v1(42.625,41.175) 42.625,41.125 42.825,40.925 42.825,39
  Signal Layer 2 w0.12: v1(42.225,53.891) 42.465,53.651 42.465,48.726 41.75,48.011 41.75,46.875 42.365,46.26 42.365,43.192 42.2,43.027 42.2,41.8 42.625,41.375 v1(42.625,41.175)
  Bottom Layer w0.12: CN14.8@40.12,53.856 40.155,53.891 v1(42.225,53.891)
ARD.D8_IO: CN13.1 U13.J3 | length 48.4
  Top Layer w0.08: v2(46.25,36.95) 46.25,37.128 47.327,38.205 47.975,38.205
  Top Layer w0.1: U13.J3@43.829,33.6 v2(44.079,33.85)
  Top Layer w0.12: 47.975,38.205 48.542,38.205 49.536,39.199 49.536,41.043 49.924,41.43 52.075,43.582 52.075,45.35 v1(52.462,45.738)
  Signal Layer 1 w0.08: v2(44.079,33.85) 45.254,33.85 46.25,34.846 v2(46.25,36.95)
  Signal Layer 2 w0.12: v1(52.462,45.738) 52.462,56.588 51.992,57.058 51.992,57.854 52.322,58.185 54.21,58.185 55.575,59.55 v1(56.05,59.55)
  Bottom Layer w0.12: CN13.1@44.184,57.172 44.225,57.131 44.225,56.625 44.518,56.332 47.332,56.332 48.45,57.45 48.45,58.075 48.679,58.305 48.983,58.608 54.258,58.608 55.2,59.55 v1(56.05,59.55)
ARD.D9_TIM: CN13.2 U13.G7 | length 29
  Top Layer w0.08: v2(41.579,32.85) v3(41.829,32.6)
  Signal Layer 1 w0.08: v2(41.579,32.85) v3(41.829,32.6)
  Signal Layer 2 w0.08: 40.623,39 40.623,36.927 41.579,35.971 v2(41.579,32.85) v3(41.829,32.6)
  Signal Layer 2 w0.12: v1(39.375,50.125) 39.375,47.2 39.095,46.92 39.095,44.83 39.375,44.55 39.375,40.475 40.623,39.227 40.623,39
  Bottom Layer w0.12: v1(39.375,50.125) 39.375,50.55 40.06,51.235 44.81,51.235 46.724,53.149 CN13.2@46.724,53.855
ARD.D10_TIM_SPI1_NSS: CN13.3 U13.N8 | length 32.6
  Top Layer w0.08: U13.N8@41.329,35.6 41.329,37.154 42.13,37.955 42.13,39
  Top Layer w0.12: v1(42.125,39.725) 42.13,39.72 42.13,39
  Signal Layer 2 w0.1: v1(50.28,39.245) 50.24,39.285 50.24,46.89 50.72,47.37 v1(50.72,57.284)
  Bottom Layer w0.1: v1(42.125,39.725) 42.57,39.28 44.539,39.28 44.659,39.4 50.046,39.4 50.201,39.245 v1(50.28,39.245) ; CN13.3@49.264,57.284 v1(50.72,57.284)
ARD.D11_TIM_SPI1_MOSI: CN13.4 U4.6 U13.M9 | length 65.2
  Top Layer w0.08: v1(39.375,37.45) 40.579,36.246 40.579,35.35 U13.M9@40.829,35.1
  Top Layer w0.12: U4.6@73.2,54.925 73.2,54.92 75.183,54.92 75.95,55.687 v1(75.95,58.15)
  Signal Layer 2 w0.08: v1(39.375,37.45) 39.375,39
  Signal Layer 2 w0.1: v1(38.4,50.8) 38.4,40.45 38.838,40.012
  Signal Layer 2 w0.12: 38.838,40.012 39.375,39.475 39.375,39
  Bottom Layer w0.1: v1(38.4,50.8) 38.4,51.462 38.613,51.675 42.05,51.675 45.65,55.275 48.275,55.275 49.695,53.855 CN13.4@51.804,53.855
  Bottom Layer w0.12: CN13.4@51.804,53.855 52.993,53.855 54.497,55.36 58.167,55.36 58.307,55.22 59.07,55.22 59.558,55.708 60.658,55.708 63.8,58.85 67.852,58.85 68.037,59.035 75.065,59.035 v1(75.95,58.15)
ARD.D12_SPI1_MISO: CN13.5 U4.9 U13.K8 | length 60.6
  Top Layer w0.08: v2(41.079,34.35) U13.K8@41.329,34.1
  Top Layer w0.12: v1(60.55,58.7) 66.625,58.7 67.2,59.275 68.55,59.275 69.47,58.355 72.393,58.355 72.63,58.118 72.63,55.905 U4.9@72.625,55.9
  Signal Layer 1 w0.08: v2(41.079,34.35) 41.329,34.6 41.329,35.971 41.159,36.141 41.159,37.166 41.99,37.997 41.99,39
  Signal Layer 1 w0.12: v1(41.32,42.045) 41.32,41.007 41.475,40.852 41.475,39.802 41.99,39.287 41.99,39
  Signal Layer 2 w0.12: v1(40.8,56.55) 40.8,51.775 41,51.575 41,46.512 41.145,46.367 41.145,45.833 40.602,45.29 40.602,43.942 41.32,43.224 v1(41.32,42.045)
  Bottom Layer w0.12: v1(40.8,56.55) 41.775,55.575 49.677,55.575 50.272,56.17 53.342,56.17 53.724,56.553 53.894,56.553 54.344,57.003 CN13.5@54.344,57.172 54.344,57.284 57.109,57.284 58.525,58.7 v1(60.55,58.7)
ARD.D13_SPI1_SCK: CN13.6 R48.1 U4.14 U13.L8 | length 52.1
  Top Layer w0.08: v2(41.079,34.85) U13.L8@41.329,34.6
  Top Layer w0.12: v1(63.2,55.375) 63.834,56.009 66.05,56.009 66.734,55.325 U4.14@70.85,55.325
  Signal Layer 1 w0.08: v2(41.079,34.85) 41.079,35.896 40.994,35.981 40.994,37.244 41.75,38 41.75,39
  Signal Layer 1 w0.12: v1(40.45,43.175) 40.875,42.75 40.875,41.5 41.08,41.295 41.08,39.858 41.75,39.188 41.75,39
  Signal Layer 2 w0.12: v1(53.9,43.15) 53.895,43.155 53.895,50.75 54.545,51.4 v1(56.025,51.4)
  Bottom Layer w0.12: v1(40.45,43.175) 40.474,43.151 41.139,43.151 41.864,42.425 43.827,42.425 44.007,42.245 45.82,42.245 46,42.425 47.525,42.425 48.25,43.15 v1(53.9,43.15) ; v1(56.025,51.4) 56.025,51.8 56.225,52 R48.1@56.875,52 56.875,53.846 56.884,53.855 58.205,53.855 58.8,54.45 60.2,54.45 61.125,55.375 v1(63.2,55.375)
ARD_ADC.A0: CN16.1 U13.J2 | length 63.5
  Top Layer w0.08: U13.J2@44.329,33.6 44.579,33.85 45.334,33.85
  Top Layer w0.1: 45.334,33.85 46.15,33.85 46.7,34.4 47.975,34.4
  Top Layer w0.15: 47.975,34.4 v1(49.5,34.4)
  Signal Layer 2 w0.12: v1(53.375,34.2) 52.875,33.7 52.875,30.564 54.845,28.594 54.845,25.47 54.075,24.7 54.075,8.795 54.845,8.025 54.845,3.755 v1(55.15,3.45)
  Bottom Layer w0.12: CN16.1@35.04,5.596 36.504,5.596 39.295,2.805 54.505,2.805 v1(55.15,3.45) ; v1(49.5,34.4) 49.7,34.2 v1(53.375,34.2)
ARD_ADC.A1: CN16.2 U13.J4 | length 66.8
  Top Layer w0.08: v2(45.825,36.7) 45.825,37.05 46.84,38.065 46.94,38.065 47.32,38.445 47.975,38.445
  Top Layer w0.1: U13.J4@43.329,33.6 v2(43.579,33.85)
  Top Layer w0.12: 47.975,38.445 48.443,38.445 49,39.002 v1(49,40.35)
  Signal Layer 1 w0.08: v2(43.579,33.85) 43.829,34.1 45.104,34.1 46.05,35.046 46.05,36.475 v2(45.825,36.7)
  Signal Layer 2 w0.12: v1(49,40.35) 49,37.525 48.63,37.155 48.63,34.17 49.125,33.675 50.1,33.675 50.405,33.37 50.405,31.105 48.53,29.23 48.53,22.27 49.37,21.43 49.85,20.95 49.85,17.925 48.87,16.945 48.87,6.42 v1(49.057,6.233)
  Bottom Layer w0.12: CN16.2@32.5,9.025 34.175,9.025 37.225,5.975 40.9,5.975 42.075,7.15 48.154,7.15 48.428,6.876 48.428,6.862 v1(49.057,6.233)
ARD_ADC.A2: CN16.3 U13.L4 | length 84.5
  Top Layer w0.08: U13.L4@43.329,34.6 v2(43.579,34.85)
  Signal Layer 1 w0.08: v2(43.579,34.85) 43.579,35.33 43.409,35.5 43.409,36.968 43.509,37.068 43.509,37.768 44.18,38.438 44.18,38.544 44.636,39 45.38,39.744 45.38,40.855 45.971,41.446 v1@45.971,41.721
  Signal Layer 1 w0.12: v1@45.971,41.721 v1(46,41.75)
  Signal Layer 2 w0.12: v1(52.195,42.555) 52.195,37.98 52.635,37.54 52.635,30.39 54.455,28.57 54.455,25.525 53.725,24.795 53.725,8.475 54.455,7.745 54.455,3.195 v1(55.25,2.4)
  Bottom Layer w0.12: CN16.3@29.96,5.596 29.96,5.63 33.095,5.63 33.45,5.275 33.45,3.7 34.75,2.4 v1(55.25,2.4) ; v1(46,41.75) 47.3,41.75 48.105,42.555 v1(52.195,42.555)
ARD_ADC.A3: CN16.4 U13.M4 | length 78.1
  Top Layer w0.08: U13.M4@43.329,35.1 43.579,35.35 43.579,36.554 43.755,36.73 43.755,37.892 44.265,38.402 44.265,38.479 44.786,39
  Top Layer w0.12: 44.786,39 44.885,39.099 46,40.214 v1(46,40.85)
  Signal Layer 2 w0.12: v1(51.5,42.15) 51.5,31.125 54.05,28.575 54.05,25.5 53.4,24.85 53.4,8.15 v1(54.05,7.5)
  Bottom Layer w0.12: CN16.4@27.42,9.025 27.42,9.08 28.805,9.08 30.725,11 35.975,11 39.475,7.5 v1(54.05,7.5) ; v1(46,40.85) 47.125,40.85 48.425,42.15 v1(51.5,42.15)
ARD_ADC.A4: SB10.1 U13.J5 | length 70.4
  Top Layer w0.08: v3(42.829,33.6) v2(43.079,33.85)
  Signal Layer 1 w0.08: v3(42.829,33.6) v2(43.079,33.85)
  Signal Layer 2 w0.08: v3(42.829,33.6) 42.829,36.529 43.525,37.225 43.525,39
  Signal Layer 2 w0.12: v1(25.2,13.55) 25.2,15.525 23.48,17.245 23.48,19.668 22.52,20.628 22.52,23.208 23.02,23.708 23.02,25.395 24.075,26.45 24.075,28.3 26.16,30.385 26.16,37.84 25.575,38.425 v1(25.575,46.9) ; 43.525,39 43.525,40.8 44.6,41.875 44.6,43.95 v1(43.775,44.775)
  Bottom Layer w0.12: v1(25.2,13.55) 25.2,12.375 SB10.1@25.225,12.35 ; v1(25.575,46.9) 25.86,47.185 31.765,47.185 33.5,45.45 37.225,45.45 38.05,44.625 39.75,44.625 40.625,45.5 43.05,45.5 v1(43.775,44.775)
ARD_ADC.A5: SB13.1 U13.K5 | length 76.1
  Top Layer w0.08: U13.K5@42.829,34.1 v2(43.079,34.35)
  Signal Layer 1 w0.08: v2(43.079,34.35) 43.329,34.6 43.329,34.746 43.329,35.315 43.244,35.4 43.244,37.036 43.344,37.136 43.344,37.836 44.015,38.507 44.015,38.725 44.021,38.725 44.296,39 44.75,39.454 44.75,41.675
  Signal Layer 1 w0.12: 44.75,41.675 45.575,42.5 v3(46,42.5)
  Signal Layer 2 w0.12: v1(20.925,13.525) 20.925,17.262 20.6,17.587 20.6,18.123 20.88,18.403 20.88,33.047 20.72,33.207 20.72,33.543 21.35,34.173 v1(21.35,46.575) ; v3(46,42.5) 46,44.55 46.35,44.9 v1(46.35,47.55)
  Bottom Layer w0.12: SB13.1@20.925,12.35 v1(20.925,13.525) ; v1(21.35,46.575) 22.2,47.425 34.235,47.425 35.01,46.65 45.45,46.65 v1(46.35,47.55)
BOOT0: R3.1 U1.13 | length 1.3
  Top Layer w0.12: R3.1@1,60.85 1.025,60.825 U1.13@2.325,60.825
BT_NRST: B1.1 B1.2 C17.2 U1.10 U39.1 | length 32.7
  Top Layer w0.12: U1.10@2.325,62.175 2.8,62.175 2.975,62.35 v1(2.975,62.875)
  Signal Layer 2 w0.12: v1(2.975,62.875) 2.15,62.05 2.15,59.625 10.575,51.2 v1(10.575,49.85)
  Bottom Layer w0.12: B1.2@2.2,47.475 B1.1@11.3,47.475 ; v1(10.575,49.85) 11,49.85 11.25,49.6 11.25,49.125 C17.2@11.25,49.075 11.3,49.125 U39.1@12.225,49.125 12.225,48.4 B1.1@11.3,47.475 ; C17.2@11.25,48.92 C17.2@11.391,48.92 ; B1.1@12.225,47.65 12.05,47.475 B1.1@11.3,47.475
CAM.D0: CN7.23 U13.H13 | length 47.4
  Top Layer w0.08: 34.7,33.5 37.675,33.5 38.075,33.1 U13.H13@38.829,33.1
  Top Layer w0.12: v1(13.075,18.035) CN7.23@15.61,18.035 ; v1(33.875,34.875) 33.875,34.225 34.6,33.5 34.7,33.5
  Signal Layer 2 w0.12: v1(13.075,18.035) v1(13.075,31.5)
  Bottom Layer w0.12: v1(13.075,31.5) 18.8,31.5 20.72,33.42 20.72,35.193 20.957,35.43 29.291,35.43 30.506,36.645 33.255,36.645 33.875,36.025 v1(33.875,34.875)
CAM.D1: CN7.24 U13.G12 | length 40.1
  Top Layer w0.08: 34.7,33.225 37.65,33.225 38.025,32.85 39.079,32.85 U13.G12@39.329,32.6
  Top Layer w0.12: CN7.24@18.16,18.035 v1(21.125,18.035) ; v1(33.45,35.5) 33.45,34.311 34.536,33.225 34.7,33.225
  Signal Layer 2 w0.12: v1(21.125,18.035) v1(21.125,33.375)
  Bottom Layer w0.12: v1(21.125,33.375) 22.6,34.85 29.05,34.85 30.605,36.405 32.643,36.405 32.88,36.168 32.88,36.07 v1(33.45,35.5)
CAM.D2: CN7.25 U13.G10 | length 48
  Top Layer w0.08: v2(40.079,32.85) U13.G10@40.329,32.6
  Top Layer w0.12: v1@12.675,17.035 CN7.25@15.61,17.035
  Signal Layer 1 w0.08: 34.7,34.47 34.755,34.47 36.015,33.21 38.315,33.21 38.425,33.1 39.476,33.1 39.683,33.1 39.829,33.1 v2(40.079,32.85)
  Signal Layer 1 w0.12: v1(32.3,35.275) 33.025,35.275 33.38,34.92 33.38,34.797 33.707,34.47 34.7,34.47
  Signal Layer 2 w0.12: v1(12.5,29.975) 12.83,29.645 12.83,19.005 12.67,18.845 v1(12.67,17.035)
  Bottom Layer w0.12: v1(12.5,29.975) 13.175,30.65 13.93,30.65 14.405,30.175 18.788,30.175 22.713,34.1 25.6,34.1 26.025,33.675 29.9,33.675 31.5,35.275 v1(32.3,35.275)
CAM.D3: CN7.26 U13.C4 | length 58.1
  Top Layer w0.08: U13.C4@43.329,30.6 v2(43.579,30.35)
  Top Layer w0.12: CN7.26@18.16,17.035 v1(19.535,17.035)
  Signal Layer 1 w0.08: v2(43.579,30.35) 43.829,30.1 44.329,30.1 44.858,30.1 45.513,29.445 47.975,29.445
  Signal Layer 1 w0.12: 47.975,29.445 48.33,29.445 50.13,27.645 51.57,27.645 v1(51.575,27.65)
  Signal Layer 2 w0.12: v1(51.575,15.75) v1(51.575,27.65)
  Bottom Layer w0.12: v1(19.535,17.035) 25.415,17.035 26.275,16.175 33.452,16.175 33.457,16.18 33.705,16.18 34.56,17.035 37.05,19.525 42.808,19.525 46.583,15.75 v1(51.575,15.75)
CAM.D4: CN7.27 U13.C11 | length 40.4
  Top Layer w0.08: v2(36.85,26.7) 37.255,26.295 37.255,25.925 ; v2(39.579,30.35) U13.C11@39.829,30.6
  Top Layer w0.12: v1(14.235,16.035) CN7.27@15.61,16.035 ; v1(25.325,21.5) 36.614,21.5 37.011,21.5 37.55,22.039 38,22.489 38,24.05 37.255,24.795 37.255,25.925
  Signal Layer 1 w0.08: v2(36.85,26.7) 36.85,27.621 v2(39.579,30.35)
  Signal Layer 2 w0.12: v1(25.125,16.525) 25.125,21.3 v1(25.325,21.5)
  Bottom Layer w0.12: v1(14.235,16.035) 14.725,16.525 v1(25.125,16.525)
CAM.D5: CN7.28 U13.B10 | length 34.8
  Top Layer w0.08: 39.475,25.925 39.475,27.667 40.079,28.271 40.079,29.85 U13.B10@40.329,30.1
  Top Layer w0.12: CN7.28@18.16,16.035 v1(25.745,16.035) ; v1@25.747,19.923 26.311,20.486 32.661,20.486 32.86,20.685 38.608,20.685 39.525,21.602 39.525,22.125 39.475,22.175 39.475,25.925
  Signal Layer 2 w0.12: v1(25.745,16.035) v1(25.745,19.925)
CAM.D6: CN7.29 U13.A2 | length 54.3
  Top Layer w0.08: 44.329,29.1 U13.A2@44.329,29.6
  Top Layer w0.1: 44.329,29.1 44.329,28.771 v1(45.55,27.55)
  Top Layer w0.12: v1(11.95,15.035) CN7.29@15.61,15.035
  Signal Layer 2 w0.12: v1(11.95,15.035) v1(11.95,27.45)
  Bottom Layer w0.08: 39.95,28.05 45.05,28.05 v1(45.55,27.55)
  Bottom Layer w0.1: 34.7,26.55 35.125,26.125 36.91,26.125 38.835,28.05 39.95,28.05
  Bottom Layer w0.12: v1(11.95,27.45) 19.725,27.45 20.375,28.1 32.575,28.1 33.15,28.1 34.7,26.55
CAM.D7: CN7.30 U13.C3 | length 59.5
  Top Layer w0.08: U13.C3@43.829,30.6 v2(44.079,30.35)
  Top Layer w0.12: CN7.30@18.16,15.035 v1(19.535,15.035)
  Signal Layer 1 w0.08: v2(44.079,30.35) 44.842,30.35 45.507,29.685 47.975,29.685
  Signal Layer 1 w0.12: 47.975,29.685 49.64,29.685 49.775,29.55 v1(50.65,29.55)
  Signal Layer 2 w0.12: v1(50.65,29.55) 51.98,28.22 51.98,27.43 51.815,27.265 51.815,16.71 52.175,16.35 v1(52.175,15.325)
  Bottom Layer w0.12: v1(19.535,15.035) 33.985,15.035 34.5,15.55 34.5,16.1 35.75,17.35 36.1,17.35 37.4,18.65 43.343,18.65 46.668,15.325 v1(52.175,15.325)
CAM.HSYNC: CN7.31 U13.D12 | length 46.8
  Top Layer w0.08: 34.7,29.925 34.775,29.925 35.05,30.2 36.2,30.2 36.325,30.325 37.8,30.325 38.325,30.85 39.079,30.85 U13.D12@39.329,31.1
  Top Layer w0.12: v1(14.16,14.035) CN7.31@15.61,14.035 ; v1(15.225,31) 28.325,31 29.35,29.975 29.35,28.55 29.8,28.1 32.3,28.1 32.975,28.775 32.975,29.272 32.97,29.277 32.97,29.67 33.225,29.925 34.7,29.925
  Signal Layer 2 w0.12: v1(14.16,14.035) 15.225,15.1 v1(15.225,31)
CAM.PIXCLK: CN7.33 U13.N4 | length 70.6
  Top Layer w0.08: U13.N4@43.329,35.6 43.329,36.596 43.59,36.857 43.59,38.015 43.925,38.35 43.925,39
  Top Layer w0.12: v1(14.235,13.035) CN7.33@15.61,13.035 ; 43.925,39 43.925,41.475 44.175,41.725 v1(44.175,42.65)
  Signal Layer 2 w0.12: v1(13.375,40.575) 13.375,32.775 14.675,31.475 14.675,18.625 13.75,17.7 13.75,13.52 v1(14.235,13.035)
  Bottom Layer w0.12: v1(13.375,40.575) 20.15,40.575 23.605,44.03 32.495,44.03 33.1,43.425 39.245,43.425 39.64,43.82 41.168,43.82 41.588,43.4 43.425,43.4 v1(44.175,42.65)
CAM.PLUG: CN7.15 R32.1 U13.A12 | length 40.1
  Top Layer w0.08: 34.7,28.175 38.675,28.175 39.329,28.829 U13.A12@39.329,29.6
  Top Layer w0.12: 34.3,28.175 34.7,28.175
  Top Layer w0.15: v1(13.55,21.2) R32.1@13.55,22.05 13.565,22.035 CN7.15@15.61,22.035 ; v1(13.55,30.16) 25.94,30.16 28.65,27.45 33.575,27.45 34.3,28.175
  Signal Layer 2 w0.15: v1(13.55,21.2) v1(13.55,30.16)
CAM.RSTI: CN7.17 U13.D11 | length 35.3
  Top Layer w0.08: v2(39.579,30.85) U13.D11@39.829,31.1
  Top Layer w0.12: v1(14.235,21.035) CN7.17@15.61,21.035 ; v1(20.425,21.475) 21.427,21.475 21.432,21.48 21.768,21.48 21.773,21.475 22.325,21.475 23.1,22.25 v2(36.575,22.25)
  Signal Layer 1 w0.08: 36.575,27.223 36.575,27.846 v2(39.579,30.85)
  Signal Layer 1 w0.1: v2(36.575,22.25) 35.5,23.325 35.5,25.025 36.575,26.1 36.575,27.223
  Bottom Layer w0.15: v1(14.235,21.035) 14.675,21.475 v1(20.425,21.475)
CAM.VSYNC: CN7.32 U13.F5 | length 51.2
  Top Layer w0.08: v3(42.829,32.1) v2(43.079,31.85)
  Top Layer w0.12: CN7.32@18.16,14.035 v1(19.535,14.035)
  Signal Layer 1 w0.08: v3(42.829,32.1) v2(43.079,31.85)
  Signal Layer 2 w0.08: v3(42.829,32.1) 44.3,30.629 44.3,26.825 45.2,25.925
  Signal Layer 2 w0.12: v1(43.3,11) 43.3,12.725 42.809,13.216 42.809,14.406 44.225,15.822 44.225,19.15 45.68,20.605 45.68,25.445 45.2,25.925
  Bottom Layer w0.12: v1(19.535,14.035) 20.075,14.575 34.525,14.575 38.015,11.085 42.74,11.085 42.825,11 v1(43.3,11)
CAM.XSDN: CN7.19 U13.D10 | length 37.1
  Top Layer w0.08: v2(40.079,30.85) U13.D10@40.329,31.1
  Top Layer w0.12: v1(14.235,20.035) CN7.19@15.61,20.035 ; v1(21.6,21.075) 22.356,21.075 23.206,21.925 36.7,21.925 37.096,21.925 37.76,22.589 37.76,23.951 37.717,23.994 36.95,24.761 ; 36.95,25.15 36.95,24.761 ; v2(36.95,25.625) 36.95,24.761
  Signal Layer 1 w0.08: v2(36.95,25.625) 37.879,26.554 37.879,27.787 38.207,28.115 39.114,28.115 39.829,28.831 39.829,30.6 v2(40.079,30.85)
  Bottom Layer w0.15: v1(14.235,20.035) 20.56,20.035 v1(21.6,21.075)
GND: B1.3 B1.4 B2.3 B2.4 C1.1 C2.1 C3.1 C4.1 C5.2 C6.2 C8.1 C9.1 C11.2 C12.2 C13.2 C14.2 C15.2 C16.2 C17.1 C18.1 C19.1 C20.1 C21.2 C22.2 C23.2 C24.2 C25.2 C26.1 C27.1 C28.2 C29.2 C30.1 C31.2 C32.2 C33.2 C34.1 C35.1 C36.1 C37.1 C40.1 C41.2 C42.1 C43.1 C44.2 C45.2 C46.2 C47.1 C48.1 C49.1 C50.1 C51.2 C52.1 C53.1 C54.1 C55.1 C56.2 C57.2 C58.1 C59.2 C60.1 C61.1 C62.1 C63.2 C64.2 C65.2 C66.1 C67.1 C68.2 C69.1 C70.1 C71.2 C72.2 C73.1 C74.2 C75.1 C76.1 C77.2 C78.1 C79.2 C80.2 C81.2 C82.1 C83.1 C84.1 C85.2 C86.1 C87.2 C88.1 C89.1 C90.1 C91.1 C92.1 C93.1 C96.1 C97.1 C98.1 C99.1 C100.1 C101.1 C102.2 C103.1 C104.1 C105.1 C106.1 C107.1 C108.1 C109.1 C110.1 C111.1 C112.1 C113.1 C114.1 C115.1 C116.1 C117.1 C118.1 C119.1 C120.1 C121.1 C122.1 C123.1 C124.2 C125.2 C126.2 C127.2 CN1.A1 CN1.A12 CN1.B1 CN1.B12 CN1.SH1 CN1.SH2 CN1.SH3 CN1.SH4 CN2.5 CN2.16 CN3.5 CN3.16 CN4.5 CN4.11 CN5.3 CN6.3 CN7.3 CN7.4 CN7.7 CN7.8 CN7.11 CN7.12 CN7.16 CN7.21 CN7.22 CN7.37 CN7.38 CN7.41 CN7.42 CN8.5 CN8.6 CN8.7 CN8.8 CN8.9 CN8.10 CN8.11 CN9.5 CN9.7 CN10.3 CN10.5 CN11.3 CN12.5 CN12.EXP1 CN12.EXP2 CN12.SH1 CN12.SH2 CN13.7 CN15.2 CN17.6 CN17.7 H1.1 H3.1 H4.1 JP1.1 LD3.1 LD5.2 M1.17 Q1.2 Q3.2 R2.1 R6.1 R8.2 R31.1 R40.1 R46.1 R51.1 R52.1 R55.2 R56.1 R58.1 R61.1 R64.2 R65.2 SB3.1 SW1.3 SW6.1 U1.5 U1.16 U1.31 U1.57 U1.58 U1.59 U1.60 U1.84 U1.86 U2.2 U3.11 U4.11 U5.2 U6.2 U6.3 U7.3 U8.12 U8.16 U8.21 U9.B3 U9.C1 U9.E5 U10.2 U11.2 U12.2 U13.B2 U13.B4 U13.B8 U13.B11 U13.E12 U13.F2 U13.H2 U13.J12 U13.M3 U13.M7 U13.M10 U13.M11 U14.3 U15.2 U16.4 U17.1 U17.4 U18.2 U19.6 U19.EP U20.B3 U20.C1 U20.E5 U21.6 U21.7 U22.1 U22.4 U22.7 U22.EP U23.2 U24.2 U25.2 U25.6 U25.8 U25.11 U25.12 U26.3 U26.8 U26.9 U27.A1 U27.A2 U27.A6 U27.A7 U27.B4 U27.C1 U27.C6 U27.C7 U28.5 U29.2 U30.3 U31.2 U32.D5 U32.D6 U32.D7 U32.D8 U32.D9 U32.F2 U32.F6 U32.F7 U32.F8 U32.F9 U32.F10 U32.F12 U32.G2 U32.G6 U32.G7 U32.G8 U32.G9 U32.G10 U32.G12 U32.H6 U32.H7 U32.H8 U32.H9 U32.H10 U32.H12 U32.J6 U32.J7 U32.J8 U32.J9 U32.J10 U32.K6 U32.K7 U32.K8 U32.K9 U32.K10 U32.M1 U32.M8 U32.M9 U32.N1 U33.2 U34.2 U35.2 U37.4 U38.1 U39.2 X1.2 X1.4 X3.2 | length 295.9
  Top Layer w0.1: v2(66.175,45.275) C24.2@66.75,45.275 ; v2(66.175,46.475) C22.2@66.75,46.475 ; v2(67.575,42.405) C29.2@67.575,42.925 ; v1(68.875,45.15) 69.4,45.15 C25.2@69.525,45.275 ; v1(68.875,47.1) 69.25,47.475 C20.1@69.25,48.05 ; v1(69.825,53) C9.1@70.425,53 ; C31.2@69.9,40.125 C32.2@70.825,40.125 ; v1(70.7,51.175) C14.2@70.7,50.5 C15.2@71.625,50.5 ; v1(70.825,39.55) C32.2@70.825,40.125 ; C33.2@71.75,40.125 C32.2@70.825,40.125 ; C30.1@71.825,43.55 71.825,44.2 v1(72.125,44.5) ; C16.2@72.775,50.5 v1(72.775,51.175) ; C13.2@74.225,50.525 v1(74.225,51.2) ; v1(76.025,46.45) 76.025,45.875 C23.2@76.15,45.75 ; v1(76.025,47.1) 76.025,47.575 C21.2@76.15,47.7 ; C28.2@76.25,43.85 76.675,43.425 v1(76.675,42.55)
  Top Layer w0.12: v1(27.465,2.506) 28.096,1.875 U27.C1@28.775,1.875 ; v1(28.15,4.8) 28.4,4.55 28.955,4.55 29.525,3.98 U27.A2@29.525,3.975 ; 29.6,50.625 29.957,50.625 30.16,50.422 30.16,46.61 29.46,45.91 29.46,44.04 29.96,43.54 29.96,42.785 v1(29.95,42.775) ; 31.25,42.925 31.25,42.28 31.705,41.825 31.705,36.645 31.85,36.5 ; U27.C6@32.525,1.875 32.525,1.425 v1(32.9,1.05) 33.275,1.425 U27.C7@33.275,1.875 ; U27.A6@32.525,3.975 32.68,4.13 32.68,4.705 v1(32.9,4.925) 33.275,4.55 U27.A7@33.275,3.975 ; v1(34.825,1.466) C72.2@34.825,2.025 ; C73.1@35.925,1.45 v1(36.777,1.45)
  Top Layer w0.2: C2.1@1,59.675 1.525,59.675 1.725,59.475 U1.16@2.325,59.475 ; v1(1,65.225) C1.1@1,64.65 1.525,64.65 1.75,64.425 U1.5@2.325,64.425 ; v1(2.7,50.975) 1.375,50.975 1.15,51.2 C27.1@1.15,51.937 1.263,52.05 2.188,52.05 C26.1@2.325,52.188 2.35,52.162 U10.2@3.8,52.162 ; U1.60@2.8,66.25 v1(2.8,66.975) ; v1(3.25,65.625) U1.59@3.25,66.25 ; U1.58@3.7,66.25 v1(3.7,66.975) ; v1(4.15,65.625) U1.57@4.15,66.25 ; C12.2@8.1,51.223 8.577,51.223 v1(8.75,51.05) ; U1.31@8.675,59 9.275,59 9.5,58.775 C3.1@10.05,58.775 v1(10.775,58.775) ; C124.2@10.65,64.975 C123.1@10.65,65.775 ; C122.1@10.65,66.6 C123.1@10.65,65.775 ; v1(11.125,65.775) C123.1@10.65,65.775 ; v1(14,11.525) C66.1@14,10.975 14.06,11.035 CN7.37@15.61,11.035 ; v1(14.235,19.035) CN7.21@15.61,19.035 ; v1(14.235,24.035) CN7.11@15.61,24.035 ; v1(14.235,26.035) CN7.7@15.61,26.035 ; v1(14.235,28.035) CN7.3@15.61,28.035 ; CN7.38@18.16,11.035 19.69,11.035 C67.1@19.75,10.975 v1(19.75,11.525) ; CN7.22@18.16,19.035 v1(19.535,19.035) ; CN7.16@18.16,22.035 v1(19.535,22.035) ; CN7.12@18.16,24.035 v1(19.535,24.035) ; CN7.8@18.16,26.035 v1(19.535,26.035) ; CN7.4@18.16,28.035 v1(19.535,28.035) ; U8.16@18.825,53.125 19.75,53.125 v1(20.75,52.125) ; U8.12@21.25,54.05 21.25,54.894 v1(21.6,55.244) 21.6,55.75 C120.1@21.7,55.85 ; U2.2@22.125,57.8 22.28,57.955 CN1.A1@22.28,59.42 22.33,59.47 CN1.B12@22.33,60.67 ; v2(25.05,1.3) U28.5@25.05,2.175 ; v1(25.15,9.525) C65.2@25.15,10.15 ; C71.2@26.025,4.775 26.6,5.35 C70.1@26.6,5.95 v1(27.225,5.95) ; U25.12@26.187,10.05 25.25,10.05 C65.2@25.15,10.15 ; U25.11@26.187,10.55 25.55,10.55 C65.2@25.15,10.15 ; U17.1@26.255,26.75 26.293,26.713 26.688,26.713 v1(26.725,26.675) 26.744,26.675 26.967,26.451 27.224,26.451 C51.2@27.375,26.3 ; v1(26.5,8.535) 26.5,8.825 26.7,9.025 U25.2@26.7,9.537 ; v1(26.592,15.499) 26.856,15.763 U22.1@26.856,16.222 ; U25.8@27.2,11.063 27.2,11.425 27.4,11.625 C63.2@27.4,12.125 27.525,12.25 27.525,13.225 C61.1@27.65,13.35 v1(28.375,13.35) ; U22.7@27.356,19.072 v1(27.356,20.081) ; U25.6@27.712,10.55 29.285,10.55 29.7,10.135 C69.1@29.7,10.05 30.225,10.575 v1(31,10.575) U26.3@31.763,10.575 ; C4.1@28.204,57.575 R6.1@29.604,57.575 29.679,57.5 v1(30.75,57.5) ; U22.4@28.356,16.222 28.356,15.919 v1(28.725,15.55) ; Q1.2@29.175,63.425 28.95,63.2 R2.1@28.95,61.775 v1(30.05,61.775) ; C64.2@32.575,11.85 v1(32.575,12.475) ; U26.8@33.288,9.575 34.175,9.575 C68.2@34.475,9.875 ; U26.9@33.288,10.075 34.275,10.075 C68.2@34.475,9.875 ; v1(33.675,13.25) C62.1@34.575,13.25 ; U21.6@33.875,17.825 34.575,17.825 34.975,18.225 C59.2@35.075,18.225 ; U21.7@33.875,18.325 34.975,18.325 C59.2@35.075,18.225 ; U16.4@34.55,26.78 34.57,26.8 34.7,26.8 34.875,26.625 v1(36.2,26.625) C125.2@36.2,26 ; C57.2@34.675,20.225 35.075,19.825 v1(35.075,18.825) C59.2@35.075,18.225 ; v1(35.15,9.875) C68.2@34.475,9.875 ; v2(36.6,15.6) C60.1@37.225,15.6 U20.E5@40,15.6 ; v2(37.05,22.375) 37.05,22.675 C50.1@37.175,22.8 ; v1(37.15,39.975) 37.75,39.375 C34.1@37.75,39.275 C36.1@37.75,38.35 ; v2(39.079,31.35) U13.E12@39.329,31.6 ; v2(39.079,33.85) U13.J12@39.329,33.6 ; v1(39.5,45.1) U9.E5@40,45.6 ; v2(39.579,29.85) U13.B11@39.829,30.1 ; v2(39.579,35.35) U13.M11@39.829,35.1 ; v2(40.079,35.35) U13.M10@40.329,35.1 ; C35.1@40.375,39.275 40.675,39.575 v1(40.675,40.625) ; v2(41.079,29.85) U13.B8@41.329,30.1 ; v2(41.45,21.86) C55.1@41.45,21.35 41.45,20.15 U20.C1@42,19.6 ; v1(41.5,50.1) U9.C1@42,49.6 ; U13.M7@41.829,35.1 v2(42.079,35.35) ; U20.B3@43,17.6 v1(43.5,17.1) ; U9.B3@43,47.6 v1(43.5,48.1) ; U13.B4@43.329,30.1 v2(43.579,29.85) ; v1(43.475,24.95) C48.1@43.475,25.5 C49.1@44.425,25.5 ; U13.M3@43.829,35.1 v2(44.079,35.35) ; v1(43.85,12.75) 43.85,12.438 U24.2@44.163,12.125 ; v2(44.079,32.35) U13.F2@44.329,32.1 ; U13.B2@44.329,30.1 v2(44.579,29.85) ; U13.H2@44.329,33.1 v2(44.579,33.35) ; v1(47.275,11.1) R40.1@47.275,12.125 ; C42.1@47.5,32.925 47.6,32.825 v2(47.93,32.825) ; C43.1@49.475,32.025 v2(50.15,32.025) ; v1(51.8,51.65) C8.1@51.8,53 ; v1(52.325,19.325) U19.6@52.325,20.175 ; v2(52.425,35.85) C41.2@52.425,35.075 52.425,34.075 X1.2@52.5,34 ; v1(52.925,11.15) B2.4@53.9,11.15 ; C45.2@53.1,29.875 C46.2@53.1,29.15 v2(53.9,29.15) ; U3.11@53.225,55.9 v1(53.225,56.65) ; B2.3@53.9,2.25 v1(53.9,4.375) ; v1(56.175,5.825) LD5.2@57.15,5.825 ; v1(56.425,17.25) C58.1@56.425,18.05 ; C54.1@56.55,23.45 57.2,23.45 v1(58.25,22.4) ; C56.2@56.75,21.125 56.775,21.15 v1(58.225,21.15) ; v1(57.875,50.375) Q3.2@57.875,51.175 ; U29.2@58.875,3.65 59.025,3.8 v1(59.025,4.425) ; CN10.5@61.46,19.26 v1(61.46,20.365) ; U11.2@61.575,35.675 v1(61.575,37.3) ; CN10.3@64,19.26 v1(64,20.365) ; CN9.7@64,29.857 v1(64,31.795) ; CN9.5@65.27,29.857 65.275,29.862 v1(65.275,31.775) ; v2(66.525,34.7) U12.2@66.525,35.675 ; v1(71.625,37.575) C37.1@71.625,36.575 71.775,36.425 71.775,35.5 C40.1@71.875,35.4 71.875,33.675 72.228,33.322 M1.17@73.28,33.322 ; LD3.1@90.175,37.775 v1(91.875,37.775) ; U14.3@92.45,32.625 v1(92.45,33.6) ; C52.1@92.775,23.95 92.95,24.125 94.3,24.125 U18.2@94.35,24.175
  Signal Layer 1 w0.1: 37.375,27.646 v2(39.579,29.85) ; 38.525,33.975 38.65,33.85 v2(39.079,33.85) ; 40.925,28.25 41.079,28.404 v2(41.079,29.85) ; v2(42.079,35.35) 42.11,35.381 42.11,37.636 42.815,38.341 42.815,39 ; v2(44.079,35.35) 44.35,35.621 44.35,36.85
  Signal Layer 1 w0.12: 36.85,25.075 36.645,25.28 36.645,25.795 37.375,26.525 37.375,27.646 ; 42.57,42.525 42.69,42.405 42.793,42.405 43.095,42.103 43.095,40.47 42.815,40.19 42.815,39 ; v2(47.93,32.825) 47.93,32.611 48.591,31.95 49.15,31.95 49.175,31.975
  Bottom Layer w0.1: 36.175,31.225 36.5,31.225 36.575,31.3 37.65,31.3 37.725,31.375 ; C98.1@38.025,34.25 C97.1@38.025,35.15 C96.1@38.025,36.1 ; v1(64.25,39.75) 64.25,40.675 C86.1@64.375,40.8 C84.1@64.375,42.175 ; C83.1@64.375,45.075 64.4,45.05 v1(64.4,43.825) R51.1@64.95,43.825 ; R56.1@73.235,38.55 73.235,38.629 73.346,38.74 73.615,38.74 73.615,38.55 R55.2@74.475,38.55 ; C77.2@78.5,48.725 v1(79.2,48.725)
  Bottom Layer w0.12: C90.1@38.65,39.25 C89.1@39.6,39.25 C88.1@40.525,39.25 ; v1(40.675,40.625) 40.675,39.4 C88.1@40.525,39.25 ; C93.1@40.85,37.475 40.95,37.575 40.95,38.825 C88.1@40.525,39.25 ; v1(68.875,45.15) U32.H12@69.2,45.475 ; v1(68.875,46.45) U32.G12@69.2,46.125 ; v1(68.875,47.1) U32.F12@69.2,46.775 ; U32.K10@70.5,44.175 v1(70.825,44.5) ; U32.F10@70.5,46.775 v1(70.825,46.45) ; v1(70.825,42.55) U32.M9@71.15,42.875 ; v1(70.825,48.4) U32.D9@71.15,48.075 ; v1(71.475,42.55) U32.M8@71.8,42.875 ; v1(71.475,48.4) U32.D8@71.8,48.075 ; U32.D7@72.45,48.075 v1(72.775,48.4) ; U32.K6@73.1,44.175 v1(72.775,44.5) ; U32.F6@73.1,46.775 v1(72.775,46.45) ; U32.D6@73.1,48.075 v1(73.425,48.4) ; U32.D5@73.75,48.075 v1(74.075,48.4) ; U32.G2@75.7,46.125 v1(76.025,46.45) ; U32.F2@75.7,46.775 v1(76.025,47.1) ; U32.N1@76.35,42.225 v1(76.675,41.9) ; U32.M1@76.35,42.875 v1(76.675,42.55) ; C87.2@78.5,40.525 79.05,40.525 79.175,40.65 v1(79.175,41) 79.175,41.325 79.025,41.475 C85.2@78.5,41.475 ; v1(70.825,44.5) U32.J10@70.5,44.825 v1(70.825,45.15) ; v1(70.825,44.5) U32.J9@71.15,44.825 ; v1(70.825,44.5) U32.K9@71.15,44.175 v1(71.475,44.5) ; v1(70.825,45.15) U32.J9@71.15,44.825 ; v1(70.825,45.15) U32.H10@70.5,45.475 v1(70.825,45.8) ; v1(70.825,45.15) U32.H9@71.15,45.475 ; v1(70.825,45.8) U32.G10@70.5,46.125 v1(70.825,46.45) ; v1(70.825,45.8) U32.G9@71.15,46.125 ; v1(70.825,45.8) U32.H9@71.15,45.475 ; v1(70.825,46.45) U32.G9@71.15,46.125 ; v1(70.825,46.45) U32.F9@71.15,46.775 v1(71.475,46.45) ; U32.J9@71.15,44.825 v1(71.475,44.5) ; U32.J9@71.15,44.825 v1(71.475,45.15) ; U32.H9@71.15,45.475 v1(71.475,45.8) ; U32.H9@71.15,45.475 v1(71.475,45.15) ; U32.G9@71.15,46.125 v1(71.475,45.8) ; U32.G9@71.15,46.125 v1(71.475,46.45) ; v1(71.475,44.5) U32.K8@71.8,44.175 v1(72.125,44.5) ; v1(71.475,44.5) U32.J8@71.8,44.825 ; v1(71.475,45.15) U32.H8@71.8,45.475 ; v1(71.475,45.15) U32.J8@71.8,44.825 ; v1(71.475,45.8) U32.H8@71.8,45.475 ; v1(71.475,45.8) U32.G8@71.8,46.125 ; v1(71.475,46.45) U32.F8@71.8,46.775 v1(72.125,46.45) ; v1(71.475,46.45) U32.G8@71.8,46.125 ; U32.J8@71.8,44.825 v1(72.125,44.5) ; U32.J8@71.8,44.825 v1(72.125,45.15) ; U32.H8@71.8,45.475 v1(72.125,45.8) ; U32.H8@71.8,45.475 v1(72.125,45.15) ; U32.G8@71.8,46.125 v1(72.125,45.8) ; U32.G8@71.8,46.125 v1(72.125,46.45) ; v1(72.125,44.5) U32.J7@72.45,44.825 ; v1(72.125,44.5) U32.K7@72.45,44.175 v1(72.775,44.5) ; v1(72.125,45.15) U32.J7@72.45,44.825 ; v1(72.125,45.15) U32.H7@72.45,45.475 ; v1(72.125,45.8) U32.G7@72.45,46.125 ; v1(72.125,45.8) U32.H7@72.45,45.475 ; v1(72.125,46.45) U32.G7@72.45,46.125 ; v1(72.125,46.45) U32.F7@72.45,46.775 v1(72.775,46.45) ; U32.J7@72.45,44.825 v1(72.775,44.5) ; U32.J7@72.45,44.825 v1(72.775,45.15) ; U32.H7@72.45,45.475 v1(72.775,45.15) ; U32.H7@72.45,45.475 v1(72.775,45.8) ; U32.G7@72.45,46.125 v1(72.775,45.8) ; U32.G7@72.45,46.125 v1(72.775,46.45) ; v1(72.775,44.5) U32.J6@73.1,44.825 v1(72.775,45.15) ; v1(72.775,45.15) U32.H6@73.1,45.475 v1(72.775,45.8) ; v1(72.775,45.8) U32.G6@73.1,46.125 v1(72.775,46.45)
  Bottom Layer w0.2: CN12.SH1@1.45,50.975 v1(2.7,50.975) ; CN12.EXP1@1.45,53.563 1.787,53.9 v1(2.775,53.9) ; CN12.EXP2@1.45,55.888 v1(2.775,55.888) 2.913,56.025 CN12.5@4.3,56.025 ; CN12.SH2@1.45,58.475 1.45,58.3 2.625,57.125 v1(3.175,57.125) ; R46.1@5.875,56.86 v1(5.875,57.575) ; v1(5.9,50.15) 5.94,50.15 U31.2@6.575,50.785 ; v1(7.575,10.975) C118.1@7.575,11.925 ; v1(7.575,20.4) R61.1@7.575,21.35 ; C75.1@7.95,50.96 8.04,51.05 v1(8.75,51.05) ; U30.3@8,53.675 8.175,53.675 8.45,53.4 v1(8.45,52.725) ; v1(9.7,49.525) 9.7,49.225 9.85,49.075 C17.1@10.35,49.075 ; C115.1@11.825,16.9 v1(12.575,16.15) ; v1(26.825,23.075) 27.06,23.075 27.935,23.95 27.96,23.925 CN15.2@28.335,24.3 ; v1(35.675,16.5) 36.3,16.5 36.958,17.158 U37.4@37.434,17.158 ; v1(37.15,39.975) 37.15,39.45 C91.1@37.35,39.25 ; v1(38.6,24.95) C111.1@38.6,25.5 ; C82.1@38.85,45.15 38.9,45.1 v1(39.5,45.1) ; v1(40.85,12.7) 40.85,12.45 C119.1@41.275,12.025 ; C76.1@41.45,50.775 41.5,50.725 v1(41.5,50.1) ; v1(42.025,24.95) C109.1@42.025,25.5 ; v1(42.66,3.81) CN17.7@42.66,5.596 ; v1(43.5,17.1) 44.1,17.1 C114.1@44.15,17.05 ; v1(43.5,48.1) 44.1,48.1 C78.1@44.15,48.05 ; C108.1@44.425,26.125 44.125,25.825 43.85,25.825 43.475,25.45 v1(43.475,24.95) 44.746,24.95 45.296,25.5 C107.1@45.35,25.5 ; v1(44.838,37.313) C92.1@44.838,38 ; CN17.6@45.2,9.024 v1(46.351,9.024) ; C103.1@47.125,28.9 47.7,29.475 C102.2@47.7,30.275 47.7,30.3 47.45,30.55 v1(47.45,31) 47.45,31.025 47.065,31.41 47.065,32.69 C99.1@47.125,32.75 ; v1(58,41.375) U34.2@58,41.988 ; v1(58,46.425) U33.2@58,47.088 ; v1(58.8,40.15) C6.2@58.799,39.527 58.852,39.58 59.427,39.58 59.669,39.822 59.669,39.847 59.824,40.002 C127.2@59.849,40.002 ; v1(60.4,52.025) C74.2@60.975,52.025 ; v1(62.25,47.75) 62.25,47.025 62.5,46.775 C81.2@63.225,46.775 ; R58.1@63.075,30.975 63.675,30.975 64,31.3 v1(64,31.795) ; C126.2@63.75,67.65 63.775,67.65 63.93,67.805 63.93,67.83 64.172,68.072 64.747,68.072 64.8,68.125 v1(65.519,68.125) ; v1(73.4,37.6) R56.1@73.4,38.55 ; C105.1@79.575,27 v1(79.575,27.575) ; v1(80.275,44.85) X3.2@81.075,44.85 ; C79.2@80.5,47.525 C79.2@80.525,47.525 v1(81.25,47.525) 81.99,47.525 C80.2@81.995,47.52 ; U35.2@80.525,22.5 v1(80.525,23.6) ; v1(80.9,38.825) R64.2@80.9,39.625 ; R65.2@82.575,39.65 v1(83.5,39.65) v1@83.525,39.65
  other v1: 47.925,0.8 51.875,0.825 43.45,1.125 92.025,1.275 13.6,1.675 21.375,1.825 98.425,1.925 71.375,3.525 10.4,7.075 19.15,7.825 87.875,9.25 47.675,9.65 59.625,9.675 60.775,9.925 4.525,10.025 64.875,10.225 12.6,11.4 30.775,12.475 65.575,14.35 58.375,14.575 5.725,14.975 52.975,15.175 85.2,15.175 98.95,15.275 56.275,15.725 30.825,15.75 70.175,15.75 52.825,16.75 22.2,17.875 80.05,20.35 2.075,20.8 85.925,21.6 60.225,22.225 70.4,22.775 92.775,23.175 99.25,23.7 2.05,26.475 71.275,27.45 86.2,27.6 96.8,27.975 90.6,30.125 74.944,30.231 5.025,31.5 33.225,31.65 71.7,32.4 12.6,35.025 83.125,35.25 87.175,35.4 56.85,36.35 34.1,36.85 52.05,36.85 19.125,39.6 7.325,39.875 61.775,40.15 93.6,40.15 3.275,40.825 4,42.95 13.05,42.975 60.35,43.25 85.225,43.475 95.925,43.725 13.3,45.675 4.775,45.9 4.025,48.25 98.1,48.5 85.525,49.65 13.35,50 19.725,51.05 21.726,51.074 34,51.375 93.3,51.55 41.25,52.45 48.75,53.075 64.375,53.15 19.7,53.175 21.75,53.175 15.85,54.025 26.4,55.825 17.725,57.1 10.85,57.275 11.825,57.275 12.8,57.275 13.775,57.275 61.6,57.55 16.625,58.225 11.825,58.25 12.8,58.25 13.775,58.25 90.15,58.7 11.825,59.225 12.8,59.225 13.775,59.225 92.325,59.225 65.725,59.3 4.525,59.65 11.825,60.2 13.775,60.2 98.25,60.625 9.875,61.175 10.85,61.175 11.825,61.175 13.775,61.175 66.1,61.375 9.875,62.15 10.85,62.15 11.825,62.15 12.8,62.15 13.775,62.15 60.675,62.175 65.55,63.025 9.875,63.125 10.85,63.125 11.825,63.125 12.8,63.125 13.775,63.125 54.425,63.925 9.875,64.1 10.85,64.1 11.825,64.1 12.8,64.1 13.775,64.1 11.825,65.075 12.8,65.075 13.775,65.075 11.825,66.05 12.8,66.05 19.375,66.4 25.25,66.55 13.775,67.025 60,67.575 9.875,68 10.85,68 11.825,68 12.8,68 13.775,68 98.4,68.075 92.25,68.8 9.875,68.975 10.85,68.975 11.825,68.975 12.8,68.975 13.775,68.975
  other v2: 50.873,32 29.1,55.05 1,59.725 5.95,63.975
GNDDetect: CN9.11 R58.2 U32.K13 | length 23.9
  Top Layer w0.12: CN9.11@61.46,29.857 v1(61.46,31.86)
  Signal Layer 2 w0.1: 68.225,38.25 v1(68.225,43.85)
  Signal Layer 2 w0.12: 68.225,38.25 68.225,36.15 68.975,35.4 v1(68.975,32.425)
  Bottom Layer w0.12: R58.2@62.175,30.975 61.6,30.975 61.46,31.115 v1(61.46,31.86) 61.475,31.875 62.602,31.875 62.607,31.87 63.12,31.87 64.17,32.92 67.205,32.92 67.7,32.425 v1(68.975,32.425) ; v1(68.225,43.85) U32.K13@68.55,44.175
I2C1_SCL: CN3.7 CN13.10 Q5.3 R30.1 R59.2 SB12.1 U13.E5 | length 151.1
  Top Layer w0.08: v3(42.829,31.6) v2(43.079,31.35)
  Top Layer w0.15: Q5.3@8.8,25.275 9.2,24.875 R30.1@11.375,24.875 11.4,24.9 v1(11.4,25.7)
  Signal Layer 1 w0.08: v3(42.829,31.6) v2(43.079,31.35)
  Signal Layer 2 w0.08: v3(42.829,31.6) 42.83,26.645 43.55,25.925
  Signal Layer 2 w0.1: v1(67.044,52.269) 67.044,49.3 67.82,48.524 67.82,38.25
  Signal Layer 2 w0.12: v1(11.4,25.7) 11.4,22.598 11.02,22.218 11.02,12.755 11.325,12.45 21.175,12.45 v1(22.35,13.625) ; v1(42.025,10.595) 42.025,16.68 43.66,18.315 43.66,19.424 44.955,20.719 44.95,20.724 v1(44.95,23.7) 44.95,24.515 44.955,24.52 43.55,25.925 ; 67.82,38.25 67.82,36.181 67.595,35.956 67.595,35.507 67.83,35.272 67.83,31.895 v1(69.2,30.525) ; v1(81.985,56.879) 83.525,58.419 CN3.7@83.525,61.325
  Bottom Layer w0.1: v1(67.044,52.269) CN13.10@67.044,53.2
  Bottom Layer w0.12: SB12.1@22.35,12.35 v1(22.35,13.625) 22.95,14.225 34.475,14.225 37.855,10.845 41.775,10.845 v1(42.025,10.595) ; v1(44.95,23.7) 46.55,23.7 47.775,24.925 R59.2@47.975,24.925 53.644,24.925 54.34,25.621 54.34,28.286 54.784,28.73 68.105,28.73 69.2,29.825 v1(69.2,30.525) ; CN13.10@67.044,53.2 67.044,55.944 67.979,56.879 v1(81.985,56.879)
I2C1_SDA: CN3.10 CN13.9 Q4.3 R26.1 R60.2 SB11.1 U13.D5 | length 168.8
  Top Layer w0.08: U13.D5@42.829,31.1 v2(43.079,30.85)
  Top Layer w0.15: Q4.3@8.775,32 9.175,31.6 11.35,31.6 11.1,31.85 v1(11.1,32.4)
  Signal Layer 1 w0.08: v2(43.079,30.85) 43.329,30.6 43.329,30.1 43.329,28.95 43.3,28.921 43.3,26.953 43.3,26.175 43.55,25.925
  Signal Layer 1 w0.12: 43.55,25.925 43.6,25.925 44.675,24.85 v1(45.275,24.85)
  Signal Layer 2 w0.1: 66.679,53.2 66.679,49.396 67.58,48.495 67.58,38.25
  Signal Layer 2 w0.12: v1@11.095,32.405 v1(11.1,32.4) 11.1,26.4 10.995,26.295 10.995,22.845 10.675,22.525 10.675,12.6 11.15,12.125 22.425,12.125 v1(23.85,13.55) ; v1(42.4,10) 42.4,10.397 42.43,10.427 42.43,10.763 42.4,10.793 42.4,16.716 43.9,18.216 43.9,19.325 45.36,20.785 45.36,23.89 45.275,23.975 v1(45.275,24.85) ; v1(64.504,55.604) 66.679,53.429 66.679,53.2 ; 67.58,38.25 67.58,36.28 67.355,36.055 67.355,35.235 67.59,35 67.59,31.11 v1(68.725,29.975) ; v1(89.5,57.284) 89.5,61.3 CN3.10@89.525,61.325
  Bottom Layer w0.12: SB11.1@23.85,12.275 v1(23.85,13.55) 24.285,13.985 34.376,13.985 37.756,10.605 41.145,10.605 41.75,10 v1(42.4,10) ; v1(45.275,24.85) 46.45,24.85 R60.2@46.5,24.9 ; R60.2@46.525,24.925 46.725,24.925 47.35,25.55 48.725,25.55 49.105,25.17 53.55,25.17 54.1,25.72 54.1,28.386 54.684,28.97 67.72,28.97 v1(68.725,29.975) ; v1(64.504,55.604) 64.504,57.284 v1(89.5,57.284)
I2C2_SCL: CN2.7 R28.2 U8.18 U13.E10 U16.7 U17.5 U21.13 U22.6 U25.1 U26.2 U27.C4 U28.2 | length 160.6
  Top Layer w0.08: 34.7,30.475 v2(35.725,30.475) ; v2(40.079,31.35) U13.E10@40.329,31.6
  Top Layer w0.1: U16.7@29.8,24.24 v1(32.2,24.24) ; R28.2@31.375,29.325 v1(32.2,29.325) 33.35,30.475 34.7,30.475
  Top Layer w0.12: v1(17.1,52.125) U8.18@18.825,52.125 ; v1(23.725,4.6) 24.05,4.275 U28.2@24.05,3.675 ; U17.5@25.605,25 25.605,24.442 25.808,24.24 U16.7@29.8,24.24 ; U25.1@26.2,9.537 26.2,9.05 25.95,8.8 25.95,8.372 26.353,7.968 v1(30.15,7.968) ; U22.6@27.856,19.072 27.856,19.731 28.05,19.925 v1(30.15,19.925) 30.15,18.447 30.772,17.825 U21.13@31.875,17.825 ; v1(30.15,11.523) 31.852,11.523 32.275,11.1 U26.2@32.275,10.838 ; v1(31.025,0.95) U27.C4@31.025,1.875
  Signal Layer 1 w0.08: v2(35.725,30.475) 36,30.2 37.45,30.2 38.85,31.6 39.375,31.6 39.829,31.6 v2(40.079,31.35)
  Signal Layer 2 w0.1: v1(32.2,24.24) v1(32.2,29.325) ; 46.05,64.1 46.05,62.325 CN2.7@47.05,61.325
  Signal Layer 2 w0.12: v1(23.34,0.95) 22.994,0.95 22.45,1.494 22.45,4.021 23.029,4.6 v1(23.725,4.6) ; v1(31.025,0.95) 31.025,4.325 30.15,5.2 v1(30.15,7.968) v1(30.15,11.523) v1(30.15,19.925) 30.15,20.553 32.2,22.603 v1(32.2,24.24) ; v1(32.2,29.325) 32.21,29.335 32.21,34.14 31.6,34.75 31.6,38.36 31.31,38.65 31.31,41.22 31.325,41.235 v1(31.325,44.475) 31.337,44.487 31.337,44.796 31.45,44.908 31.45,50.689 30.365,51.774 30.365,53.751 32.325,55.711 32.325,67.75 v1(32.7,68.125) ; 46.05,64.1 v1(46.05,68.15)
  Bottom Layer w0.12: v1(17.1,52.125) 17.1,46.05 18.44,44.71 30.445,44.71 30.68,44.475 v1(31.325,44.475) ; v1(23.34,0.95) v1(31.025,0.95) ; v1(32.7,68.125) v1@46.05,68.125
I2C2_SDA: CN2.10 R27.2 U8.17 U13.F9 U16.5 U17.2 U21.14 U22.5 U25.4 U26.4 U27.C3 U28.4 | length 155.9
  Top Layer w0.08: 34.7,31.525 v2(35.975,31.525) ; v2(40.579,31.85) v3(40.829,32.1)
  Top Layer w0.1: U16.5@29.8,26.78 v1(31.805,26.78) ; 32.8,32.125 33.45,32.125 34.05,31.525 34.7,31.525
  Top Layer w0.12: v1(17.725,53.05) 18.15,52.625 U8.17@18.825,52.625 ; v1(24.05,1.4) U28.4@24.05,2.175 ; U17.2@25.605,26.75 25.605,26.875 25.695,26.965 25.715,26.965 26.2,27.45 27.6,27.45 28.27,26.78 U16.5@29.8,26.78 ; U25.4@27.7,9.537 28.413,9.537 28.7,9.25 v1(29.725,9.25) 30.55,10.075 U26.4@31.763,10.075 ; U22.5@28.356,19.072 v1(29.722,19.072) 29.722,17.778 30.175,17.325 U21.14@31.875,17.325 ; v1(30.275,1.375) U27.C3@30.275,1.875 ; R27.2@31.375,30.75 31.375,30.95 31.805,31.38 v1(31.805,32.125) 32.8,32.125
  Signal Layer 1 w0.08: v2(35.975,31.525) 36.175,31.325 37.425,31.325 v3(37.525,31.425) ; v2(40.579,31.85) v3(40.829,32.1)
  Signal Layer 2 w0.08: v3(37.525,31.425) 38.2,32.1 v3(40.829,32.1)
  Signal Layer 2 w0.1: v1(31.805,26.78) v1(31.805,32.125) ; 52.05,64.375 52.05,62.325 CN2.10@53.05,61.325
  Signal Layer 2 w0.12: v1(30.275,1.375) 30.275,4.275 29.722,4.828 29.722,8.372 29.725,8.375 v1(29.725,9.25) 29.725,20.55 31.795,22.62 31.795,26.77 v1(31.805,26.78) ; v1(31.805,32.125) 31.805,34.206 31.3,34.711 31.3,38.321 31.07,38.551 31.07,41.22 30.92,41.37 30.92,44.745 31.025,44.85 v1(31.025,45.2) 31.071,45.246 31.071,45.486 31.21,45.625 31.21,50.59 30.125,51.675 30.125,53.865 32.085,55.825 v1(32.085,68.555) ; 52.05,64.375 v1(52.05,68.58)
  Bottom Layer w0.12: v1(17.725,53.05) 17.725,51.813 17.492,51.579 17.492,46.083 18.625,44.95 18.67,44.995 21.968,44.995 22.173,45.2 v1(31.025,45.2) ; v1(24.05,1.4) 30.25,1.4 v1(30.275,1.375) ; v1(32.085,68.555) 32.11,68.58 v1(52.05,68.58)
I2C_SCL_CAMERA: CN7.13 Q5.2 R30.2 R34.1 | length 7.8
  Top Layer w0.15: R34.1@9.25,21.675 9.425,21.85 9.425,22.75 Q5.2@9.75,23.075 10.15,23.475 R30.2@11.375,23.475 13.625,23.475 14.065,23.035 CN7.13@15.61,23.035
I2C_SDA_CAMERA: CN7.14 Q4.2 R26.2 R29.1 | length 20.1
  Top Layer w0.12: CN7.14@18.16,23.035 v1(19.535,23.035)
  Top Layer w0.15: R29.1@9.225,28.4 9.375,28.55 9.375,29.45 Q4.2@9.725,29.8 10.125,30.2 R26.2@11.375,30.2 11.65,30.2 12.03,30.58 v1(18.62,30.58)
  Signal Layer 2 w0.15: v1(18.62,30.58) 18.62,23.95 v1(19.535,23.035)
LED_GREEN: R42.2 U13.F8 | length 27.5
  Top Layer w0.08: v2(41.079,31.85) v3(41.329,32.1)
  Top Layer w0.12: R42.2@37.35,7.75 v1(37.35,8.5)
  Signal Layer 1 w0.08: v2(41.079,31.85) v3(41.329,32.1)
  Signal Layer 2 w0.08: 39.02,25.925 39.02,29.395 41.079,31.454 41.079,31.85 v3(41.329,32.1)
  Signal Layer 2 w0.12: v1(37.35,8.5) 39,10.15 39,20.981 38,21.981 38,23.325 39.02,24.345 39.02,25.925
LED_RED: R41.2 U13.E11 | length 28.2
  Top Layer w0.08: v2(39.579,31.35) U13.E11@39.829,31.6
  Top Layer w0.12: R41.2@35.85,7.75 v1(35.85,8.475)
  Signal Layer 1 w0.08: v1(35.875,27.325) 35.875,29.125 36.275,29.525 37.754,29.525 v2(39.579,31.35)
  Signal Layer 2 w0.1: 35.575,25.925 35.575,27.025 v1(35.875,27.325)
  Signal Layer 2 w0.12: 35.575,25.925 35.575,23.8 36.375,23 36.375,18.05 37.175,17.25 37.175,8.9 36.75,8.475 v1(35.85,8.475)
LED_STLK: R16.2 R17.2 U32.D15 | length 27.9
  Top Layer w0.1: v1(66.925,48.4) 67.55,49.025 69.45,49.025 70.725,47.75 74.125,47.75 74.825,48.45 78.675,48.45 79.05,48.075
  Top Layer w0.12: 79.05,48.075 81.45,48.075 84.82,44.705 84.82,39.355 R16.2@84.9,39.275 R17.2@84.9,37.775
  Bottom Layer w0.12: v1(66.925,48.4) U32.D15@67.25,48.075
Mems.INT_IIS2MDC: U13.K11 U25.7 | length 56.1
  Top Layer w0.1: v2(39.579,34.35) U13.K11@39.829,34.1
  Top Layer w0.12: U25.7@27.7,11.063 v1(28.35,11.063) ; v1(32.275,45.712) 32.275,45.396 35.945,41.726 35.945,39.43 v2(36.3,39.075)
  Signal Layer 1 w0.08: v2@36.3,39 36.3,37.425 39.295,34.43 39.499,34.43 v2(39.579,34.35)
  Signal Layer 1 w0.12: v2@36.3,39 v2(36.3,39.075)
  Signal Layer 2 w0.12: v1(28.35,11.063) 28.78,11.492 28.78,14.345 28.32,14.805 28.32,20.67 30.025,22.375 30.025,23.15 30.72,23.845 30.72,33.93 30.025,34.625 30.025,35.9 30.025,37.425 29.85,37.6 29.85,41.975 29.34,42.485 29.34,46.365 v1(29.575,46.6)
  Bottom Layer w0.12: v1(29.575,46.6) 31.387,46.6 v1(32.275,45.712)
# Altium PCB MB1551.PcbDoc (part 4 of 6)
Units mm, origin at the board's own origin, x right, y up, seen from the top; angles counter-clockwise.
Board outline 100 x 70 mm, 6 copper layers (Top Layer, Signal Layer 1, Signal Layer 2, Signal Layer 3, Signal Layer 4, Bottom Layer), stack 1.49 mm thick; 325 components, 276 nets, 1540 pads, 1100 vias.

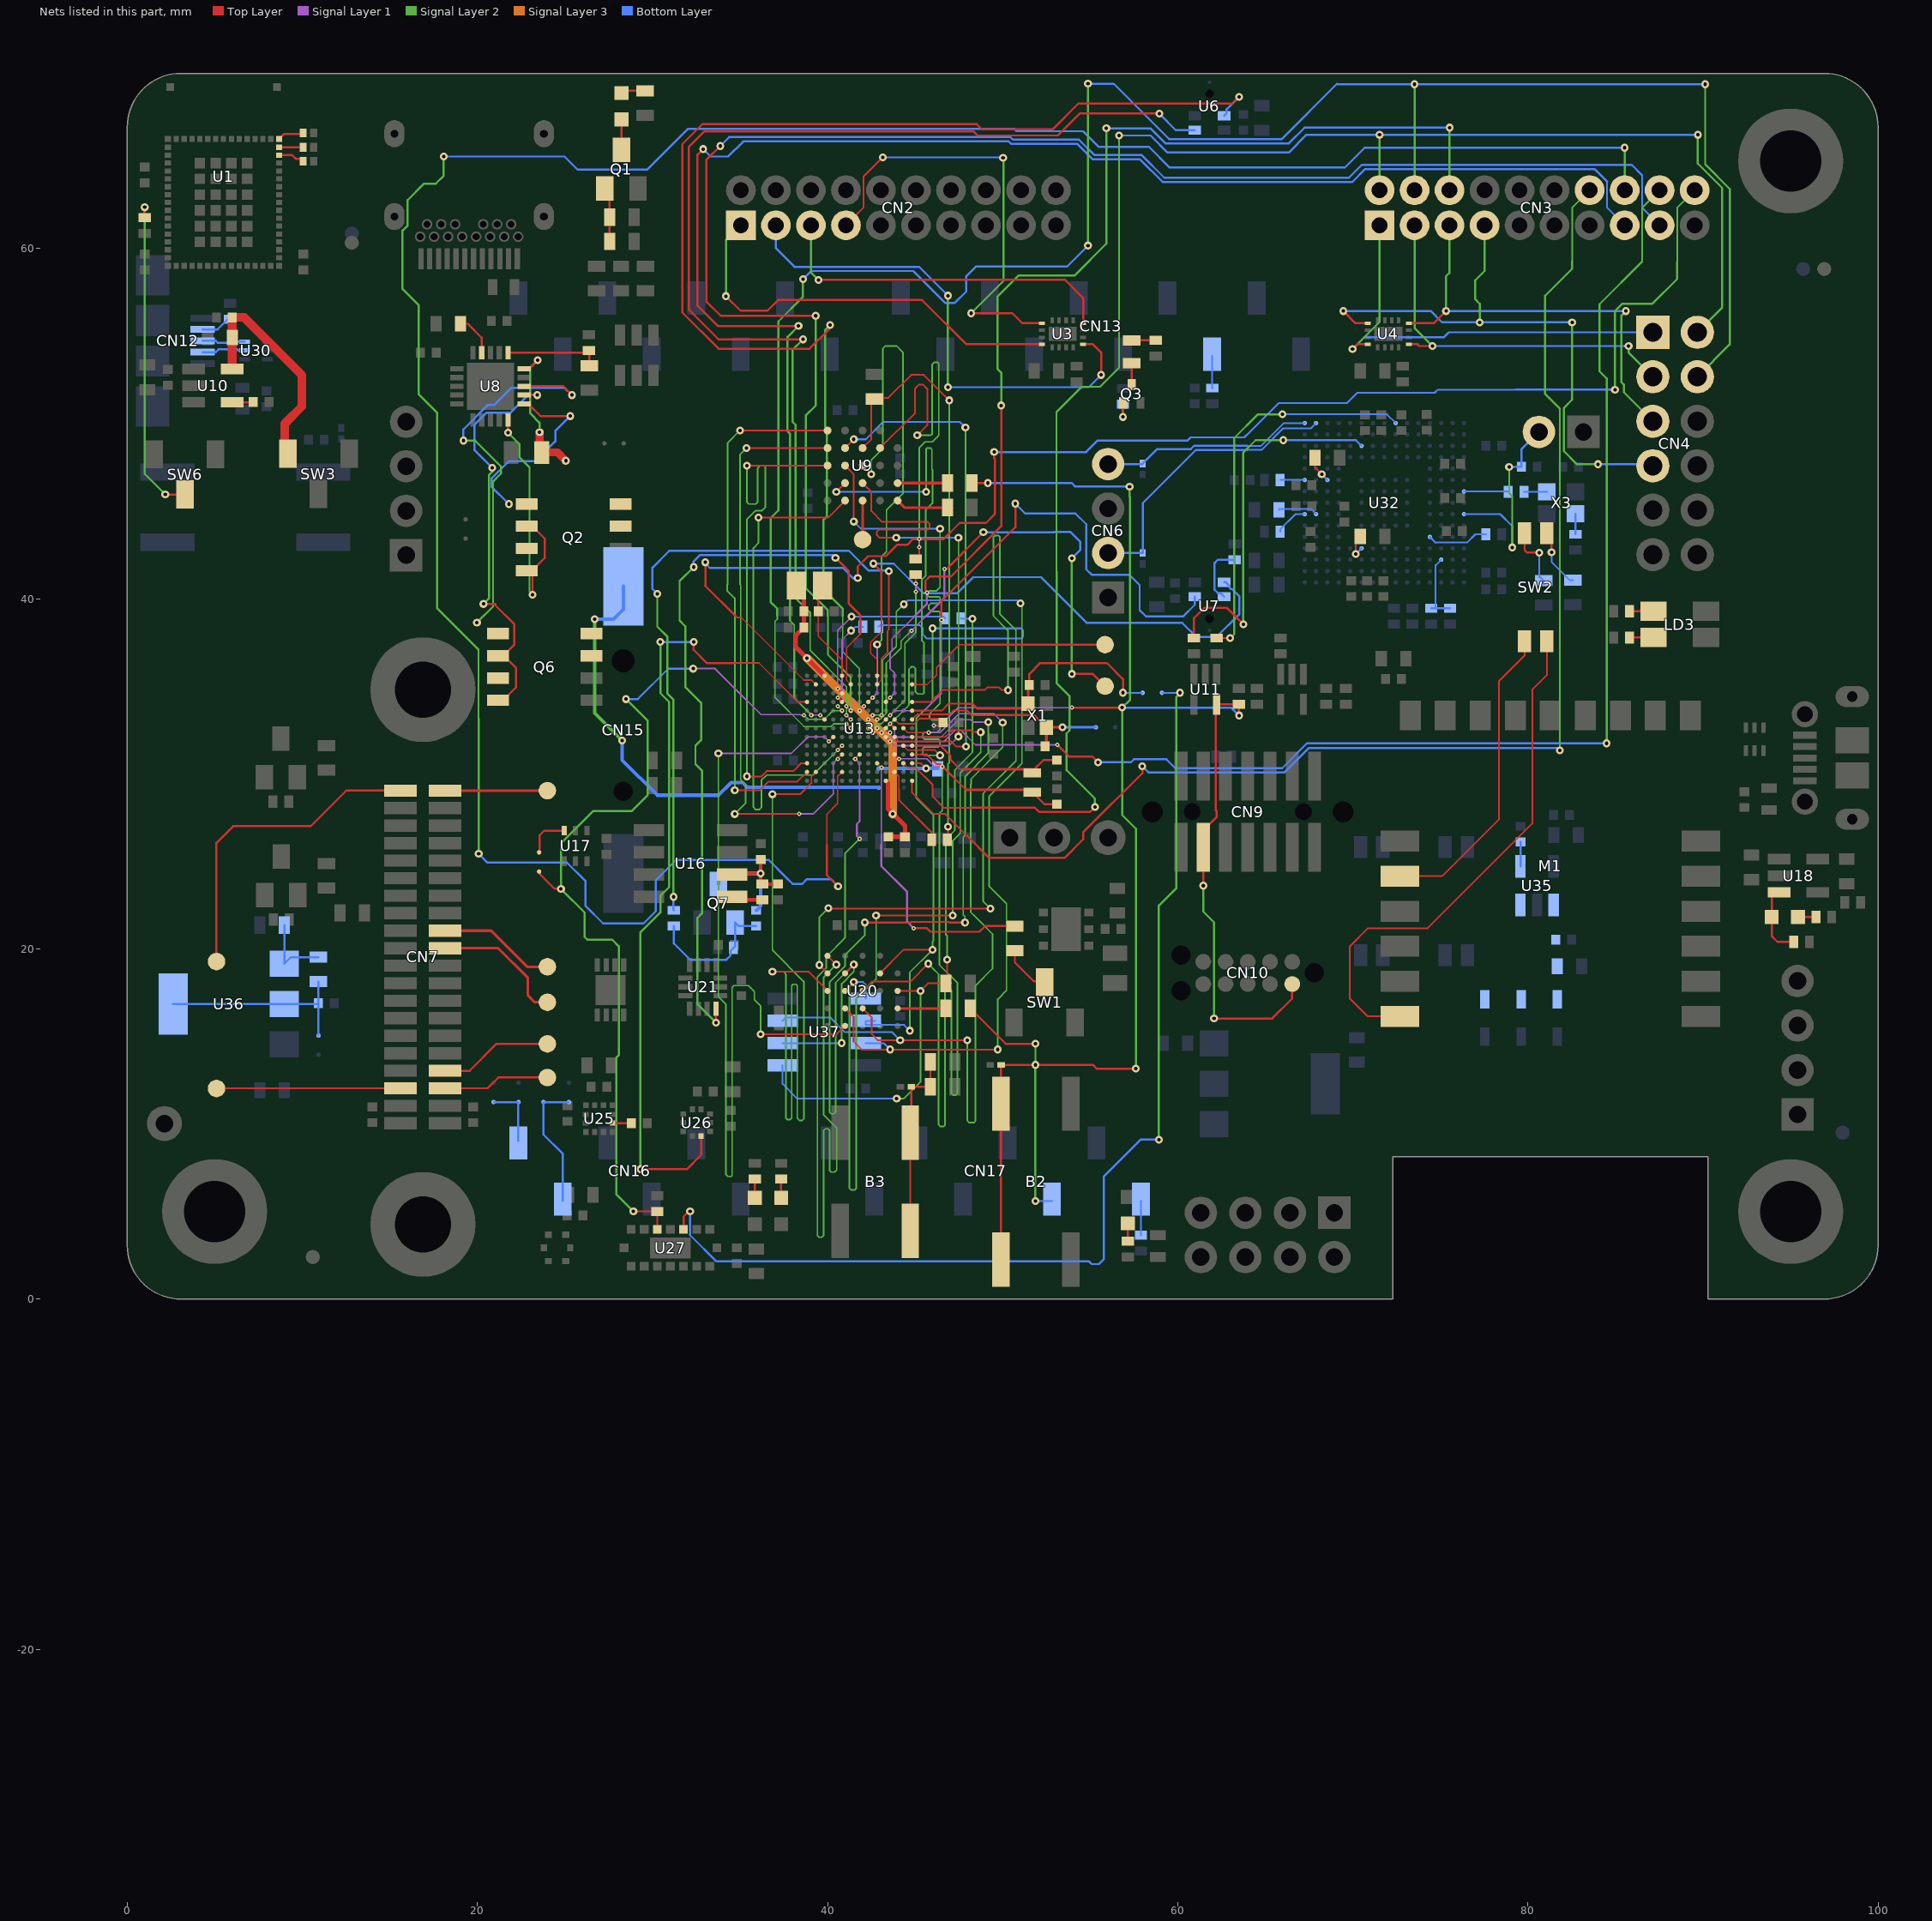
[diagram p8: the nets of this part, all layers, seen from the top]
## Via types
v1: diameter 0.45, hole 0.2, Top Layer to Bottom Layer, tented both sides, 922 vias
v2: diameter 0.25, hole 0.1, Top Layer to Signal Layer 1, tented top, 142 vias
v3: diameter 0.25, hole 0.1, Signal Layer 1 to Signal Layer 2, 36 vias

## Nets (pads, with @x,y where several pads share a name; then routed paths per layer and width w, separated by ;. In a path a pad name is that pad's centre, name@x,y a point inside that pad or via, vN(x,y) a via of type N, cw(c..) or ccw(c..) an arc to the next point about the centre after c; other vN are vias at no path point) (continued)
Mems.INT_LPS22HH: U13.K13 U26.7 | length 45.9
  Top Layer w0.08: 36.075,36.325 38.3,34.1 U13.K13@38.829,34.1
  Top Layer w0.1: 34.7,36.325 36.075,36.325
  Top Layer w0.12: v1(29.317,7.417) 31.967,7.417 32.775,8.225 U26.7@32.775,9.313 ; v1(32.35,37.525) 32.35,37.075 33.1,36.325 34.7,36.325
  Signal Layer 2 w0.12: v1(29.317,7.417) 29.317,20.942 30.45,22.075 30.45,23.025 30.96,23.535 30.96,34.09 30.45,34.6 v1(30.45,37.525)
  Bottom Layer w0.12: v1(30.45,37.525) v1(32.35,37.525)
Mems.ISM330DLC_INT1: U13.M8 U21.4 | length 45.4
  Top Layer w0.08: U13.M8@41.329,35.1 41.079,35.35 41.079,37.179 41.875,37.975
  Top Layer w0.12: v1(33.625,15.775) U21.4@33.625,16.575 ; v1(40.45,42.325) 40.467,42.325 41.2,41.592 41.2,39.725 41.875,39.05 41.875,37.975
  Signal Layer 2 w0.12: v1(32.35,41.8) 31.55,41 31.55,38.75 31.875,38.425 31.875,34.95 32.775,34.05 32.775,31.925 32.455,31.605 32.455,30.545 32.825,30.175 32.825,22.025 32.57,21.77 32.57,16.83 v1(33.625,15.775)
  Bottom Layer w0.12: v1(32.35,41.8) 32.35,42.125 32.705,42.48 40.295,42.48 v1(40.45,42.325)
Mems.STSAFE_RESET: R71.1 U13.M5 | length 41.2
  Top Layer w0.08: U13.M5@42.829,35.1 43.079,35.35 43.079,36.579 43.425,36.925 43.425,38.15 43.5,38.225 43.5,39
  Top Layer w0.12: 43.5,39 v1(43.5,41.575)
  Signal Layer 2 w0.12: v1(30.275,40.275) 30.275,38.4 30.855,37.82 30.855,34.57 31.2,34.225 v1(31.2,22.97)
  Bottom Layer w0.12: v1(30.275,40.275) 30,40.55 30,41.771 30.959,42.73 41.22,42.73 42.355,41.595 43.48,41.595 v1(43.5,41.575) ; v1(31.2,22.97) 31.2,22.225 R71.1@31.225,22.2
Mems.VL53_xshut: SB4.2 U27.A5 | length 62.8
  Top Layer w0.12: U27.A5@31.775,3.975 31.775,4.7 32.075,5 v1(32.15,5)
  Signal Layer 2 w0.12: v1(58.925,9.1) 58.925,22.475 59.925,23.475 59.925,34.39 60.125,34.59 v1(60.125,34.625)
  Bottom Layer w0.1: SB4.2@59.1,34.625 v1(60.125,34.625)
  Bottom Layer w0.12: v1(32.15,5) 32.15,3.65 33.65,2.15 54.927,2.15 55.077,2 55.082,1.995 55.495,1.995 55.77,2.27 55.77,6.995 57.875,9.1 v1(58.925,9.1)
Mems.VLX_GPIO: R43.1 SB17.2 U13.J9 U27.A3 | length 55.1
  Top Layer w0.08: v2(40.579,33.85) v3(40.829,33.6)
  Top Layer w0.1: v1(28.913,5) R43.1@30.275,5 U27.A3@30.275,3.975
  Top Layer w0.12: SB17.2@23.525,24.411 23.551,24.385 23.551,24.285 24.411,23.425 v1(24.775,23.425)
  Signal Layer 1 w0.08: 34.7,34.875 36.2,33.375 38.425,33.375 38.45,33.35 v3@38.65,33.35 ; v2(40.579,33.85) v3(40.829,33.6)
  Signal Layer 1 w0.1: v1(32.325,36) 33.575,36 34.7,34.875
  Signal Layer 2 w0.08: v3(38.652,33.35) 38.902,33.1 39.8,33.1 40.3,33.6 v3(40.829,33.6)
  Signal Layer 2 w0.12: v1(28.488,34.262) 29.735,33.015 29.735,28.785 28.825,27.875 26.625,27.875 24.775,26.025 v1(24.775,23.425) 26.125,22.075 26.125,21.3 26.124,21.299 26.124,20.673 26.276,20.521 26.531,20.521 26.532,20.52 27.705,20.52 28.08,20.145 28.08,13.93 27.945,13.795 27.945,5.968 v1(28.913,5)
  Bottom Layer w0.12: v1(28.488,34.262) 29.162,34.262 30.9,36 v1(32.325,36)
MIC.CCK0: U6.4 U13.J7 | length 77.8
  Top Layer w0.08: v3(41.829,33.6) v2(42.079,33.85)
  Top Layer w0.12: v1(40.15,55.625) 40.087,55.562 40.087,55.387 38.975,54.275 33.775,54.275 31.7,56.35 31.7,65.95 32.85,67.1 48.525,67.1 48.825,66.8 52.85,66.8 54.325,68.275 63.125,68.275 v1(63.5,68.65)
  Signal Layer 1 w0.08: v3(41.829,33.6) v2(42.079,33.85)
  Signal Layer 2 w0.08: 40.863,39 40.863,36.962 41.829,35.996 v3(41.829,33.6)
  Signal Layer 2 w0.12: v1(40.15,55.625) 39.855,55.33 39.855,49.833 39.95,49.738 39.95,44.675 39.775,44.5 39.775,40.525 40.863,39.437 40.863,39
  Bottom Layer w0.12: U6.4@62.65,67.574 62.795,67.72 62.795,67.945 63.337,68.487
MIC.CCK1: U7.4 U13.H4 | length 32.4
  Top Layer w0.08: U13.H4@43.329,33.1 v2(43.579,33.35) ; v2(46.5,38.775) 46.5,39
  Top Layer w0.12: 46.5,39 46.5,39.85 50.73,44.08 v1(50.73,45.425)
  Signal Layer 1 w0.08: v2(43.579,33.35) 43.829,33.6 45.525,33.6 46.5,34.575 v2(46.5,38.775)
  Bottom Layer w0.12: v1(50.73,45.425) 51.297,44.858 54.167,44.858 54.775,44.25 54.775,41.675 55.1,41.35 57.25,41.35 57.825,40.775 57.825,39.349 58.179,38.995 60.324,38.995 60.974,39.645 U7.4@60.974,40.113
MIC.SDIN0: U7.1 U13.N5 | length 33.2
  Top Layer w0.08: U13.N5@42.829,35.6 42.829,36.521 42.45,36.9 42.45,37.495 43.075,38.12 43.075,39
  Top Layer w0.12: v1(42.625,42) 43.075,41.55 43.075,39
  Bottom Layer w0.12: v1(42.625,42) 43.783,42 45.483,40.3 47.4,40.3 48.325,41.225 52.2,41.225 54.812,38.613 60.262,38.613 61.054,37.821 62.221,37.821 63.525,39.125 63.525,40.116 63.087,40.554 63.031,40.554 62.952,40.632 62.952,40.734 62.751,40.935 U7.1@62.65,40.935
MIC.SDINx: U6.1 U13.H8 | length 70.8
  Top Layer w0.08: v2(41.079,33.35) v3(41.329,33.1)
  Top Layer w0.12: v1(38.596,54.808) 33.77,54.808 32.085,56.493 32.085,65.81 32.95,66.675 48.35,66.675 48.575,66.45 53.15,66.45 54.4,67.7 v1(58.95,67.7)
  Signal Layer 1 w0.08: v2(41.079,33.35) v3(41.329,33.1)
  Signal Layer 2 w0.08: 39,39 39,37.05 41.079,34.971 v2(41.079,33.35) v3(41.329,33.1)
  Signal Layer 2 w0.12: v1(38.596,54.808) 37.995,54.207 37.995,50.105 38.17,49.93 38.17,40.037 39,39.207 39,39
  Bottom Layer w0.12: v1(58.95,67.7) 59.898,66.752 U6.1@60.974,66.752
NetB3_1: B3.1 B3.2 R39.2 R40.2 U24.1 | length 10.8
  Top Layer w0.12: B3.2@44.725,3.9 B3.1@44.725,9.5 44.787,9.562 U24.1@44.787,12.125 R40.2@45.875,12.125 R39.2@45.875,13.55
NetC10_1: C10.1 C50.2 C125.1 Q7.3 R45.1 U16.2 | length 9
  Top Layer w0.2: U16.2@34.55,24.24 34.61,24.3 v1(36.175,24.3) ; R45.1@36.2,23.7 36.188,23.712 36.188,24.287 v1(36.175,24.3) ; C125.1@36.2,25.1 C125.1@36.213,25.088 ; C125.1@36.225,25.075 36.175,25.025 v1(36.175,24.3) ; R45.1@36.275,23.7 C50.2@37.175,23.7
  Bottom Layer w0.2: Q7.3@33.775,23.7 33.775,23.9 34.175,24.3 v1(36.175,24.3) 36.175,22.472 36.105,22.402 36.105,22.355 35.95,22.2 C10.1@35.925,22.2
NetC10_2: C10.2 Q7.1 R71.2 R72.1 | length 8
  Bottom Layer w0.12: R71.2@31.225,21.3 31.225,20.3 32.15,19.375 34.225,19.375 34.453,19.603 34.453,19.878 R72.1@34.625,20.05 34.725,20.15 Q7.1@34.725,21.5 34.925,21.3 C10.2@35.925,21.3
NetC11_1: C11.1 U8.14 | length 2.4
  Top Layer w0.12: C11.1@19.03,55.7 19.45,55.7 20.25,54.9 U8.14@20.25,54.05
NetC12_1: C12.1 U10.4 | length 1.2
  Top Layer w0.12: U10.4@6,51.212 7.19,51.212 C12.1@7.2,51.223
NetC18_2: C18.2 C19.2 SW3.3 U10.5 | length 13.2
  Top Layer w0.5: U10.5@6,53.112 C18.2@6,54.912 C19.2@6,56.062 6.678,56.062 9.975,52.766 9.975,50.975 9,50 SW3.3@9,48.275
NetC20_2: C20.2 U32.F13 | length 1.6
  Top Layer w0.1: C20.2@67.85,48.05 67.85,47.475 v1(68.225,47.1)
  Bottom Layer w0.12: v1(68.225,47.1) U32.F13@68.55,46.775
NetC30_2: C30.2 U32.M10 | length 1.6
  Top Layer w0.1: v1(70.175,42.55) 70.175,43.3 C30.2@70.425,43.55
  Bottom Layer w0.12: v1(70.175,42.55) U32.M10@70.5,42.875
NetC34_2: C34.2 C36.2 C48.2 C49.2 L1.1 U13.A4 U13.N11 | length 21.8
  Top Layer w0.25: L1.1@38.225,40.75 38.65,40.325 C34.2@38.65,39.275 C34.2@38.65,39.175 ; C34.2@38.675,39.2 C34.2@38.65,39.175 ; U13.N11@39.829,35.6 38.19,37.24 38.19,37.89 C36.2@38.65,38.35 38.65,39 C34.2@38.65,39.175 ; U13.A4@43.329,29.6 43.45,29.479 43.45,28 44.425,27.025 C49.2@44.425,26.4 C48.2@43.475,26.4
  Signal Layer 3 w0.5: v1(38.829,36.6) 43.725,31.704 v1(43.725,27.7)
NetC35_2: C35.2 L1.2 U13.N9 | length 5.8
  Top Layer w0.08: C35.2@39.475,39 39.475,37.845 40.829,36.491 U13.N9@40.829,35.6
  Top Layer w0.12: C35.2@39.475,39 C35.2@39.475,39.275 39.475,40.5 L1.2@39.725,40.75
NetC69_2: C69.2 U25.5 | length 1.1
  Top Layer w0.12: U25.5@27.712,10.05 C69.2@28.8,10.05
NetC79_1: C79.1 JP1.2 U32.J1 | length 12
  Signal Layer 2 w0.1: v1(78.925,47.525) 78.925,46.05 79.1,45.875 v1(79.1,42.925)
  Bottom Layer w0.1: U32.J1@76.35,44.825 78.421,44.825 79.1,44.146 v1(79.1,42.925) ; v1(78.925,47.525) 79.325,47.525
  Bottom Layer w0.12: 79.325,47.525 C79.1@79.625,47.525 79.625,48.52 JP1.2@80.63,49.525
NetC83_2: C83.2 U32.J14 | length 2.3
  Bottom Layer w0.1: C83.2@65.775,45.075 65.825,45.125 67.6,45.125 U32.J14@67.9,44.825
NetC102_1: C102.1 SB6.2 SB7.2 U13.C1 | length 4.3
  Top Layer w0.1: U13.C1@44.829,30.6 45.325,30.6 v1(45.625,30.3)
  Bottom Layer w0.2: SB7.2@42.925,30.3 SB6.2@44.35,30.3 v1(45.625,30.3) C102.1@46.3,30.3
NetC105_2: C105.2 U35.4 | length 1.4
  Bottom Layer w0.12: U35.4@79.575,24.7 C105.2@79.575,26.1
NetC112_2: C112.2 C113.2 D2.2 D3.2 D4.2 U35.1 U35.3
NetC115_2: C115.2 R62.2 SB9.1 U36.2 U36.4 | length 11.4
  Bottom Layer w0.12: U36.4@2.625,16.85 U36.2@8.975,16.85 10.875,16.85 C115.2@10.925,16.9 ; SB9.1@10.925,15.05 C115.2@10.925,16.9 ; R62.2@10.925,18.125 C115.2@10.925,16.9
NetC122_2: C122.2 U1.47 | length 1.5
  Top Layer w0.12: U1.47@8.675,66.25 8.95,66.525 9.975,66.525 C122.2@10.05,66.6
NetC123_2: C123.2 U1.46 | length 1.4
  Top Layer w0.12: U1.46@8.675,65.775 C123.2@10.05,65.775
NetC124_1: C124.1 U1.45 | length 1.5
  Top Layer w0.12: U1.45@8.675,65.325 9.425,65.325 9.625,65.125 9.9,65.125 C124.1@10.05,64.975
NetCN7_1: CN7.1 TP7.1 | length 18.5
  Top Layer w0.12: TP7.1@5.1,19.275 5.1,26.05 6.05,27 10.475,27 12.51,29.035 CN7.1@15.61,29.035
NetCN7_2: CN7.2 TP4.1 | length 5.8
  Top Layer w0.15: CN7.2@18.16,29.035 TP4.1@24,29.035
NetCN7_18: CN7.18 TP6.1 | length 6.7
  Top Layer w0.15: CN7.18@18.16,21.035 20.79,21.035 22.85,18.975 TP6.1@24,18.975
NetCN7_20: CN7.20 TP8.1 | length 7.7
  Top Layer w0.15: CN7.20@18.16,20.035 21.19,20.035 22.885,18.34 22.885,17.34 23.275,16.95 TP8.1@24,16.95
NetCN7_34: CN7.34 TP9.1 | length 6.5
  Top Layer w0.12: CN7.34@18.16,13.035 19.56,13.035 21.1,14.575 TP9.1@24,14.575
NetCN7_35: CN7.35 TP11.1 | length 10.5
  Top Layer w0.12: TP11.1@5.1,12.025 5.11,12.035 CN7.35@15.61,12.035
NetCN7_36: CN7.36 TP10.1 | length 6.1
  Top Layer w0.12: CN7.36@18.16,12.035 20.585,12.035 21.2,12.65 TP10.1@24,12.65
NetCN12_2: CN12.2 U30.5 | length 2.5
  Bottom Layer w0.12: CN12.2@4.3,54.075 5.06,54.075 5.22,54.235 6.28,54.235 6.34,54.175 U30.5@6.7,54.175
NetCN12_3: CN12.3 U30.6 | length 2.5
  Bottom Layer w0.12: CN12.3@4.3,54.725 5.06,54.725 5.17,54.615 6.28,54.615 6.34,54.675 U30.6@6.7,54.675
NetCN12_4: CN12.4 R46.2 | length 1.8
  Bottom Layer w0.12: CN12.4@4.3,55.375 5.165,55.375 5.75,55.96 R46.2@5.875,55.96
NetCN13_8: CN13.8 R47.1 | length 1.8
  Bottom Layer w0.12: CN13.8@61.964,53.856 61.964,52.036 R47.1@61.975,52.025
NetCN15_1: CN15.1 SB7.1 | length 27.8
  Signal Layer 2 w0.2: v1(26.7,38.825) 26.705,38.82 26.705,36.775 26.705,33.465 v1(28.27,31.9)
  Bottom Layer w0.2: v1(26.7,38.825) 27.775,38.825 28.335,39.385 CN15.1@28.335,40.7 ; v1(28.27,31.9) 28.27,30.78 30.275,28.775 33.775,28.775 34.5,29.5 35.15,29.5 35.415,29.235 42.89,29.235 SB7.1@42.925,29.2
NetCN16_5: CN16.5 SB10.2 SB11.2 | length 7.6
  Bottom Layer w0.12: CN16.5@24.88,5.596 24.88,8.295 23.775,9.4 SB11.2@23.775,11.25 SB10.2@25.225,11.25
NetCN16_6: CN16.6 SB12.2 SB13.2 | length 3.7
  Bottom Layer w0.12: SB13.2@20.925,11.25 SB12.2@22.35,11.25 22.34,11.24 CN16.6@22.34,9.025
NetCN17_1: CN17.1 R63.1 | length 1.9
  Bottom Layer w0.12: R63.1@57.9,3.65 CN17.1@57.9,5.595
NetLD1_1: LD1.1 R1.2 | length 1.4
  Top Layer w0.12: LD1.1@28.225,68.875 28.35,69 R1.2@29.575,69
NetLD1_2: LD1.2 Q1.3 | length 1.7
  Top Layer w0.12: Q1.3@28.225,65.625 LD1.2@28.225,67.375
NetLD2_1: LD2.1 R9.2 | length 1.4
  Top Layer w0.12: LD2.1@57.375,54.75 R9.2@58.75,54.75
NetLD2_2: LD2.2 Q3.3 | length 1.2
  Top Layer w0.12: Q3.3@57.375,52.225 LD2.2@57.375,53.45
NetLD3_2: LD3.2 R17.1 | length 1.4
  Top Layer w0.12: R17.1@85.8,37.775 LD3.2@87.175,37.775
NetLD3_3: LD3.3 R16.1 | length 1.4
  Top Layer w0.12: R16.1@85.8,39.275 LD3.3@87.175,39.275
NetLD4_1: LD4.1 R33.1 | length 1
  Top Layer w0.12: LD4.1@95.425,21.825 R33.1@96.45,21.825
NetLD4_2: LD4.2 R36.1 U18.3 | length 4.3
  Top Layer w0.12: U18.3@94.35,23.225 93.925,23.225 LD4.2@93.925,21.825 93.925,20.725 94.25,20.4 R36.1@95.175,20.4
NetLD5_1: LD5.1 R44.1 | length 1
  Top Layer w0.12: R44.1@57.15,3.3 LD5.1@57.15,4.325
NetLD6_2: LD6.2 R41.1 | length 1.1
  Top Layer w0.12: LD6.2@35.85,5.775 R41.1@35.85,6.85
NetLD7_2: LD7.2 R42.1 | length 1.1
  Top Layer w0.12: LD7.2@37.35,5.775 R42.1@37.35,6.85
NetM1_19: M1.19 SW2.1 | length 17.8
  Top Layer w0.1: M1.19@72.68,24.147 75.097,24.147 78.35,27.4 78.35,35.3 79.815,36.765 SW2.1@79.815,37.575
NetM1_23: M1.23 SW2.2 | length 30.3
  Top Layer w0.1: M1.23@72.68,16.147 70.853,16.147 69.825,17.175 69.825,20.125 70.875,21.175 74.275,21.175 80.25,27.15 80.25,34.8 81.085,35.635 SW2.2@81.085,37.575
NetQ1_1: Q1.1 R2.2 R4.2 | length 3.1
  Top Layer w0.12: Q1.1@27.275,63.425 27.55,63.15 R2.2@27.55,61.775 R4.2@27.55,60.4
NetQ2_1: Q2.1 Q2.3 U8.6 | length 11.1
  Top Layer w0.12: U8.6@22.675,51.125 22.9,51.125 23.6,50.425 v1(25.3,50.425)
  Bottom Layer w0.12: v1(21.8,45.4) 20.8,46.4 20.8,46.85 21.8,47.85 23.325,47.85 24.455,48.98 24.455,49.58 v1(25.3,50.425)
NetQ2_2: Q2.2 Q2.4 U8.5 | length 15.8
  Top Layer w0.12: v1(21.75,49.475) U8.5@21.75,50.2 ; Q2.2@22.825,44.135 23.14,44.135 23.85,43.425 23.85,42.32 23.125,41.595 Q2.4@22.825,41.595 23.15,41.27 v1(23.15,40.225)
  Signal Layer 2 w0.12: v1(21.75,49.475) 22.075,49.15 22.395,48.83 22.395,48.08 22.977,47.498 22.977,40.398 v1(23.15,40.225) v1@23.125,40.225
NetQ2_7: Q2.7 Q2.8 Q6.7 Q6.8 R13.2 U8.10 | length 8.3
  Top Layer w0.12: U8.10@22.675,53.125 22.95,53.125 v1(23.45,53.625)
  Top Layer w0.45: v1(23.55,49.5) 23.55,48.475 R13.2@23.675,48.35 24.575,48.35 v1(25.05,47.875)
  Signal Layer 2 w0.12: v1(23.45,53.625) 23.02,53.195 23.02,50.58 23.55,50.05 v1(23.55,49.5)
NetQ3_1: Q3.1 R48.2 | length 1.5
  Top Layer w0.12: v1(56.875,50.375) Q3.1@56.875,51.175
  Bottom Layer w0.12: v1(56.875,50.375) R48.2@56.875,51.1
NetQ6_1: Q6.1 Q6.3 U8.8 | length 23.2
  Top Layer w0.12: U8.8@22.675,52.125 24.9,52.125 v1(25.4,51.625)
  Signal Layer 2 w0.12: v1(19.2,49.025) 19.873,49.025 21.35,47.548 21.35,47.148 20.898,46.695 20.898,39.548 v1(19.975,38.625)
  Bottom Layer w0.12: v1(19.2,49.025) 19.2,49.665 20.585,51.05 20.95,51.05 21.93,52.03 24.995,52.03 v1(25.4,51.625)
NetQ6_2: Q6.2 Q6.4 U8.7 | length 24
  Top Layer w0.12: v1(20.35,39.7) 21.025,39.7 21.025,39.625 22.1,38.55 22.1,37.36 Q6.2@21.475,36.735 ; Q6.4@21.175,34.195 21.475,34.195 22.2,34.92 22.2,36.058 21.523,36.735 Q6.2@21.475,36.735 ; Q6.2@21.175,36.735 Q6.2@21.475,36.735 ; U8.7@22.675,51.625 v1(23.425,51.625)
  Signal Layer 2 w0.12: v1(20.35,39.7) 20.658,40.008 20.658,47.052 20.85,47.244 v1(20.85,47.475)
  Bottom Layer w0.12: v1(20.85,47.475) 19.825,48.5 19.825,49.925 20.525,50.625 21.9,50.625 22.9,51.625 v1(23.425,51.625)
NetR3_2: R3.2 SW6.2 | length 18.6
  Top Layer w0.12: R3.2@1,61.75 v1(1,62.35) ; v1(2.175,45.95) SW6.2@3.3,45.95
  Signal Layer 2 w0.12: v1(1,62.35) 1,47.125 v1(2.175,45.95)
NetR7_1: R7.1 R8.1 U8.11 | length 5.7
  Top Layer w0.12: U8.11@21.75,54.05 26.2,54.05 26.4,54.25 R7.1@26.4,53.3
NetR15_2: R15.2 U9.A5 | length 3
  Top Layer w0.15: U9.A5@44,45.6 44.4,45.2 R15.2@46.85,45.2
NetR35_1: R35.1 SW1.2 | length 3.1
  Top Layer w0.12: R35.1@50.7,19.9 50.7,19.225 51.79,18.135 52.365,18.135 SW1.2@52.4,18.1 SW1.2@52.4,18.365
NetR45_2: R45.2 U16.1 | length 1.5
  Top Layer w0.2: U16.1@34.772,22.8 R45.2@36.275,22.8
NetR49_1: R49.1 U32.F15 | length 1.4
  Bottom Layer w0.1: R49.1@65.85,46.775 U32.F15@67.25,46.775
NetR50_1: R50.1 X3.3 | length 1.3
  Bottom Layer w0.12: R50.1@79.775,46.1 X3.3@81.075,46.1
NetR50_2: R50.2 U32.G1 | length 2.5
  Bottom Layer w0.1: U32.G1@76.35,46.125 78.85,46.125 R50.2@78.875,46.1
NetR51_2: R51.2 U32.J15 | length 1.9
  Bottom Layer w0.1: R51.2@65.85,43.825 65.85,43.95 66.725,44.825 U32.J15@67.25,44.825
NetR52_2: R52.2 U32.L4 | length 3.5
  Bottom Layer w0.1: 74.725,43.2 76.525,43.2 77,43.675 R52.2@77.6,43.675
  Bottom Layer w0.12: U32.L4@74.4,43.525 74.725,43.2
NetR53_2: R53.2 X3.1 | length 1.2
  Bottom Layer w0.12: R53.2@82.725,43.675 X3.1@82.725,44.85
NetR54_1: R54.1 R55.1 U32.N3 | length 4.2
  Bottom Layer w0.1: U32.N3@75.05,42.225 74.725,41.9 74.725,39.45 R55.1@74.475,39.45 R54.1@75.55,39.45
NetR61_2: R61.2 R62.1 U36.1 | length 4.3
  Bottom Layer w0.12: R61.2@8.975,21.35 U36.1@8.975,19.15 9.35,19.525 R62.1@10.925,19.525
NetR64_1: R64.1 SW2.4 | length 3.6
  Top Layer w0.12: SW2.4@79.815,43.725 79.815,42.76 79.95,42.625 v1(80.65,42.625)
  Bottom Layer w0.1: v1(80.65,42.625) 80.65,41.275 R64.1@80.9,41.025
NetR65_1: R65.1 SW2.3 | length 3.4
  Top Layer w0.12: SW2.3@81.085,43.725 81.35,43.46 v1(81.35,42.65)
  Bottom Layer w0.1: v1(81.35,42.65) 81.35,42.1 82.4,41.05 R65.1@82.575,41.05
NetR66_1: R66.1 U7.2 | length 3.5
  Bottom Layer w0.12: U7.2@62.65,40.113 62.449,40.314 62.297,40.314 62.107,40.503 62.107,42.036 62.297,42.225 R66.1@63.25,42.225
NetR67_1: R67.1 U13.G6 | length 10.9
  Top Layer w0.08: v3(42.329,32.6) v2(42.579,32.35)
  Top Layer w0.1: R67.1@45.025,41.375 45.04,41.36 v2(45.04,40.865)
  Signal Layer 1 w0.08: v3(42.329,32.6) v2(42.579,32.35) ; v3(45.04,40.4) v2(45.04,40.865)
  Signal Layer 2 w0.08: v3(42.329,32.6) 42.58,32.85 43.075,32.85 44.425,34.2 44.425,37.446 45.04,38.061 45.04,39
  Signal Layer 2 w0.09: 45.04,39 v3(45.04,40.4)
NetR68_2: R68.2 U13.B3 | length 4.8
  Top Layer w0.08: U13.B3@43.829,30.1 44.079,29.85 44.079,29.096
  Top Layer w0.1: 44.079,29.096 44.079,28.512 45.924,26.666 45.924,26.251 R68.2@45.95,26.225
NetR69_2: R69.2 U13.K9 | length 5.3
  Top Layer w0.1: v2(40.579,34.35) U13.K9@40.829,34.1
  Signal Layer 1 w0.08: v2(40.579,34.35) 40.829,34.6 40.829,34.746 40.829,37.654 v1(41.35,38.175) ; v1@41.288,38.238 v1@41.35,38.3
  Bottom Layer w0.1: v1(41.35,38.175) 41.384,38.175 41.584,38.375 R69.2@42.025,38.375
NetR70_2: R70.2 U13.L9 | length 10.2
  Top Layer w0.1: v2(40.579,34.85) U13.L9@40.829,34.6
  Signal Layer 1 w0.08: v2(40.579,34.85) 40.579,38.179 v1(41.375,38.975)
  Bottom Layer w0.1: v1(41.375,38.975) 46.625,38.975 R70.2@46.725,38.875
NetSB17_1: SB17.1 U17.3 | length 2.5
  Top Layer w0.12: SB17.1@23.525,25.511 23.551,25.536 23.551,25.631 23.556,25.636 23.556,26.485 23.82,26.75 U17.3@24.955,26.75
NetTP1_1: TP1.1 U9.C5 | length 2.2
  Top Layer w0.15: TP1.1@42,43.375 U9.C5@42,45.6
NetTP2_1: TP2.1 U13.M1 | length 12.2
  Top Layer w0.08: U13.M1@44.829,35.1 45.7,35.1 46.225,35.625 46.225,36.075 47.525,37.375 47.975,37.375
  Top Layer w0.12: 47.975,37.375 TP2.1@55.85,37.375
NetTP3_1: TP3.1 U13.H5 | length 29.8
  Top Layer w0.08: v3(42.829,33.1) v2(43.079,33.35)
  Top Layer w0.12: v2(46.675,41.7) 46.8,41.7 v1(48.9,43.8) ; v1(53.95,35.7) 55.15,35.7 TP3.1@55.85,35
  Signal Layer 1 w0.08: v3(42.829,33.1) v2(43.079,33.35) ; v3(44.79,38.165) 45.625,39
  Signal Layer 1 w0.12: 45.625,39 46.675,40.05 v2(46.675,41.7)
  Signal Layer 2 w0.08: v3(42.829,33.1) 43,33.1 43.35,33.45 43.35,36.325 44.2,37.175 44.2,37.575 v3(44.79,38.165)
  Signal Layer 2 w0.12: v1(53.95,35.7) v1(53.95,42.3)
  Bottom Layer w0.12: v1(48.9,43.8) 48.92,43.78 52.917,43.78 52.937,43.8 53.875,43.8 54.425,43.25 54.425,42.775 v1(53.95,42.3)
NRST: B2.1 B2.2 C42.2 CN9.12 CN10.10 CN17.3 R14.1 R22.1 R38.1 U11.5 U13.H3 U23.1 | length 124.4
  Top Layer w0.08: U13.H3@43.829,33.1 44.079,32.85 ; 44.212,32.85 44.079,32.85 ; 45.24,33.14 44.95,32.85 44.079,32.85
  Top Layer w0.1: 45.24,33.14 46.385,33.14 C42.2@46.6,32.925 46.425,32.75 v2(46.075,32.75)
  Top Layer w0.12: R38.1@48.15,16.6 50.175,14.575 v1(51.875,14.575) ; R14.1@48.25,46.6 v1(49.15,46.6) ; B2.1@49.9,2.25 B2.2@49.9,11.15 49.9,13.363 U23.1@49.912,13.375 55.15,13.375 55.365,13.16 v1(57.61,13.16) ; v2(53.95,33.775) v1(56.825,33.775) ; v1(61.46,23.605) CN9.12@61.46,25.793 61.46,26.76 62.23,27.53 62.23,27.868 62.18,27.918 62.18,33.93 U11.5@62.225,33.975 R22.1@63.5,33.975 v1(63.5,33.325) ; v1(62.075,16.025) 65.4,16.025 66.54,17.165 CN10.10@66.54,17.99
  Signal Layer 1 w0.08: v2(46.075,32.75) 46.425,32.75 47.45,33.775 v2(53.95,33.775)
  Signal Layer 2 w0.12: v1(51.87,5.595) v1(51.87,13.37) 51.875,13.375 v1(51.875,14.575) ; v1(57.25,46.4) 57.25,45.825 57.28,45.795 57.28,34.23 v1(56.825,33.775) 56.83,33.77 56.83,27.645 57.61,26.865 v1(57.61,13.16) ; v1(61.46,23.605) 61.46,22.128 62.075,21.513 v1(62.075,16.025)
  Bottom Layer w0.12: v1(49.15,46.6) 53.95,46.6 54.15,46.4 v1(57.25,46.4) ; v1(51.87,5.595) CN17.3@52.82,5.595 ; v1(56.825,33.775) 63.05,33.775 v1(63.5,33.325)
OCTOSPI.F_CLK_P: R67.2 U9.B2 | length 25.3
  Top Layer w0.1: U9.B2@43,48.6 45,50.6 45,52 45.225,52.225 45.45,52.225 45.7,51.975 45.7,49.9 v1(45.125,49.325) ; R67.2@45.025,42.275 45.03,42.275 45.235,42.48 v2(45.235,42.94)
  Signal Layer 1 w0.08: v2(45.235,42.94) v3(45.235,43.4)
  Signal Layer 2 w0.09: v1(45.125,49.325) 45.9,49.325 45.975,49.4 45.975,53.375 46.1,53.5 46.275,53.5 46.35,53.425 46.35,49.325 45.975,48.95 45.566,48.95 45.235,48.619 v3(45.235,43.4)
OCTOSPI.F_DQS: U9.C3 U13.K6 | length 30.3
  Top Layer w0.1: U9.C3@42,47.6 v1(42.5,47.1) ; U13.K6@42.329,34.1 v2(42.579,34.35)
  Signal Layer 1 w0.08: v2(42.579,34.35) 42.829,34.6 42.829,34.746 ; 42.829,34.746 42.829,34.954 ; 42.829,34.954 42.829,35.085
  Signal Layer 1 w0.1: 42.829,35.085 v1(42.829,37.379)
  Signal Layer 2 w0.09: v1(42.5,47.1) 42.5,47.919 43.15,48.569 43.15,54.275 43.3,54.425 43.948,54.425 44.3,54.073 44.3,46 43.365,45.065 43.365,42.688 43.075,42.398 43.075,37.625 v1(42.829,37.379)
OCTOSPI.F_IO0: U9.D3 U13.E2 | length 30.1
  Top Layer w0.08: U13.E2@44.329,31.6 44.579,31.35 45.334,31.35
  Top Layer w0.1: U9.D3@41,47.6 41.5,47.1 v1(41.5,44.4) ; 45.334,31.35 46.125,31.35 v1(46.425,31.05)
  Signal Layer 2 w0.09: v1@46.35,31.05 45.525,31.05 45.45,31.125 45.45,31.45 45.525,31.525 46.3,31.525 46.425,31.65 46.425,31.875 46.325,31.975 45.525,31.975 45.45,32.05 45.45,32.275 45.55,32.375 46.275,32.375 46.425,32.525 46.425,33.025 ; 46.4,33.025 46.35,33.075 45.95,33.075 45.825,33.2 45.825,33.425 46.425,34.025 46.425,39.2 46.35,39.275 45.925,39.275 45.775,39.425 45.775,39.6 45.9,39.725 46.325,39.725 46.425,39.825 46.425,40.075 ; 46.4,40.075 46.375,40.1 45.8,40.1 45.72,40.18 45.72,40.35 45.82,40.45 46.225,40.45 46.425,40.65 v1(46.425,44)
  Bottom Layer w0.1: v1(41.5,44.4) 41.9,44 v1(46.425,44)
OCTOSPI.F_IO1: U9.D2 U13.F3 | length 30.2
  Top Layer w0.08: U13.F3@43.829,32.1 44.079,31.85 45.325,31.85
  Top Layer w0.1: U9.D2@41,48.6 v1(41.5,49.1) ; 45.325,31.85 47.05,31.85 47.35,31.55 v1(47.9,31.55)
  Signal Layer 2 w0.09: v1(47.875,49.775) 47.875,32.45 47.9,32.425 v1(47.9,31.55)
  Bottom Layer w0.1: v1(41.5,49.1) 42.184,49.1 43.174,50.09 47.56,50.09 v1(47.875,49.775)
OCTOSPI.F_IO2: U9.C4 U13.F4 | length 29.6
  Top Layer w0.1: U9.C4@42,46.6 42.5,46.1 42.5,45 43.12,44.38 45.72,44.38 45.825,44.275 45.825,44.05 45.725,43.95 42.95,43.95 42.825,43.825 42.825,43.625 42.975,43.475 v1@43.9,43.475 ; U13.F4@43.329,32.1 v2(43.579,31.85) ; v1@43.913,43.488 v1(43.925,43.475)
  Signal Layer 1 w0.08: v2(43.579,31.85) 43.829,31.6 46.95,31.6 v1(47.475,32.125)
  Signal Layer 2 w0.09: v1(47.475,32.125) v1(47.475,43.475)
  Bottom Layer w0.1: v1(43.925,43.475) v1(47.475,43.475)
OCTOSPI.F_IO3: U9.D4 U13.G5 | length 30.4
  Top Layer w0.1: v1(40.5,46.1) U9.D4@41,46.6 ; v3(42.829,32.6) v2(43.079,32.35)
  Signal Layer 1 w0.08: v3(42.829,32.6) v2(43.079,32.35)
  Signal Layer 2 w0.09: v3(42.829,32.6) 43.325,32.6 44.65,33.925 44.65,35.975 44.775,36.1 44.925,36.1 45.025,36 45.025,34.675 45.15,34.55 45.46,34.55 45.512,34.603 45.512,37.481 45.38,37.613 45.38,39 45.38,41.072 45.6,41.292 45.6,45.05 45.995,45.445 45.995,47.353 45.96,47.388 45.96,48.525 45.884,48.601 45.699,48.601 45.625,48.528 v1@45.625,46.125
  Bottom Layer w0.1: v1(40.5,46.1) v1(45.625,46.1)
OCTOSPI.F_IO4: U9.D5 U13.E9 | length 30.3
  Top Layer w0.1: v1(36.05,44.625) 40.025,44.625 U9.D5@41,45.6 ; v2(40.579,31.35) v3(40.829,31.6)
  Signal Layer 1 w0.08: v2(40.579,31.35) v3(40.829,31.6)
  Signal Layer 2 w0.09: v1(36.05,44.625) 36.05,43.175 35.765,42.89 35.765,28.085 35.9,27.95 36.1,27.95 36.225,28.075 36.225,29.625 36.525,29.925 39.154,29.925 v3(40.829,31.6)
OCTOSPI.F_IO5: U9.E3 U13.C13 | length 31.9
  Top Layer w0.1: v1(35.4,29.85) 36.225,29.85 36.525,30.15 38.05,30.15 38.5,30.6 U13.C13@38.829,30.6 ; v1(35.4,47.6) U9.E3@40,47.6
  Signal Layer 2 w0.09: v1(35.4,29.85) 35.4,44.541 35.874,45.015 36.245,45.015 36.455,45.225 36.455,47.495 36.35,47.6 36.175,47.6 36,47.425 36,45.5 35.9,45.4 35.5,45.4 35.4,45.5 v1(35.4,47.6)
OCTOSPI.F_IO6: U9.E2 U13.D9 | length 34.6
  Top Layer w0.1: v1(34.7,27.7) v2(38.379,27.7) ; v1(35.375,48.6) U9.E2@40,48.6 ; v2(40.579,30.85) U13.D9@40.829,31.1
  Signal Layer 1 w0.08: 40.329,28.85 40.329,30.6 v2(40.579,30.85)
  Signal Layer 1 w0.1: v2(38.379,27.7) 39.179,27.7 40.329,28.85
  Signal Layer 2 w0.09: v1(34.7,27.7) 35.325,28.325 35.325,29.375 35.04,29.66 35.04,40.787 35.01,40.817 35.01,48.235 v1(35.375,48.6)
OCTOSPI.F_IO7: U9.E1 U13.B13 | length 30.6
  Top Layer w0.1: v1(34.7,29.05) 36.125,29.05 36.625,29.55 38.279,29.55 U13.B13@38.829,30.1 ; v1(35,49.6) U9.E1@40,49.6
  Signal Layer 2 w0.09: v1(34.7,29.05) 34.7,40.023 34.26,40.463 34.26,40.787 34.295,40.822 34.295,48.895 v1(35,49.6)
OCTOSPI.F_NCS: R12.1 R68.1 U9.C2 | length 33.7
  Top Layer w0.09: R68.1@46.85,26.225 46.875,26.25 v1(46.875,26.975)
  Top Layer w0.1: U9.C2@42,48.6 42.5,49.1 42.5,51.225 42.741,51.466 43.466,51.466 44.776,52.776 45.499,52.776 v1(46.95,51.325)
  Signal Layer 2 w0.09: v1(46.875,26.975) 46.875,30.55 46.95,30.625 v1(46.95,51.325)
OCTOSPI.R_CLK_P: R69.1 U20.B2 U37.6 | length 45.7
  Top Layer w0.1: U20.B2@43,18.6 44.35,19.95 v1(46,19.95)
  Signal Layer 2 w0.09: v1(44.7,15.325) 44.7,18.65 v1(46,19.95) 46,20.425 46.05,20.475 46.05,25.925 46.05,27.625 45.075,28.6 45.075,33.175 46,34.1 v1(46,38.3)
  Bottom Layer w0.1: U37.6@42.709,15.888 U37.6@42.184,15.888 42.184,15.65 44.375,15.65 v1(44.7,15.325) ; R69.1@42.925,38.4 43.016,38.491 45.259,38.491 45.425,38.325 45.425,37.975 45.675,37.725 51.075,37.725 51.175,37.825 51.175,38.175 51.05,38.3 v1(46,38.3)
OCTOSPI.R_DQS: U13.D3 U20.C3 | length 50.8
  Top Layer w0.1: U20.C3@42,17.6 42.525,18.125 44.727,18.125 v1(45.75,19.148) ; U13.D3@43.829,31.1 v2(44.079,30.85)
  Signal Layer 1 w0.08: v2(44.079,30.85) 45.663,30.85 46.113,30.4 v3(46.55,30.4)
  Signal Layer 2 w0.09: v1(45.75,19.148) 46.011,18.888 46.34,18.558 46.34,9.96 46.45,9.85 46.625,9.85 46.7,9.925 46.7,17.6 46.8,17.7 47,17.7 47.075,17.625 47.075,11.75 47.175,11.65 47.325,11.65 47.425,11.75 47.425,18.05 46.39,19.085 46.39,25.925 46.39,27.74 46.55,27.9 v3(46.55,30.4)
OCTOSPI.R_IO0: U13.F1 U20.D3 U37.5 | length 50.3
  Top Layer w0.08: U13.F1@44.829,32.1 46.724,32.1 46.917,32.293
  Top Layer w0.1: U20.D3@41,17.6 v1(41.5,18.1) ; v1(42.775,21.9) v1(47.15,21.9) ; 46.917,32.293 47.109,32.485 48.175,32.485 48.285,32.375 v1(48.75,32.375)
  Signal Layer 2 w0.09: v1(41.5,18.1) 41.25,17.85 41.25,6.325 41.35,6.225 41.55,6.225 41.635,6.31 41.635,17.135 42.775,18.275 v1(42.775,21.9) ; v1(47.15,21.9) 47.15,26.175 47.575,26.6 47.575,30.044 48.75,31.219 v1(48.75,32.375)
  Bottom Layer w0.1: v1(41.5,18.1) 42.025,18.1 42.184,17.941 U37.5@42.184,17.158
OCTOSPI.R_IO1: U13.G3 U20.D2 U37.2 | length 54.6
  Top Layer w0.1: U20.D2@41,18.6 v1(41.5,19.1) ; v1(42.125,21.505) 42.13,21.5 44.741,21.5 44.776,21.535 46.915,21.535 46.95,21.5 v1(47.85,21.5) ; v2(43.579,32.85) U13.G3@43.829,32.6
  Signal Layer 1 w0.08: v2(43.579,32.85) 43.829,32.6 43.829,32.237 43.976,32.091 46.491,32.091 47.475,33.075 48.175,33.075 48.3,32.95 v1(49.175,32.95)
  Signal Layer 2 w0.09: v1(40.808,14.618) 40.808,18.008 41.5,18.7 v1(41.5,19.1) 40.46,18.06 40.46,10.66 40.375,10.575 40.205,10.575 40.125,10.655 40.125,18.125 41,19 41,19.65 42.125,20.775 v1(42.125,21.505) ; v1(47.85,21.5) 47.85,21.843 47.75,21.943 47.75,25.925 47.75,26.375 47.863,26.488 47.863,29.852 49.175,31.163 v1(49.175,32.95)
  Bottom Layer w0.1: U37.2@37.434,14.618 v1(40.808,14.618)
OCTOSPI.R_IO2: U13.G2 U20.C4 U37.3 | length 50.6
  Top Layer w0.08: U13.G2@44.329,32.6 44.579,32.35 v2(45.775,32.35)
  Top Layer w0.1: U20.C4@42,16.6 42.525,16.075 42.525,15.125 42.875,14.775 v1(47.975,14.775)
  Signal Layer 1 w0.08: v2(45.775,32.35) 46.425,32.35 47.5,33.425 49.5,33.425 v1(50,32.925)
  Signal Layer 2 w0.09: v1(47.975,14.775) 47.975,10.2 48.1,10.075 48.35,10.075 48.45,10.175 48.45,17.9 49.425,18.875 49.425,20.85 48.45,21.825 48.175,22.1 48.175,29.377 48.2,29.402 48.2,29.708 50,31.508 v1(50,32.925)
  Bottom Layer w0.1: U37.3@37.434,15.888 37.621,16.075 40.15,16.075 40.972,15.253 43.672,15.253 v1(44.15,14.775)
OCTOSPI.R_IO3: U13.H6 U20.D4 U37.7 | length 54.2
  Top Layer w0.1: U20.D4@41,16.6 41.5,16.1 41.5,14.7 41.95,14.25 v1(49.725,14.25) ; v3(42.329,33.1) v2(42.579,33.35)
  Signal Layer 1 w0.08: v3(42.329,33.1) v2(42.579,33.35)
  Signal Layer 2 w0.08: v3(42.329,33.1) v2(42.579,33.35) 43.002,33.35 43.125,33.473
  Signal Layer 2 w0.09: 43.125,33.473 43.125,36.475 43.925,37.275 43.925,39 43.925,39.25 v1(44.35,39.675) ; v1(49.725,14.25) 49.725,17.125 50.225,17.625 50.225,22.575 49.225,23.575 49.225,28.7 51.1,30.575 51.1,39.65 v1(51.025,39.725)
  Bottom Layer w0.1: U37.7@42.184,14.618 43.207,14.618 v1(43.575,14.25) ; v1(44.35,39.675) 44.575,39.9 50.85,39.9 v1(51.025,39.725)
OCTOSPI.R_IO4: U13.F10 U20.D5 | length 51.6
  Top Layer w0.1: v1(36.175,15.125) 40.525,15.125 U20.D5@41,15.6 ; v2(40.079,31.85) U13.F10@40.329,32.1
  Signal Layer 1 w0.08: v1(33.765,31.16) 37.927,31.16 38.877,32.11 39.819,32.11 v2(40.079,31.85)
  Signal Layer 2 w0.09: v1(33.765,31.16) 33.765,17.26 34.2,16.825 34.2,7.1 34.3,7 34.5,7 34.55,7.05 34.55,17.8 34.65,17.9 35.473,17.9 35.825,17.548 35.825,17.1 36.175,16.75 v1(36.175,15.125)
OCTOSPI.R_IO5: U13.B12 U20.E3 | length 51.6
  Top Layer w0.08: 39.079,29.475 39.079,29.85 U13.B12@39.329,30.1
  Top Layer w0.1: v1(36.85,18.7) 38.9,18.7 U20.E3@40,17.6 ; v1(36.85,28.825) 38.429,28.825 39.079,29.475
  Signal Layer 2 w0.09: v1(36.85,18.7) 37.475,18.7 37.615,18.56 37.615,10.335 37.7,10.25 37.875,10.25 37.95,10.325 37.95,17.9 38.025,17.975 38.2,17.975 38.275,17.9 38.275,10.325 38.4,10.2 38.548,10.2 38.645,10.297 38.645,18.13 36.85,19.925 v1(36.85,28.825)
OCTOSPI.R_IO6: U13.K1 U20.E2 | length 51.4
  Top Layer w0.1: v1(39.525,19.075) U20.E2@40,18.6 ; v1(40.05,22.325) 40.07,22.305 49.295,22.305 v1(49.3,22.3) ; U13.K1@44.829,34.1 45.9,34.1 46.575,34.775 48.975,34.775 49.125,34.925 49.8,34.925 49.95,34.775 v1(50.3,34.775)
  Signal Layer 2 w0.09: v1(39.525,19.075) 39.525,21.8 v1(40.05,22.325) ; v1(49.3,22.3) 48.885,22.715 48.885,28.86 50.76,30.735 50.76,38.196 49.85,39.106 49.85,43.525 49.775,43.6 49.55,43.6 49.475,43.525 49.475,39.013 50.3,38.188 v1(50.3,34.775)
OCTOSPI.R_IO7: U13.D7 U20.E1 | length 51.5
  Top Layer w0.1: U20.E1@40,19.6 v1(40.5,19.1) ; v2(41.579,30.85) U13.D7@41.829,31.1
  Signal Layer 1 w0.08: v2(41.579,30.85) 41.829,30.6 41.829,29.025
  Signal Layer 1 w0.1: v3(41.829,26.275) 41.675,26.429 41.675,27.125 41.829,27.279 41.829,29.025
  Signal Layer 2 w0.09: v1(40.5,19.1) 39.775,18.375 39.775,10.524 40.525,9.774 40.525,7.375 40.4,7.25 40.2,7.25 40.125,7.325 40.125,9.625 40.025,9.725 39.875,9.725 39.775,9.625 39.775,3.625 39.675,3.525 39.525,3.525 39.424,3.626 39.424,18.396 39.925,18.897 39.925,19.55 41,20.625 41,25.446 v3(41.829,26.275)
OCTOSPI.R_NCS: R37.1 R70.1 U20.A3 U37.1 | length 40
  Top Layer w0.1: U20.A3@44,17.6 v1(45.305,17.6) 45.73,18.025 R37.1@46.75,18.025 46.825,18.1 v1(46.825,19.375)
  Signal Layer 2 w0.09: v1(43.95,11.445) 44.355,11.445 45.305,12.395 v1(45.305,17.6) ; v1(46.825,19.375) 46.825,20.75 46.75,20.825 46.75,26.25 47.27,26.77 47.27,30.22 48.275,31.225 v1(48.275,38.85)
  Bottom Layer w0.1: U37.1@37.434,13.348 37.434,12.291 38.28,11.445 v1(43.95,11.445) ; R70.1@47.625,38.875 47.65,38.85 v1(48.275,38.85)
OCTOSPI_FLASH_RESET: R14.2 U9.A4 | length 2.9
  Top Layer w0.15: U9.A4@44,46.6 R14.2@46.85,46.6
OCTOSPI_SRAM_RESET: R38.2 U20.A4 | length 2.7
  Top Layer w0.15: U20.A4@44,16.6 R38.2@46.75,16.6
PC14-OSC32_IN: C46.1 U13.D1 X2.2 | length 9.5
  Top Layer w0.08: U13.D1@44.829,31.1 45.329,31.1
  Top Layer w0.1: 45.329,31.1 45.675,31.1 46.225,30.55 46.44,30.55 47.915,29.075
  Top Layer w0.12: X2.2@51.7,28.75 51.9,28.75 52.4,28.25 C46.1@53.1,28.25
  Top Layer w0.15: 47.915,29.075 51.375,29.075 X2.2@51.7,28.75
PC15-OSC32_OUT: C45.1 U13.E1 X2.1 | length 9.2
  Top Layer w0.1: U13.E1@44.829,31.6 46.45,31.6 47.025,31.025 47.025,30.8 47.575,30.25 47.8,30.25
  Top Layer w0.12: X2.1@51.7,30.25 51.8,30.25 52.325,30.775 C45.1@53.1,30.775
  Top Layer w0.15: 47.8,30.25 X2.1@51.7,30.25
PH0-OSC_IN: C44.1 SB5.1 U13.H1 X1.1 | length 12.2
  Top Layer w0.1: U13.H1@44.829,33.1 45.129,33.4 46.975,33.4 47.175,33.6 47.975,33.6
  Top Layer w0.12: 47.975,33.6 48.22,33.355 51.8,33.355 52.5,32.655 X1.1@52.5,32.65
  Top Layer w0.15: C44.1@52.425,31.575 52.5,31.65 X1.1@52.5,32.65 v1(53.425,32.65)
  Bottom Layer w0.15: v1(53.425,32.65) SB5.1@55.325,32.65
PH1-OSC_OUT: C41.1 SB4.1 U13.J1 X1.3 | length 16.6
  Top Layer w0.1: U13.J1@44.829,33.6 46.525,33.6 46.925,34 47.975,34
  Top Layer w0.12: 47.975,34 48.275,34 48.55,33.725 51.175,33.725 X1.3@51.45,34 ; C41.1@51.525,35.075 51.525,35.7 52.15,36.325 55.95,36.325 56.875,35.4 v1(56.875,34.625)
  Top Layer w0.15: X1.3@51.45,34 51.45,35 C41.1@51.525,35.075
  Bottom Layer w0.1: v1(56.875,34.625) SB4.1@58,34.625
PH3-BOOT0: R35.2 U13.C5 | length 16.3
  Top Layer w0.08: U13.C5@42.829,30.6 v2(43.079,30.35)
  Top Layer w0.12: v2(44.925,21.175) 45.68,21.175 45.88,20.975 48.675,20.975 49,21.3 R35.2@50.7,21.3
  Signal Layer 1 w0.08: 43.079,25.925 v2(43.079,30.35)
  Signal Layer 1 w0.12: 43.079,25.925 43.079,25.127 43.07,25.118 43.07,24.73 44.55,23.25 44.55,21.55 v2(44.925,21.175)
PMOD#1: CN3.1 CN4.1 U4.16 | length 26.2
  Top Layer w0.12: v1(69.985,54.26) 70.25,54.525 U4.16@70.85,54.525
  Signal Layer 2 w0.12: v1(69.985,54.26) 71.525,55.8 CN3.1@71.525,61.325
  Bottom Layer w0.12: v1(69.985,54.26) 70.645,54.92 75.183,54.92 75.473,55.21 CN4.1@87.138,55.21
PMOD#2: CN3.2 CN4.2 U4.5 | length 22.2
  Top Layer w0.12: U4.5@73.2,54.525 73.7,54.525 73.8,54.425 v1(74.55,54.425)
  Signal Layer 2 w0.12: CN3.2@73.525,61.325 73.525,55.45 v1(74.55,54.425) ; v1(85.75,54.425) 85.75,54.058 CN4.2@87.138,52.67
  Bottom Layer w0.12: v1(74.55,54.425) v1(85.75,54.425)
PMOD#3: CN3.3 CN4.3 U4.8 | length 24.8
  Top Layer w0.12: U4.8@73.2,55.725 74.625,55.725 v1(75.325,56.425)
  Signal Layer 2 w0.12: v1(75.325,56.425) 75.325,58.41 75.525,58.61 CN3.3@75.525,61.325 ; v1(85.6,56.425) 85.345,56.17 85.345,52.355 85.475,52.225 85.475,51.793 CN4.3@87.138,50.13
  Bottom Layer w0.12: v1(75.325,56.425) v1(85.6,56.425)
PMOD#4: CN3.4 CN4.4 U4.13 | length 33.9
  Top Layer w0.12: v1(69.45,56.425) 70.15,55.725 U4.13@70.85,55.725
  Signal Layer 2 w0.12: v1(77.25,55.775) 77.25,56.84 76.992,57.098 76.992,58.182 77.525,58.715 CN3.4@77.525,61.325 ; v1(82.525,55.775) 82.525,51.357 82.065,50.897 82.065,48.415 82.805,47.675 v1(84,47.675)
  Bottom Layer w0.12: v1(69.45,56.425) 74.45,56.425 75.1,55.775 v1(77.25,55.775) v1(82.525,55.775) ; v1(84,47.675) 87.053,47.675 CN4.4@87.138,47.59
STLK_SWCLK: CN6.2 U32.A14 U34.1 | length 16.6
  Bottom Layer w0.1: 63.95,48.49 64.79,48.49 66.025,49.725 67.6,49.725 U32.A14@67.9,50.025
  Bottom Layer w0.12: CN6.2@56.025,42.605 57.993,42.605 U34.1@58,42.612 58,45.45 61.04,48.49 63.95,48.49
STLK_SWDIO: CN6.4 U32.A15 U33.1 | length 12.2
  Bottom Layer w0.1: 63.95,48.73 64.761,48.73 66.056,50.025 U32.A15@67.25,50.025
  Bottom Layer w0.12: CN6.4@56.025,47.685 57.973,47.685 U33.1@58,47.712 58.828,48.54 60.751,48.54 60.941,48.73 63.95,48.73
STLK_VCP_RX: R18.2 U32.C10 | length 21.6
  Top Layer w0.12: R18.2@60.925,37.75 60.925,38.882 61.528,39.485 62.79,39.485 v1(63.75,38.525)
  Signal Layer 2 w0.12: v1(63.75,38.525) 63.75,43.875 63.75,48.35 64.45,49.05 v1(66.025,49.05)
  Bottom Layer w0.1: v1(66.025,49.05) 70.175,49.05
  Bottom Layer w0.12: 70.175,49.05 U32.C10@70.5,48.725
STLK_VCP_TX: R19.1 U32.A7 | length 22.3
  Top Layer w0.12: R19.1@62.225,37.75 v1(63,37.75)
  Signal Layer 2 w0.12: v1(63,37.75) 63.225,37.975 63.225,49.175 64.575,50.525 v1(65.975,50.525)
  Bottom Layer w0.1: v1(65.975,50.525) 71.95,50.525 U32.A7@72.45,50.025
STMOD+1: CN2.1 U3.16 | length 24.1
  Top Layer w0.12: v1(34.2,57.275) 35.03,56.445 36.57,56.445 37.175,57.05 45.4,57.05 47.925,54.525 U3.16@52.25,54.525
  Signal Layer 2 w0.12: v1(34.2,57.275) 34.2,59.16 34.2,60.475 CN2.1@35.05,61.325
STMOD+2: CN2.2 U3.5 | length 29
  Top Layer w0.12: U3.5@54.6,54.525 55.15,54.525 55.625,54.05 v1(55.625,52.775)
  Signal Layer 2 w0.12: v1(46.875,52.075) v1(46.875,57.3)
  Bottom Layer w0.12: CN2.2@37.05,61.325 37.05,60.01 38.11,58.95 45.225,58.95 v1(46.875,57.3) ; v1(46.875,52.075) 54.925,52.075 v1(55.625,52.775)
STMOD+3: CN2.3 U3.8 | length 20.3
  Top Layer w0.12: v1(39.483,58.2) 53.575,58.2 54.6,57.175 U3.8@54.6,55.725
  Signal Layer 2 w0.12: CN2.3@39.05,61.325 39.05,58.633 v1(39.483,58.2)
STMOD+4: CN2.4 U3.13 | length 25.6
  Top Layer w0.1: CN2.4@41.05,61.325 42.05,62.325 42.05,64.1 v1(43.15,65.2)
  Top Layer w0.12: v1(48.2,56.3) 50.55,56.3 51.125,55.725 U3.13@52.25,55.725
  Signal Layer 2 w0.1: v1(50.027,65.178) 50.05,65.156 50.05,59.553
  Signal Layer 2 w0.12: v1(48.2,56.3) 50.05,58.15 50.05,59.553
  Bottom Layer w0.12: v1(43.15,65.2) 50.006,65.2 v1(50.027,65.178)
STMOD+.1_17: CN3.17 U13.A1 | length 76
  Top Layer w0.1: U13.A1@44.829,29.6 44.829,28.921 46.05,27.7 46.725,27.7 47.975,26.45
  Top Layer w0.12: 47.975,26.45 49.235,25.19 53.54,25.19 54.6,26.25 54.6,26.65 57.975,30.025 v1(57.975,30.425)
  Signal Layer 2 w0.1: 82.525,59.265 82.525,62.325 CN3.17@83.525,63.325
  Signal Layer 2 w0.12: v1(81.825,31.33) 81.825,50.85 80.985,51.69 80.985,57.3 82.525,58.84 82.525,59.265
  Bottom Layer w0.12: v1(57.975,30.425) 58.325,30.075 66.1,30.075 67.502,31.477 81.678,31.477 v1(81.825,31.33)
STMOD+.1_18: CN3.18 U13.B9 | length 150.1
  Top Layer w0.08: 39.955,25.925 39.955,27.68 40.579,28.304 40.579,29.85 U13.B9@40.829,30.1
  Top Layer w0.12: 39.955,25.925 39.955,24.22 v1(40.6,23.575)
  Signal Layer 2 w0.12: v1(18.075,65.25) 18.075,64.15 17.625,63.7 16.95,63.7 16.015,62.765 16.015,61.307 15.725,61.017 15.725,57.689 16.64,56.774 16.64,51.674 17.69,50.624 17.69,39.46 20.065,37.085 20.065,33.14 ; 20.065,34.179 20.065,33.14 ; v1(20.075,25.425) 20.07,25.43 20.07,33.135 20.065,33.14 ; CN3.18@85.525,63.325 v1(85.525,65.75)
  Bottom Layer w0.12: v1(18.075,65.25) 24.975,65.25 25.733,64.492 29.692,64.492 32.035,66.835 50.643,66.835 50.783,66.695 54.59,66.695 55.481,65.805 56.917,65.805 56.919,65.806 58.354,65.806 59.541,64.62 69.545,64.62 70.675,65.75 v1(85.525,65.75) ; v1(20.075,25.425) 20.575,24.925 25.123,24.925 26.18,23.868 26.18,22.445 27.175,21.45 29.489,21.45 30.19,22.151 30.19,23.906 31.359,25.075 36.638,25.075 37.63,24.083 38.008,23.705 38.544,23.705 38.824,23.985 40.19,23.985 v1(40.6,23.575)
STMOD+.1_19: CN3.19 U13.G4 | length 76.7
  Top Layer w0.08: U13.G4@43.329,32.6 v2(43.579,32.35)
  Top Layer w0.12: v2(53.125,31.65) 53.8,30.975 55.127,30.975 v1(55.452,30.65)
  Signal Layer 1 w0.08: v2(43.579,32.35) 43.579,32.204 43.943,31.84 46.64,31.84 47.3,32.5 47.595,32.5 48.445,31.65 v2(53.125,31.65)
  Signal Layer 2 w0.1: 86.525,59.275 86.525,62.325 CN3.19@87.525,63.325
  Signal Layer 2 w0.12: v1(84.5,31.735) 84.5,52.575 84.09,52.985 84.09,56.815 86.525,59.25 86.525,59.275
  Bottom Layer w0.12: v1(55.452,30.65) 57.325,30.65 57.505,30.83 59.345,30.83 59.86,30.315 65.965,30.315 67.385,31.735 v1(84.5,31.735)
STMOD+.1_20: CN3.20 U13.M12 | length 83.6
  Top Layer w0.08: 34.75,39 34.825,38.925 35.075,38.925 38.65,35.35 39.079,35.35 U13.M12@39.329,35.1
  Top Layer w0.12: v1(33.025,42.075) 33.025,40.775 33,40.75 34.75,39 ; v1(41.725,41.175) 41.725,41.825 42.325,42.425 43.325,42.425 43.97,43.07 44.545,43.07 44.875,43.4 46.625,43.4 47.55,44.325 49.05,44.325 49.555,44.83 49.555,47.97 49.515,48.01 v1(49.515,48.375)
  Signal Layer 2 w0.1: 88.525,59.225 88.525,62.325 CN3.20@89.525,63.325
  Signal Layer 2 w0.12: v1(84.975,51.93) 84.975,56.425 85.38,56.83 87.098,56.83 88.525,58.257 88.525,59.225
  Bottom Layer w0.1: 63.95,49.356 65.764,51.17 69.67,51.17 70.255,51.755 74.675,51.755 74.85,51.93 79.325,51.93
  Bottom Layer w0.12: v1(33.025,42.075) 33.025,42 33.275,41.75 40.875,41.75 41.45,41.175 v1(41.725,41.175) ; v1(49.515,48.375) 54.768,48.375 55.423,49.03 60.562,49.03 60.742,49.21 63.804,49.21 63.95,49.356 ; 79.325,51.93 v1(84.975,51.93)
STMOD+.1_ADC: CN3.13 U13.K4 | length 64.9
  Top Layer w0.08: U13.K4@43.329,34.1 v2(43.579,34.35)
  Top Layer w0.12: v2(45.677,40.352) 45.677,40.387 45.595,40.469 45.595,41.02 45.83,41.255 47.041,41.255 49.92,44.134 v1(49.92,51.03)
  Signal Layer 1 w0.08: v2(43.579,34.35) 43.829,34.6 43.829,35.1 43.829,35.746 43.574,36.001 43.574,36.899 43.674,36.999 43.674,37.699 44.975,39
  Signal Layer 1 w0.12: 44.975,39 45.677,39.702 v2(45.677,40.352)
  Signal Layer 2 w0.12: v1(49.92,51.03) 49.92,52.905 49.7,53.125 49.7,57.25 50.9,58.45 54.1,58.45 55.925,60.275 v1(55.925,66.86) ; CN3.13@75.525,63.325 v1(75.525,66.9)
  Bottom Layer w0.12: v1(55.925,66.86) 58.44,66.86 59.3,66 66.35,66 67.25,66.9 v1(75.525,66.9)
STMOD+.1_INT: CN3.11 CN4.7 U13.C2 | length 103.6
  Top Layer w0.08: U13.C2@44.329,30.6 44.579,30.35 45.025,30.35
  Top Layer w0.1: 45.025,30.35 46,29.375 46,28.7 46.65,28.05 48.2,28.05
  Top Layer w0.12: 48.2,28.05 48.205,28.055 51.845,28.055 52.088,27.812 52.09,27.815 54.99,27.815 v1(55.275,28.1)
  Signal Layer 2 w0.12: v1(55.275,28.1) 55.275,28.575 53.65,30.2 53.65,32.302 53.83,32.482 53.83,34.425 53.08,35.175 53.08,41.545 53.075,41.55 53.075,50.65 54.525,52.1 55.563,52.1 56.65,53.187 v1(56.65,66.45) ; CN3.11@71.525,63.325 v1(71.525,66.49) ; CN4.7@89.678,55.21 91.1,56.632 91.1,63.45 89.703,64.847 v1(89.703,66.49)
  Bottom Layer w0.12: v1(56.65,66.45) 58.45,66.45 59.425,65.475 66.339,65.475 67.354,66.49 v1(71.525,66.49) v1(89.703,66.49)
STMOD+.1_RST: CN3.12 CN4.8 U13.G8 | length 121.1
  Top Layer w0.08: v2(41.079,32.85) v3(41.329,32.6)
  Signal Layer 1 w0.08: v2(41.079,32.85) v3(41.329,32.6)
  Signal Layer 2 w0.08: 37.125,38.825 37,38.7 37,34.35 38.65,32.7 40.2,32.7 40.35,32.85 v2(41.079,32.85) v3(41.329,32.6)
  Signal Layer 2 w0.1: 37.125,38.825 37.125,39
  Signal Layer 2 w0.12: 37.125,39 37.125,39.425 36.745,39.805 36.745,44.595 37.195,45.045 37.195,55.835 38.6,57.24 v1(38.6,58.24) ; v1(54.875,60.165) v1(54.875,69.405) ; CN3.12@73.525,63.325 v1(73.525,69.375) ; CN4.8@89.678,52.67 91.525,54.517 91.525,63.4 90.125,64.8 v1(90.125,69.375)
  Bottom Layer w0.12: v1(38.6,58.24) 39.07,58.71 44.892,58.71 46.707,56.895 47.27,56.895 47.925,57.55 47.925,58.415 48.475,58.965 53.675,58.965 v1(54.875,60.165) ; v1(54.875,69.405) 56.345,69.405 59.5,66.25 65.95,66.25 69.105,69.405 69.135,69.375 v1(73.525,69.375) 73.555,69.375 73.565,69.365 73.575,69.375 v1(90.125,69.375)
STMOD+.1_SPI1_MISO_alt1: CN3.9 U13.J8 | length 99.2
  Top Layer w0.08: v2(41.079,33.85) U13.J8@41.329,33.6
  Top Layer w0.12: v1(33.875,65.85) 33.075,65.05 ; v1@33.9,65.875 33.075,65.05 ; v1(39.325,56.15) 33.9,56.15 33.075,56.975 33.075,65.05
  Signal Layer 1 w0.08: v2(41.079,33.85) v3(41.329,33.6)
  Signal Layer 2 w0.1: 40.015,39 40.015,36.81 41.329,35.496 v3(41.329,33.6)
  Signal Layer 2 w0.12: v1(39.325,56.15) 39.325,51.025 38.75,50.45 38.75,40.6 40.015,39.335 40.015,39
  Bottom Layer w0.1: 86.525,64.175 86.525,62.325 CN3.9@87.525,61.325
  Bottom Layer w0.12: v1(33.875,65.85) 34.38,66.355 50.444,66.355 50.584,66.215 54.356,66.215 55.246,65.325 57.948,65.325 59.236,64.038 59.337,64.038 59.34,64.035 69.785,64.035 70.525,64.775 85.925,64.775 86.525,64.175
STMOD+.1_SPI1_MOSI_alt1: CN3.8 U13.H11 | length 95.9
  Top Layer w0.08: v2(39.579,33.35) U13.H11@39.829,33.1
  Top Layer w0.12: v1(32.9,65.675) 32.575,65.35 32.575,56.725 33.73,55.57 v1(38.342,55.57)
  Signal Layer 1 w0.08: v3(39.077,33.35) v2(39.579,33.35)
  Signal Layer 2 w0.08: 37.85,38.75 38.1,38.5 38.1,37.4
  Signal Layer 2 w0.1: 38.1,37.4 38.1,34.327 v3(39.077,33.35)
  Signal Layer 2 w0.12: 37.85,38.75 37.85,49.425 37.715,49.56 37.715,54.943 v1(38.342,55.57)
  Bottom Layer w0.1: 84.525,63.825 84.525,62.325 CN3.8@85.525,61.325
  Bottom Layer w0.12: v1(32.9,65.675) 33.325,65.25 34.325,65.25 35.19,66.115 50.345,66.115 50.485,65.975 54.257,65.975 55.147,65.085 57.849,65.085 59.139,63.795 69.97,63.795 70.71,64.535 83.815,64.535 84.525,63.825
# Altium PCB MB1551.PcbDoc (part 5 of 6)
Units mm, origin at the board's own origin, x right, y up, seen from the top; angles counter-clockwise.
Board outline 100 x 70 mm, 6 copper layers (Top Layer, Signal Layer 1, Signal Layer 2, Signal Layer 3, Signal Layer 4, Bottom Layer), stack 1.49 mm thick; 325 components, 276 nets, 1540 pads, 1100 vias.

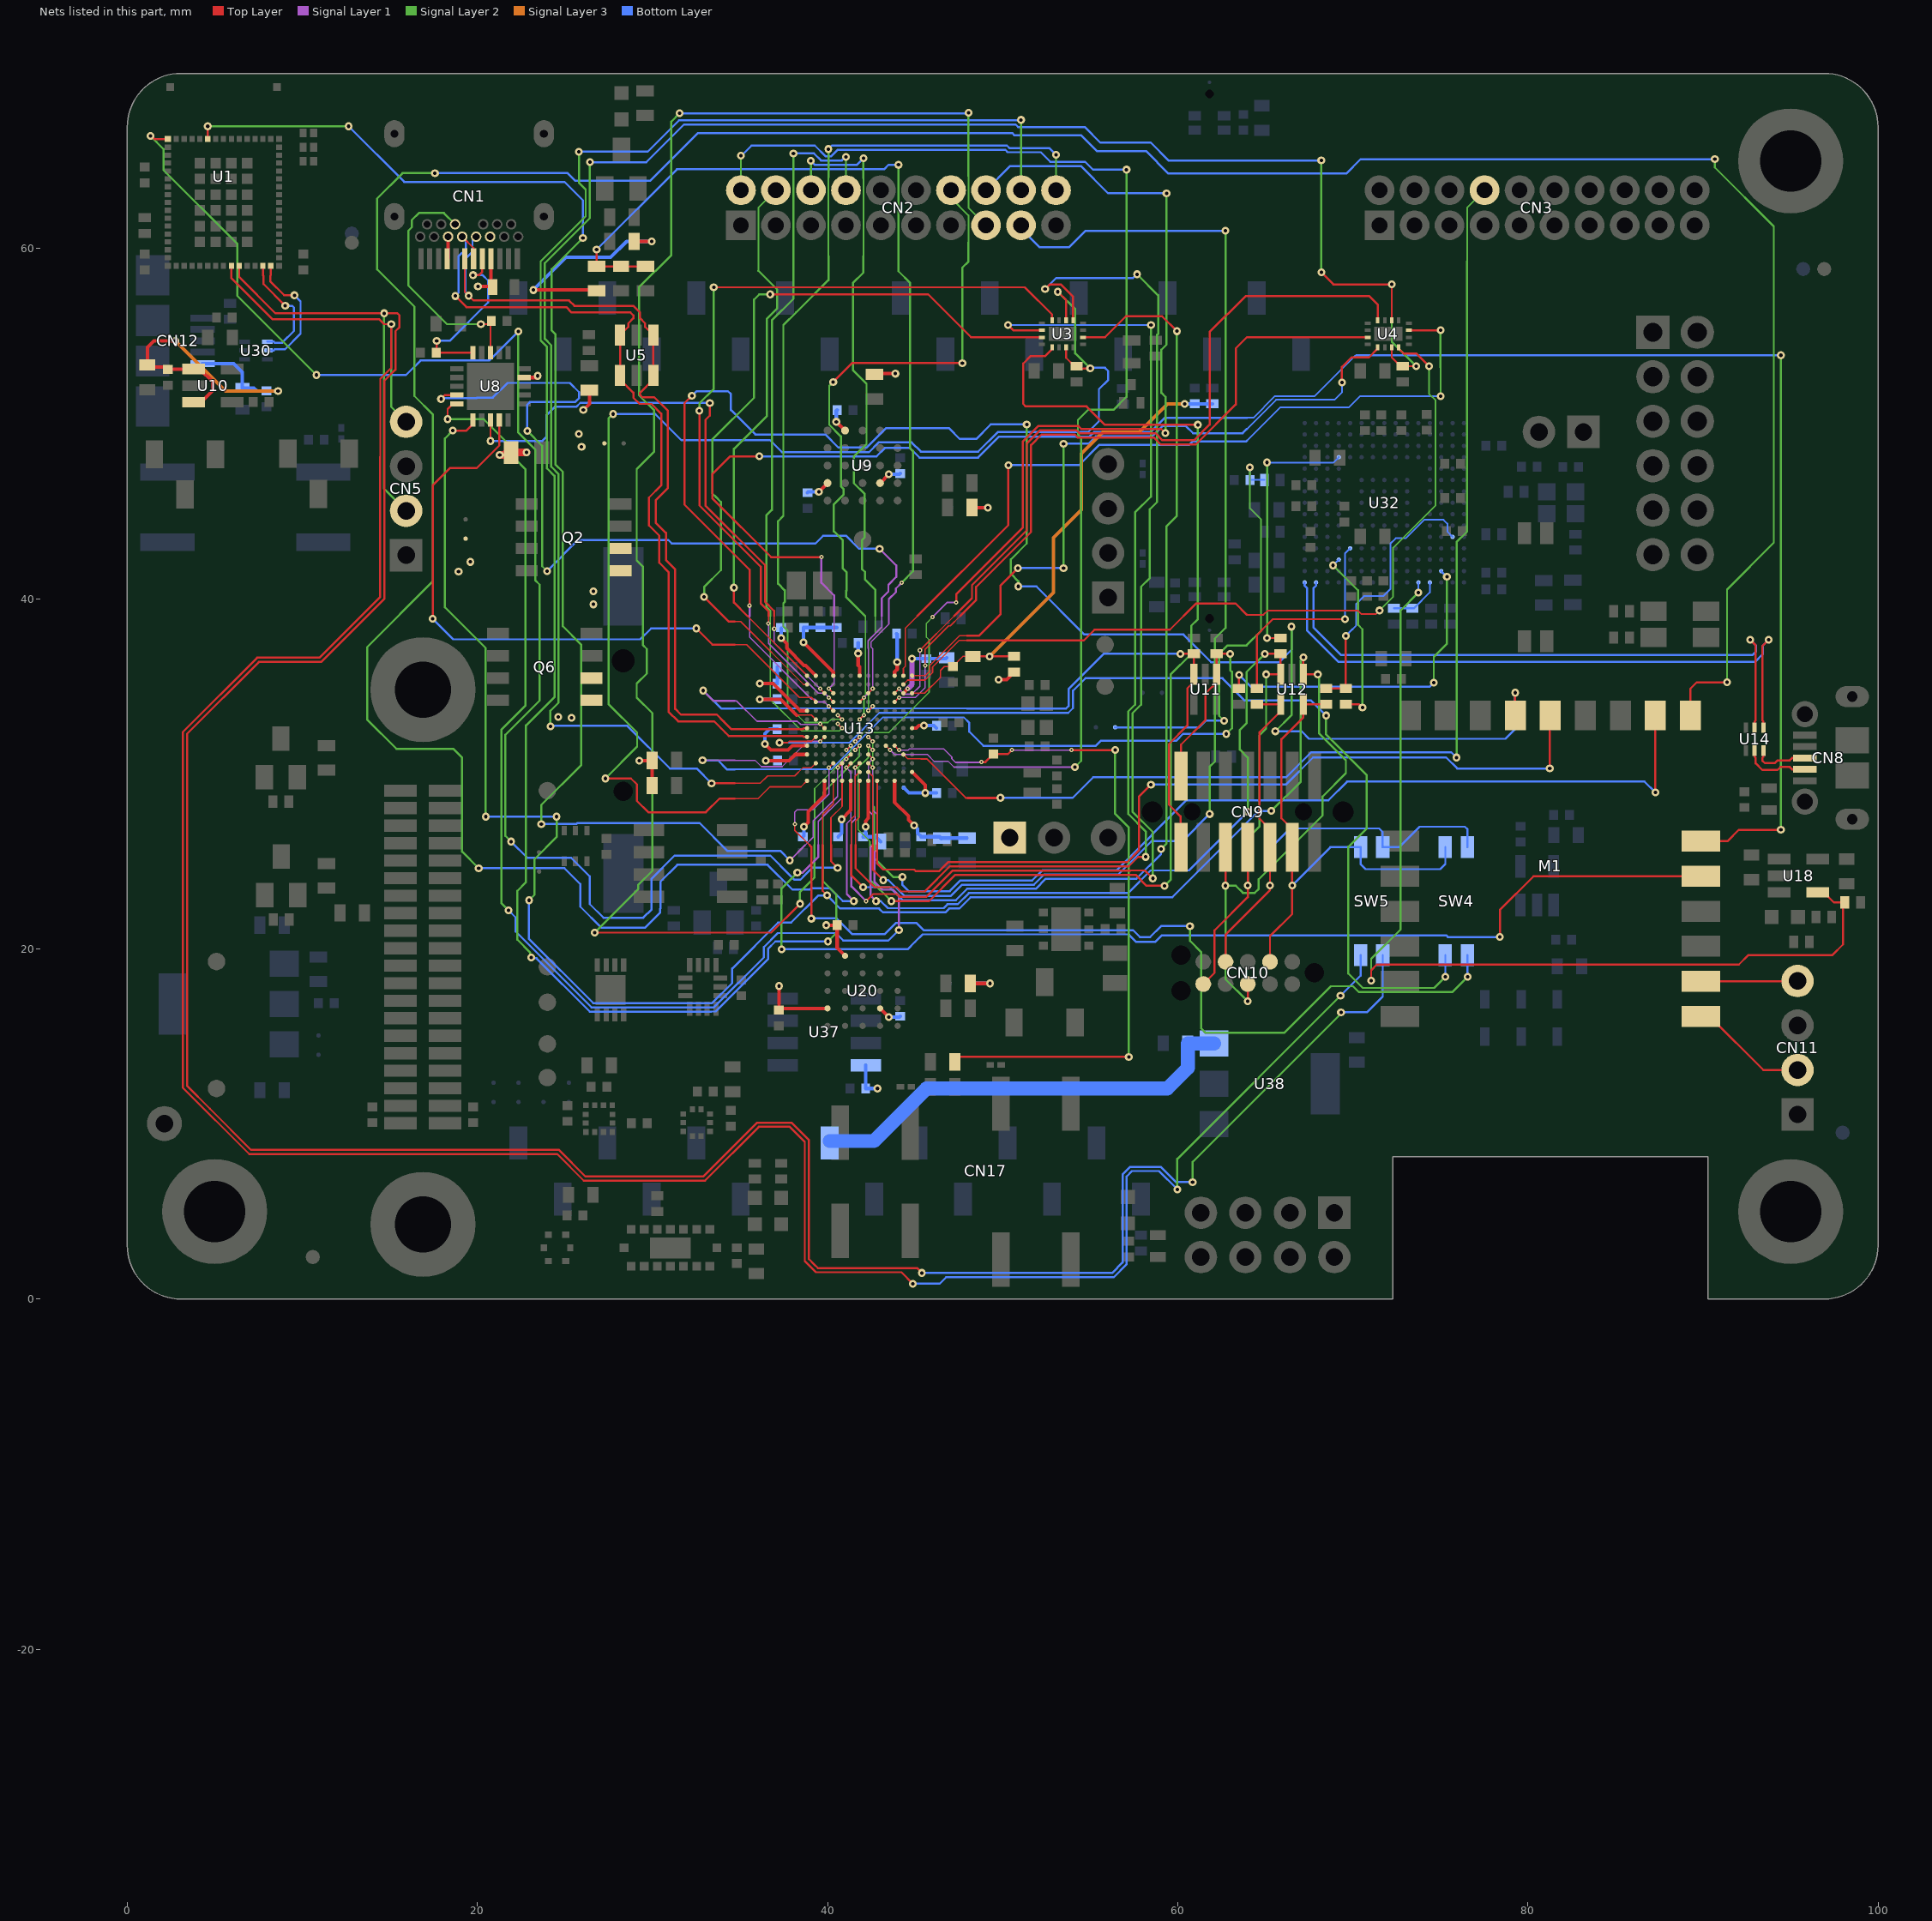
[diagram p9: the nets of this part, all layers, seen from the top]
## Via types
v1: diameter 0.45, hole 0.2, Top Layer to Bottom Layer, tented both sides, 922 vias
v2: diameter 0.25, hole 0.1, Top Layer to Signal Layer 1, tented top, 142 vias
v3: diameter 0.25, hole 0.1, Signal Layer 1 to Signal Layer 2, 36 vias

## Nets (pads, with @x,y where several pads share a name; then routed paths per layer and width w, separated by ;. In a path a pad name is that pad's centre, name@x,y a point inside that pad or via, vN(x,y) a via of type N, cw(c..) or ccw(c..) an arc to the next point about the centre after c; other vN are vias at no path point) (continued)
STMOD+.1_SPI1_NSS: U4.1 U13.N1 | length 40.9
  Top Layer w0.08: U13.N1@44.829,35.6 45.578,35.6 45.835,35.857 45.835,36.181 47.529,37.875 47.975,37.875
  Top Layer w0.12: 47.975,37.875 48.65,37.875 49.875,39.1 49.875,40.745 v1(50.875,41.745) ; v1(69.38,52.341) 69.38,53.23 69.925,53.775 70.925,53.775 71.425,54.275 U4.1@71.425,54.35
  Signal Layer 2 w0.12: v1(53.48,41.745) v1(53.48,48.845)
  Bottom Layer w0.1: 63.95,49.695 65.615,51.36 68.962,51.36 69.38,51.778 v1(69.38,52.341)
  Bottom Layer w0.12: v1(50.875,41.745) v1(53.48,41.745) ; v1(53.48,48.845) 54.899,48.845 55.324,49.27 58.545,49.27 58.686,49.411 59.13,49.855 60.47,49.855 60.875,49.45 63.705,49.45 63.95,49.695
STMOD+.1_TIM: CN3.14 U13.D2 | length 66.9
  Top Layer w0.08: U13.D2@44.329,31.1 44.579,30.85 45.334,30.85
  Top Layer w0.1: 45.334,30.85 45.663,30.85 47.888,28.625 47.975,28.625
  Top Layer w0.15: 47.975,28.625 v1(49.875,28.625)
  Signal Layer 2 w0.1: 76.525,59.265 76.525,62.325 CN3.14@77.525,63.325
  Signal Layer 2 w0.12: v1(75.925,30.925) 75.925,43.225 76.525,43.825 76.525,59.265
  Bottom Layer w0.12: v1(49.875,28.625) 54,28.625 55.175,29.8 66.2,29.8 67.625,31.225 75.625,31.225 v1(75.925,30.925)
STMOD+.1_UART2_CTS: U4.15 U13.K3 | length 42.6
  Top Layer w0.08: U13.K3@43.829,34.1 v2(44.079,34.35) ; v2(45.575,36.175) 45.575,37.1 46.92,38.445 47.009,38.445 47.564,39
  Top Layer w0.12: 47.564,39 48.49,39.926 48.49,40.676 51.625,43.811 51.625,48.771 52.224,49.37 54.126,49.37 54.289,49.208 58.63,49.208 59.033,48.805 61.03,48.805 63.315,51.09 63.315,54.29 63.95,54.925 U4.15@70.85,54.925
  Signal Layer 1 w0.08: v2(44.079,34.35) 45.017,34.35 45.575,34.908 v2(45.575,36.175)
STMOD+.1_UART2_RTS: U4.12 U13.L3 | length 46.5
  Top Layer w0.08: U13.L3@43.829,34.6 v2(44.079,34.85) ; v2(45.275,37.05) 47.225,39
  Top Layer w0.12: 47.225,39 48.25,40.025 48.25,40.775 51.385,43.91 51.385,48.871 52.124,49.61 54.226,49.61 54.388,49.448 58.73,49.448 59.132,49.045 60.931,49.045 61.825,49.939 61.825,55.225 63.875,57.275 70.95,57.275 71.425,56.8 U4.12@71.425,55.9
  Signal Layer 1 w0.08: v2(44.079,34.85) 44.388,34.541 44.815,34.541 45.275,35.001 v2(45.275,37.05)
STMOD+.1_UART2_RX: U4.7 U13.N2 | length 46.4
  Top Layer w0.08: U13.N2@44.329,35.6 44.329,36.029 44.45,36.15 44.45,38.325 45.125,39
  Top Layer w0.12: 45.125,39 50.325,44.2 v1(50.325,47.625) ; U4.7@73.2,55.325 v1(75.015,55.325)
  Signal Layer 2 w0.1: v1(75.015,51.565) 75.015,53.2
  Signal Layer 2 w0.12: 75.015,53.2 v1(75.015,55.325)
  Bottom Layer w0.1: 63.95,49.016 65.864,50.93 69.78,50.93 70.415,51.565 v1(75.015,51.565)
  Bottom Layer w0.12: v1(50.325,47.625) 54.358,47.625 55.523,48.79 60.661,48.79 60.841,48.97 63.904,48.97 63.95,49.016
STMOD+.1_UART2_TX: U4.4 U13.M2 | length 47.5
  Top Layer w0.08: U13.M2@44.329,35.1 44.579,35.35 45.575,35.35 46,35.775 46,36.1 47.515,37.615 47.975,37.615
  Top Layer w0.1: 63.95,39.075 64.9,39.075 65.15,39.325 70.275,39.325 70.475,39.125 71.325,39.125 v1(71.525,39.325)
  Top Layer w0.12: 47.975,37.615 54.64,37.615 55.25,38.225 59.554,38.225 61.054,39.725 63.3,39.725 63.95,39.075 ; U4.4@72.625,54.35 72.625,54.275 72.9,54 73.625,54 v1(74.35,53.275)
  Signal Layer 2 w0.1: v1(71.525,39.325) 72.305,40.105 72.305,42.905 74.725,45.325 74.725,51.325 74.35,51.7 v1@74.35,53.2
  Signal Layer 2 w0.12: v1@74.35,53.2 v1(74.35,53.275)
STMOD+.2_17: CN2.17 U13.H7 | length 39.8
  Top Layer w0.1: v3(41.829,33.1) v2(42.079,33.35)
  Top Layer w0.12: v1(40.325,52.375) 41.4,53.45 v1(47.7,53.45)
  Signal Layer 1 w0.08: v3(41.829,33.1) v2(42.079,33.35)
  Signal Layer 2 w0.08: v3(41.829,33.1) 42.079,33.35 42.079,34.371 42.164,34.456 42.164,38.986
  Signal Layer 2 w0.1: CN2.17@47.05,63.325 47.05,62.892 48.05,61.892 48.05,60.35
  Signal Layer 2 w0.12: v1(40.325,52.375) 40.095,52.145 40.095,49.932 40.76,49.267 40.76,46.413 40.905,46.268 40.905,45.932 40.362,45.389 40.362,43.843 40.875,43.33 40.875,41.725 41.08,41.52 41.08,40.457 41.073,40.45 41.073,40.077 42.15,39 ; v1(47.7,53.45) 47.7,58.9 48.05,59.25 48.05,60.35
STMOD+.2_18: CN2.18 U13.F7 | length 57.5
  Top Layer w0.08: v2(41.579,31.85) v3(41.829,32.1)
  Top Layer w0.12: v2(47.35,39.775) 47.35,40.25 51.145,44.045 51.145,48.97 52.025,49.85 54.325,49.85 54.487,49.688 59.062,49.688 v1(59.3,49.45)
  Signal Layer 1 w0.08: v2(41.579,31.85) v3(41.829,32.1) ; v3(46,38.95) v3@46.05,39
  Signal Layer 1 w0.1: v3@46.05,39 46.825,39.775 v2(47.35,39.775)
  Signal Layer 2 w0.08: v3(41.829,32.1) 42.079,32.35 43.5,32.35 45.8,34.65 45.8,37.65 45.65,37.8 45.65,38.6 v3(46,38.95)
  Signal Layer 2 w0.12: v1(59.3,49.45) 59.3,51.525 59.07,51.755 59.07,54.22 59.36,54.51 v1(59.36,63.15)
  Bottom Layer w0.12: CN2.18@49.05,63.325 50.43,64.705 54.47,64.705 56.025,63.15 ; 56.65,63.15 56.025,63.15 ; v1(59.36,63.15) 56.025,63.15
STMOD+.2_19: CN2.19 U13.E7 | length 112.3
  Top Layer w0.08: v2(41.579,31.35) v3(41.829,31.6)
  Signal Layer 1 w0.08: v2(41.579,31.35) v3(41.829,31.6)
  Signal Layer 2 w0.08: 39.74,25.925 39.74,28.915 41.829,31.004 v3(41.829,31.6)
  Signal Layer 2 w0.12: v1(23.075,19.5) 23.025,19.55 23.025,19.783 22.28,20.528 22.28,23.307 22.78,23.807 22.78,32.755 24.4,34.375 24.4,47.011 23.975,47.436 23.975,48.075 23.975,54.375 23.615,54.735 23.615,59.265 26.185,61.835 26.185,63.363 25.8,63.748 v1(25.8,65.525) ; 39.74,25.925 39.74,23.858 40.5,23.098 40.5,20.9 v1(40.025,20.425) ; CN2.19@51.05,63.325 v1(51.05,67.34)
  Bottom Layer w0.12: v1(23.075,19.5) 23.112,19.463 23.371,19.463 26.42,16.415 33.353,16.415 33.358,16.42 33.606,16.42 36.6,19.414 36.6,20 37.025,20.425 v1(40.025,20.425) ; v1(25.8,65.525) 29.725,65.525 31.515,67.315 v1@51.05,67.315
STMOD+.2_20: CN2.20 U13.H9 | length 52.9
  Top Layer w0.08: v2(40.579,33.35) v3(40.829,33.1)
  Signal Layer 1 w0.08: v2(40.579,33.35) v3(40.829,33.1)
  Signal Layer 2 w0.08: 38.05,33.575 38.7,32.925 40.025,32.925 40.2,33.1 v3(40.829,33.1)
  Signal Layer 2 w0.1: 37.475,39 37.475,38.425 37.71,38.19 37.71,33.915 38.05,33.575 ; 40.05,59.553 40.05,64.05
  Signal Layer 2 w0.12: 37.475,39 37.475,39.727 37.555,39.807 37.555,40.47 37.175,40.85 37.175,44.421 37.475,44.72 37.475,55.619 38.206,56.35 40.05,58.194 40.05,59.553 ; 40.05,64.05 v1(40.05,65.675) ; CN2.20@53.05,63.325 v1(53.05,65.35)
  Bottom Layer w0.12: v1(40.05,65.675) 40.25,65.875 50.245,65.875 50.385,65.735 52.665,65.735 v1(53.05,65.35)
STMOD+.2_ADC: CN2.13 U13.J6 | length 38.9
  Top Layer w0.08: v3(42.329,33.6) v2(42.579,33.85)
  Signal Layer 1 w0.08: v3(42.329,33.6) v2(42.579,33.85)
  Signal Layer 2 w0.08: v3(42.329,33.6) 42.329,37.608 42.72,37.998 42.72,39
  Signal Layer 2 w0.1: 42.05,59.553 42.05,64
  Signal Layer 2 w0.12: CN2.13@39.05,63.325 v1(39.05,65) ; 42.05,59.553 42.05,58.625 41.45,58.025 41.45,53.05 42.225,52.275 42.225,48.825 41.5,48.1 41.5,46.6 42.125,45.975 42.125,43.5 41.96,43.335 41.96,41.701 42.13,41.531 42.13,41.097 42.72,40.507 42.72,39 ; 42.05,64 v1(42.05,65.15)
  Bottom Layer w0.12: v1(39.05,65) 39.05,64.996 39.285,64.761 41.661,64.761 v1(42.05,65.15)
STMOD+.2_INT: CN2.11 U13.E4 | length 72.8
  Top Layer w0.08: U13.E4@43.329,31.6 v2(43.579,31.35)
  Signal Layer 1 w0.08: v2(43.579,31.35) 43.829,31.1 45.7,31.1 46.1,30.7 46.9,30.7 47.225,30.375 v1(54.125,30.375)
  Signal Layer 2 w0.12: CN2.11@35.05,63.325 v1(35.05,65.3) ; v1(54.125,30.375) 54.48,30.73 54.48,49.195 54.3,49.375 54.3,50.2 54.9,50.8 56.35,50.8 57.078,51.528 57.075,51.53 v1(57.075,64.5)
  Bottom Layer w0.12: v1(35.05,65.3) 35.085,65.3 35.66,65.875 39.277,65.875 39.882,65.27 40.218,65.27 40.583,65.635 50.146,65.635 50.286,65.495 52.18,65.495 52.73,64.945 54.715,64.945 55.16,64.5 v1(57.075,64.5)
STMOD+.2_RST: CN2.12 U13.N13 | length 31.3
  Top Layer w0.08: 35.429,39 U13.N13@38.829,35.6
  Top Layer w0.12: v1(34.65,40.625) 34.65,39.779 35.429,39
  Signal Layer 2 w0.1: 36.05,58.725 36.05,62.325 CN2.12@37.05,63.325
  Signal Layer 2 w0.12: v1(34.65,40.625) 34.65,48.55 36.54,50.44 36.54,55.99 37.13,56.58 37.13,57.645 36.05,58.725
STMOD+.2_SPI3_MISO: U3.9 U13.C7 | length 70.9
  Top Layer w0.08: v2(41.579,30.35) U13.C7@41.829,30.6
  Top Layer w0.12: v2(42.2,22.725) 42.605,23.13 43.945,23.13 44.1,22.975 45.65,22.975 47.145,24.47 57.299,24.47 57.304,24.475 58.125,24.475 v1(58.575,24.025) ; v1(52.425,57.675) 52.7,57.95 53.325,57.95 54.025,57.25 U3.9@54.025,55.9
  Signal Layer 1 w0.08: 41.36,25.925 41.36,27.185 41.579,27.404 v2(41.579,30.35)
  Signal Layer 1 w0.12: 41.36,25.925 41.36,23.565 v2(42.2,22.725)
  Signal Layer 2 w0.12: v1(57.675,58.525) 58.88,57.32 58.88,55.125 58.825,55.07 58.825,45.903 58.82,45.898 58.82,45.52 58.405,45.105 58.405,41.175 57.912,40.682 57.912,33.95 57.415,33.453 57.415,27.835 58.58,26.67 58.58,24.03 v1(58.575,24.025)
  Bottom Layer w0.12: v1(52.425,57.675) 53.055,58.305 57.44,58.305 57.655,58.52 57.67,58.52 v1(57.675,58.525)
STMOD+.2_SPI3_MISO_alt1: CN2.9 U13.B6 | length 75.1
  Top Layer w0.08: U13.B6@42.329,30.1 42.579,29.85 42.579,25.925
  Top Layer w0.12: 42.579,25.925 42.579,24.521 v1(43.175,23.925)
  Signal Layer 2 w0.12: v1(61.825,27.7) 61.825,30.4 62.125,30.7 62.125,37.725 62.725,38.325 v1(62.725,61.01)
  Bottom Layer w0.12: v1(43.175,23.925) 43.475,23.925 44.375,23.025 47.05,23.025 47.69,23.665 51.791,23.665 52.371,24.245 56.595,24.245 58.5,26.15 60.275,26.15 v1(61.825,27.7) ; CN2.9@51.05,61.325 51.05,61.125 51.608,60.567 52.1,60.075 53.8,60.075 54.735,61.01 ; 55.925,61.01 54.735,61.01 ; v1(62.725,61.01) 54.735,61.01
STMOD+.2_SPI3_MOSI: U3.6 U13.B7 | length 61.9
  Top Layer w0.08: 41.36,25.925 41.36,27.41 41.579,27.629 41.579,29.85 U13.B7@41.829,30.1
  Top Layer w0.12: 41.36,25.925 41.36,24.19 v1(42.025,23.525) ; U3.6@54.6,54.925 55.85,54.925 57.05,56.125 59.1,56.125 v1(59.95,55.275)
  Signal Layer 2 w0.12: v1(59.05,25.7) 59.35,26 59.35,44.125 59.95,44.725 v1(59.95,55.275)
  Bottom Layer w0.12: v1(42.025,23.525) 42.03,23.52 43.541,23.52 44.276,22.785 47.331,22.785 47.971,23.425 51.89,23.425 52.47,24.005 57.643,24.005 59.05,25.412 v1(59.05,25.7)
STMOD+.2_SPI3_MOSI_alt1: CN2.8 U13.E8 | length 97.4
  Top Layer w0.08: v2(41.079,31.35) v3(41.329,31.6)
  Top Layer w0.12: v1(26.7,20.925) 36.775,20.925 v1(38.425,22.575)
  Signal Layer 1 w0.08: v2(41.079,31.35) v3(41.329,31.6)
  Signal Layer 2 w0.08: 39.26,25.925 39.26,29.156 41.329,31.225 v3(41.329,31.6)
  Signal Layer 2 w0.1: 48.05,64.125 48.05,62.325 CN2.8@49.05,61.325
  Signal Layer 2 w0.12: v1(26.7,20.925) 29.175,23.4 29.175,23.639 30,24.464 30,33.45 29.1,34.35 29.1,35.15 29.675,35.725 29.675,37.125 29.445,37.355 29.445,41.83 29.1,42.175 29.1,47.4 30.1,48.4 30.1,50.75 29.23,51.62 29.23,57.78 31.075,59.625 31.075,67.245 v1(31.55,67.72) ; v1(38.425,22.575) 38.425,23.25 39.26,24.085 39.26,25.925 ; 48.05,64.125 v1(48.05,67.745)
  Bottom Layer w0.12: v1(31.55,67.72) v1@48.05,67.72
STMOD+.2_SPI3_NSS: U3.1 U13.E6 | length 69.1
  Top Layer w0.08: v3(42.329,31.6) v2(42.579,31.35)
  Top Layer w0.12: v1(43.65,22.725) 45.8,22.725 47.3,24.225 57.6,24.225 58.225,23.6 v1(59.25,23.6) ; U3.1@52.825,54.35 52.825,54.25 52.43,53.855 51.605,53.855 51.175,53.425 51.175,51.125 51.32,50.98 54.795,50.98 55.847,49.928 v1(61.147,49.928)
  Signal Layer 1 w0.08: v3(42.329,31.6) v2(42.579,31.35)
  Signal Layer 2 w0.08: v3(42.329,31.6) 42.329,30.929 41.75,30.35 41.75,26.8 42.425,26.125 42.425,25.925
  Signal Layer 2 w0.12: 42.425,25.925 42.425,25.128 42.43,25.123 42.43,23.945 v1(43.65,22.725) ; v1(59.25,23.6) 59.59,23.94 59.59,35.665 60.775,36.85 60.775,38.457 61.15,38.832 v1@61.15,49.928
STMOD+.2_SPI3_SCK: U3.14 U13.A7 | length 64.6
  Top Layer w0.08: 41.6,25.925 41.6,27.3 41.829,27.529 U13.A7@41.829,29.6 U13.A7@41.844,29.585
  Top Layer w0.12: 41.6,25.925 41.6,24.6 42.68,23.52 43.955,23.52 44.2,23.275 45.55,23.275 46.985,24.71 57.199,24.71 57.739,25.25 v1(58.175,25.25) ; v1(50.3,55.625) 50.6,55.325 U3.14@52.25,55.325
  Signal Layer 2 w0.12: v1(58.175,25.25) 58.175,26.7 57.175,27.7 57.175,33.552 57.565,33.942 57.565,44.915 58.475,45.825 v1(58.475,55.625)
  Bottom Layer w0.12: v1(50.3,55.625) v1(58.475,55.625)
STMOD+.2_TIM: CN2.14 U13.G9 | length 42.7
  Top Layer w0.08: v2(40.579,32.85) v3(40.829,32.6)
  Signal Layer 1 w0.08: v2(40.579,32.85) v3(40.829,32.6)
  Signal Layer 2 w0.08: 36.735,39 36.735,34.24 38.525,32.45 40.679,32.45 v3(40.829,32.6)
  Signal Layer 2 w0.1: 38.05,59.325 38.05,62.775 v1(38.05,65.425)
  Signal Layer 2 w0.12: 36.735,39 36.735,39.303 36.505,39.533 36.505,44.755 36.818,45.068 36.818,55.893 38.05,57.125 38.05,59.325 ; CN2.14@41.05,63.325 v1(41.05,65.225)
  Bottom Layer w0.12: v1(38.05,65.425) 39.225,65.425 39.625,65.025 40.815,65.025 41.015,65.225 v1(41.05,65.225)
STMOD+.2_UART3_CTS: U3.15 U13.M13 | length 44.1
  Top Layer w0.08: 34.7,38.687 35.038,38.687 38.625,35.1 U13.M13@38.829,35.1
  Top Layer w0.12: v1(32.95,40.1) 34.363,38.687 34.7,38.687 ; v1(36.725,57.375) 45.75,57.375 48.2,54.925 U3.15@52.25,54.925
  Signal Layer 2 w0.12: v1(32.95,40.1) 32.95,40.669 33.91,41.629 33.91,45.515 33.624,45.801 33.415,46.01 33.415,49.079 35.8,51.464 35.8,57.075 36.1,57.375 v1(36.725,57.375)
STMOD+.2_UART3_RTS: U3.12 U13.K10 | length 47.7
  Top Layer w0.08: v2(36.625,38.575) 36.625,39 ; v2(40.079,34.35) U13.K10@40.329,34.1
  Top Layer w0.12: v1(32.68,50.725) 32.68,45.331 36.185,41.826 36.185,39.726 36.625,39.286 36.625,39 ; v1(33.5,57.78) 51.27,57.78 52.825,56.225 U3.12@52.825,55.9
  Signal Layer 1 w0.08: v2(36.625,38.575) 36.625,37.45 39.475,34.6 39.829,34.6 v2(40.079,34.35)
  Signal Layer 2 w0.12: v1(32.68,50.725) 32.68,51.155 33.5,51.975 v1(33.5,57.78)
STMOD+.UART2_SPI1_SEL: R11.1 U4.3 U4.10 U13.C12 | length 115
  Top Layer w0.08: 34.7,29.455 36.155,29.455 36.575,29.875 38.125,29.875 38.6,30.35 39.079,30.35 U13.C12@39.329,30.6
  Top Layer w0.12: v1(33.375,29.45) 33.38,29.455 34.7,29.455 ; v1(68.205,58.63) 68.885,57.95 v1(72.225,57.95) U4.10@72.225,55.9 ; U4.3@72.225,54.35 72.225,53.775 72.725,53.275 R11.1@72.85,53.275 v1(73.625,53.275)
  Signal Layer 2 w0.12: v1(24.175,32.7) 24.175,33.6 24.64,34.065 24.64,47.11 24.215,47.535 ; 24.215,47.975 24.215,47.535 ; v1(26.425,64.925) 26.425,61.736 23.855,59.165 23.855,54.835 24.215,54.474 24.215,47.535 ; v1@68.2,58.635 v1(68.205,58.63) 68.205,65.02 v1(68.2,65.025) ; v1(72.225,57.95) 72.225,54.675 v1(73.625,53.275)
  Bottom Layer w0.12: v1(24.175,32.7) 24.205,32.73 28.57,32.73 31,30.3 32.525,30.3 v1(33.375,29.45) ; v1(26.425,64.925) 29.65,64.925 31.8,67.075 50.742,67.075 50.882,66.935 54.69,66.935 55.58,66.045 56.818,66.045 56.819,66.046 58.454,66.046 59.475,65.025 v1(68.2,65.025)
STMOD+.UART3_SPI3_SEL: R10.1 U3.3 U3.10 U13.A13 | length 79.2
  Top Layer w0.08: 34.7,28.58 36.03,28.58 36.7,29.25 38.479,29.25 U13.A13@38.829,29.6
  Top Layer w0.12: v1(27.306,29.73) 28.77,29.73 29.11,29.39 29.11,28.451 29.761,27.8 33.05,27.8 33.83,28.58 34.7,28.58 ; v1(53.15,57.525) 53.63,57.045 53.63,55.905 U3.10@53.625,55.9 ; U3.3@53.625,54.35 53.625,53.75 54.1,53.275 R10.1@54.225,53.275 54.35,53.15 v1(55,53.15)
  Signal Layer 2 w0.12: v1(27.306,29.73) 29.126,31.55 29.126,32.349 27.49,33.985 27.49,35.975 27.49,50.285 v1(27.75,50.545) ; v1(53.15,57.525) 54.15,56.525 54.15,54 v1(55,53.15)
  Bottom Layer w0.12: v1(27.75,50.545) 30.155,50.545 31.65,49.05 36.715,49.05 37.4,48.365 42.365,48.365 42.92,48.92 44.805,48.92 45.33,48.395 48.607,48.395 49.737,49.525 54.9,49.525 55.5,50.125 55.5,51.965 56.03,52.495 56.03,52.995 55.845,53.18 55.03,53.18 v1(55,53.15)
T.JTDI: CN9.10 CN10.8 U8.1 U12.1 U13.A10 | length 132.7
  Top Layer w0.08: 39.715,25.925 39.715,27.673 40.329,28.288 U13.A10@40.329,29.6
  Top Layer w0.12: v1(18.6,49.6) 19.375,49.6 19.75,49.975 U8.1@19.75,50.2 ; 39.715,25.925 39.715,23.31 v1(39.975,23.05) ; v1(62.73,23.605) CN9.10@62.73,25.793 ; v1(64,17) CN10.8@64,17.99 ; v1(67.175,36.65) U12.1@67.175,35.675 v1(68,35.675)
  Signal Layer 2 w0.12: v1(18.6,49.6) 18.15,49.15 18.15,39.5 20.475,37.175 v1(20.475,27.55) ; v1(22.95,22.775) 23.26,23.085 23.26,25.121 24.525,26.386 v1(24.525,27.55) ; v1(64,17) 62.73,18.27 v1(62.73,23.605) 63.32,23.605 63.725,23.2 64.4,23.2 64.625,23.425 64.625,23.975 68.275,27.625 ; v1(65.35,27.875) 67.025,29.55 67.025,36.5 v1(67.175,36.65) ; v1(68,35.675) 68.07,35.605 68.07,32.305 69.605,30.77 69.605,30.03 68.275,28.7 68.275,27.625 ; 68.275,28.49 68.275,27.625
  Bottom Layer w0.12: v1(20.475,27.55) v1(24.525,27.55) ; v1(22.95,22.775) 22.95,20.564 26.619,16.895 33.154,16.895 33.159,16.9 33.407,16.9 34.553,18.047 34.553,18.876 37.177,21.5 37.925,21.5 39.475,23.05 v1(39.975,23.05) 40.72,22.305 42.943,22.305 43.168,22.08 46.725,22.08 46.95,22.305 47.53,22.305 48.17,22.945 59.693,22.945 64.623,27.875 v1(65.35,27.875)
T.MCO: C81.1 R49.2 SB5.2 | length 24.4
  Signal Layer 2 w0.1: v1(64.125,47.5) 64.125,45.15 64.765,44.51 64.765,38.25
  Signal Layer 2 w0.12: v1(62.65,33.025) 62.37,33.305 62.37,36.845 62.85,37.325 63.925,37.325 64.765,38.165 64.765,38.25
  Bottom Layer w0.1: v1(64.125,47.5) C81.1@64.125,46.775 R49.2@64.95,46.775
  Bottom Layer w0.12: SB5.2@56.425,32.65 61.225,32.65 61.6,33.025 v1(62.65,33.025)
T.SWCLK: SW4.3 U13.C10 | length 57.9
  Top Layer w0.08: v2(38.129,27.129) 38.129,26.771 38.975,25.925 ; v2(40.079,30.35) U13.C10@40.329,30.6
  Top Layer w0.12: 38.975,25.925 39.075,25.825 v1(39.075,21.725)
  Signal Layer 1 w0.08: v2(38.129,27.129) 38.129,27.804 38.276,27.95 39.182,27.95 40.079,28.847 v2(40.079,30.35)
  Signal Layer 2 w0.12: v1(60.7,21.3) 60.7,20.452 61.35,19.802 61.35,15.45 61.6,15.2 66.08,15.2 68.744,17.864 70.011,17.864 70.35,17.525 75.675,17.525 v1(76.555,18.405)
  Bottom Layer w0.12: v1(39.075,21.725) 39.105,21.755 40.495,21.755 41.4,20.85 43.277,20.85 43.907,21.48 45.07,21.48 45.483,21.067 57.448,21.067 57.84,20.675 58.425,20.675 59.05,21.3 v1(60.7,21.3) ; v1(76.555,18.405) SW4.3@76.555,19.65
T.SWCLK_B: CN5.2 SW5.3 U1.26 | length 166.1
  Top Layer w0.12: U1.26@6.4,59 6.4,58.366 8.471,56.295 v1(14.675,56.295) 15.43,56.295 15.55,56.175 15.55,55.5 15.32,55.27 15.32,53.077 14.695,52.452 14.695,40.006 11.074,36.385 7.524,36.385 3.415,32.276 3.415,12.174 4.72,10.87 7.074,8.515 24.66,8.515 26.175,7 32.9,7 35.975,10.075 37.939,10.075 38.94,9.074 38.94,2.274 39.245,1.97 39.444,1.77 45.11,1.77 v1(45.39,1.49)
  Signal Layer 2 w0.12: v1(14.675,56.295) 14.675,46.272 CN5.2@15.928,45.02 ; v1(60.85,6.675) 60.85,7.825 69.325,16.3 v1(69.325,16.375)
  Bottom Layer w0.12: v1(45.39,1.49) 56.251,1.49 56.848,2.087 56.848,7.105 57.293,7.55 59.034,7.55 59.909,6.675 v1(60.85,6.675) ; v1(69.325,16.375) 70.808,16.375 71.71,17.277 SW5.3@71.71,19.65
T.SWCLKa: CN9.6 CN10.4 R23.1 SW4.2 SW5.2 U12.4 | length 34.2
  Top Layer w0.12: CN10.4@62.73,19.26 62.73,20.805 65.27,23.345 v1(65.27,23.625) CN9.6@65.27,25.793 65.27,26.83 64.675,27.425 64.675,32.375 65.875,33.575 U12.4@65.875,33.975 R23.1@64.525,33.975
  Bottom Layer w0.12: v1(65.27,23.625) 65.27,25.72 66.425,26.875 71.5,26.875 71.7,26.675 71.7,25.81 SW5.2@71.71,25.8 72.65,25.8 73.825,26.975 76.4,26.975 76.555,26.82 SW4.2@76.555,25.8
T.SWDIO: SW4.4 U13.F12 | length 59.9
  Top Layer w0.08: v1(37.25,31.775) 37.725,31.775 37.8,31.85 39.079,31.85 U13.F12@39.329,32.1
  Signal Layer 2 w0.12: v1(68.475,33.325) 68.475,32.239 70.8,29.914 70.8,26.875 69.75,25.825 69.75,18.589 70.574,17.765 74.645,17.765 v1(75.285,18.405)
  Bottom Layer w0.1: v1(37.25,31.775) 41.25,31.775 42.95,33.475 47.975,33.475
  Bottom Layer w0.12: 47.975,33.475 53.75,33.475 54.02,33.745 54.02,34.745 54.725,35.45 62.555,35.45 63.825,34.18 67.62,34.18 v1(68.475,33.325) ; v1(75.285,18.405) SW4.4@75.285,19.65
T.SWDIO_B: CN5.4 SW5.4 U1.25 | length 159.2
  Top Layer w0.12: U1.25@5.95,59 5.95,58.3 8.287,55.962 14.388,55.962 14.675,55.675 v1(15.08,55.675) 15.08,53.176 14.455,52.551 14.455,48.097 14.453,48.095 14.453,40.103 10.975,36.625 7.425,36.625 3.175,32.375 3.175,12.075 6.975,8.275 24.561,8.275 26.076,6.76 32.999,6.76 36.074,9.835 37.84,9.835 38.7,8.975 38.7,2.175 39.345,1.53 44.22,1.53 v1(44.875,0.875)
  Signal Layer 2 w0.12: v1(15.08,55.675) 15.08,50.947 CN5.4@15.928,50.1 ; v1(59.975,6.25) 59.975,8 v1(69.3,17.325)
  Bottom Layer w0.12: v1(44.875,0.875) 46.4,0.875 46.775,1.25 56.35,1.25 57.088,1.987 57.088,7.005 57.392,7.31 58.935,7.31 59.975,6.27 v1(59.975,6.25) ; v1(69.3,17.325) 70.44,18.465 SW5.4@70.44,19.65
T.SWDIOa: CN9.4 CN10.2 R24.1 SW4.1 SW5.1 U12.5 | length 29.1
  Top Layer w0.12: CN10.2@65.27,19.26 65.27,20.72 66.54,21.99 v1(66.54,23.625) CN9.4@66.54,25.793 66.54,26.835 65.925,27.45 65.925,31.975 67.175,33.225 U12.5@67.175,33.975 R24.1@68.475,33.975
  Bottom Layer w0.12: v1(66.54,23.625) 68.715,25.8 SW5.1@70.44,25.8 70.44,24.835 70.725,24.55 75,24.55 75.285,24.835 SW4.1@75.285,25.8
T.SWO: CN9.8 CN10.6 R20.1 U12.3 U13.D6 | length 66.6
  Top Layer w0.08: U13.D6@42.329,31.1 v2(42.579,30.85)
  Top Layer w0.12: CN10.6@61.46,17.99 62.1,18.63 62.1,21.05 64,22.95 v1(64,23.625) CN9.8@64,25.793 ; v1(64.975,36.85) R20.1@65.875,36.85 U12.3@65.875,35.675 v1(65.05,35.675)
  Signal Layer 1 w0.08: 42.579,25.925 42.579,27.646 42.329,27.896 42.329,30.6 v2(42.579,30.85)
  Signal Layer 1 w0.12: 42.579,25.925 42.45,25.796 42.45,23.05 v1(42.775,22.725)
  Signal Layer 2 w0.12: v1(64,23.625) 64,26.325 64.675,27 64.675,32.2 65.05,32.575 v1(65.05,35.675) ; v1(64,27.825) 64,30.925 63.55,31.375 63.55,32.5 63.925,32.875 63.925,35.8 v1(64.975,36.85)
  Bottom Layer w0.12: v1(42.775,22.725) 43.037,22.725 43.442,22.32 46.626,22.32 46.851,22.545 47.431,22.545 48.071,23.185 57.162,23.185 58.452,24.475 60.65,24.475 v1(64,27.825)
T.VCP_RX: CN9.13 R19.2 U11.1 U13.F11 | length 53.8
  Top Layer w0.08: v2(39.579,31.85) U13.F11@39.829,32.1
  Top Layer w0.12: CN9.13@60.19,29.857 60.19,31.665 61.575,33.05 61.575,34.575 62.225,35.225 U11.1@62.225,35.675 R19.2@62.225,36.85 v1(63,36.85)
  Signal Layer 1 w0.08: 34.7,30.765 35.86,30.765 36.225,30.4 37.4,30.4 38.85,31.85 v2(39.579,31.85)
  Signal Layer 1 w0.1: v1(32.86,30.765) 34.7,30.765
  Signal Layer 2 w0.12: v1(62.775,32.275) 63.095,32.595 63.095,35.818 63,35.913 v1(63,36.85)
  Bottom Layer w0.1: 34.7,30.25 40.2,30.25 43.175,33.225 47.775,33.225 47.975,33.025
  Bottom Layer w0.12: v1(32.86,30.765) 32.87,30.755 33.745,30.755 34.25,30.25 34.7,30.25 ; 47.975,33.025 48.1,32.9 48.1,32.4 48.9,31.6 55.325,31.6 55.6,31.875 59.9,31.875 60.3,32.275 v1(62.775,32.275)
T.VCP_TX: CN9.14 R18.1 U11.3 U13.G11 | length 50.1
  Top Layer w0.08: v2(39.579,32.85) U13.G11@39.829,32.6
  Top Layer w0.12: v1(60.15,36.85) R18.1@60.925,36.85 U11.3@60.925,35.675 60.925,35.25 60.545,34.87 60.545,32.745 59.5,31.7 59.5,28.225 60.16,27.565 60.16,25.823 CN9.14@60.19,25.793
  Signal Layer 1 w0.08: 34.7,34.162 34.801,34.162 35.963,33 38.275,33 38.465,32.81 39.539,32.81 v2(39.579,32.85)
  Signal Layer 1 w0.12: v1(32.9,34.75) 33.487,34.162 34.7,34.162
  Bottom Layer w0.1: 34.7,33.725 47.975,33.725
  Bottom Layer w0.12: v1(32.9,34.75) 33.925,33.725 34.7,33.725 ; 47.975,33.725 53.625,33.725 53.78,33.88 53.78,34.855 55.775,36.85 v1(60.15,36.85)
T_NRSTa: R22.2 U32.P3 | length 19.1
  Top Layer w0.12: R22.2@63.5,34.875 v1(63.5,35.65)
  Signal Layer 2 w0.12: v1(74.625,35.2) 74.625,36.675 75.375,37.425 75.375,38.25 v1(75.375,41.25)
  Bottom Layer w0.12: v1(63.5,35.65) 64.175,34.975 74.4,34.975 v1(74.625,35.2) ; U32.P3@75.05,41.575 v1(75.375,41.25)
T_PWR_EN: R31.2 U18.4 U32.R5 | length 56.1
  Top Layer w0.12: v1(71.05,18.175) 71.05,18.775 71.375,19.1 92.05,19.1 92.6,19.65 97.4,19.65 98,20.25 98,22.65 97.475,22.65 96.9,23.225 U18.4@96.55,23.225
  Signal Layer 2 w0.12: v1(71.05,18.175) 71.05,19.425 72.725,21.1 72.725,38.25 72.725,39.325 v1(73.75,40.35)
  Bottom Layer w0.1: v1(73.75,40.35) U32.R5@73.75,40.925
T_PWR_EXT: R56.2 R57.2 U32.R4 | length 3
  Bottom Layer w0.1: R57.2@72.35,39.45 73.425,39.45 73.5,39.45 74.4,40.35 U32.R4@74.4,40.925
T_SWCLKa: R23.2 U32.M11 | length 12.6
  Top Layer w0.1: 64.85,38.25 65.425,38.825 v1(69.55,38.825)
  Top Layer w0.12: R23.2@64.525,34.875 64.525,37.925 64.85,38.25
  Bottom Layer w0.1: v1(69.55,38.825) 69.55,42.575 U32.M11@69.85,42.875
T_SWDIO_IN: R25.2 U32.N12 | length 10.3
  Top Layer w0.12: R25.2@69.6,33.975 70.35,33.975 v1(70.55,33.775)
  Signal Layer 2 w0.12: v1(68.875,41.9) 70.3,40.475 70.3,38.5 70.55,38.25 v1(70.55,33.775)
  Bottom Layer w0.12: v1(68.875,41.9) U32.N12@69.2,42.225
T_SWDIOa: R24.2 R25.1 U32.L2 | length 15.9
  Top Layer w0.12: R24.2@68.475,34.875 R25.1@69.6,34.875 v1(69.6,37.875)
  Bottom Layer w0.1: 69.975,38.25 70.2,38.475 70.2,39.7 70.65,40.15 71.75,40.15 72.15,40.55 72.15,43.15 72.45,43.45 73.025,43.45 74.075,44.5 75.175,44.5 75.4,44.275 75.4,43.825 U32.L2@75.7,43.525
  Bottom Layer w0.12: v1(69.6,37.875) 69.975,38.25
T_SWOa: R20.2 U32.D12 | length 15
  Top Layer w0.12: v1(65.1,37.75) R20.2@65.875,37.75
  Signal Layer 2 w0.12: v1(65.1,37.75) v1(65.1,47.775)
  Bottom Layer w0.1: v1(65.1,47.775) 68.9,47.775 U32.D12@69.2,48.075
UCPD_CC1_C: C121.2 CN1.A5 U8.15 | length 10.2
  Top Layer w0.12: v1(17.675,54.725) 17.675,54.05 U8.15@19.75,54.05 ; v1(19.755,58.475) 20.088,58.475 20.28,58.667 CN1.A5@20.28,59.42
  Bottom Layer w0.12: v1(17.675,54.725) 18.425,54.725 20.615,56.915 20.615,58.16 20.3,58.475 v1(19.755,58.475)
UCPD_CC2_C: C120.2 CN1.B5 U8.13 | length 14
  Top Layer w0.12: v1(20.2,55.675) 20.725,55.675 20.75,55.7 U8.13@20.75,54.05
  Signal Layer 2 w0.12: CN1.B5@18.73,61.38 18.085,62.025 16.66,62.025 16.255,61.62 16.255,61.208 16.05,61.003 16.05,57.889 18.264,55.675 v1(20.2,55.675)
UCPD_PWR: U8.20 U13.C6 | length 71.3
  Top Layer w0.08: U13.C6@42.329,30.6 v2(42.579,30.35)
  Top Layer w0.12: v1@18.3,50.275 18.3,50.825 18.6,51.125 U8.20@18.825,51.125
  Signal Layer 1 w0.08: v2(42.579,30.35) 42.579,27.921 42.819,27.681 42.819,25.925
  Signal Layer 1 w0.12: 42.819,25.925 42.819,25.654 42.69,25.525 42.69,23.81 43.125,23.375 43.75,23.375 44.075,23.05 v1(44.075,21.075)
  Signal Layer 2 w0.12: v1(18.3,50.25) 20.362,50.25 22.155,48.457 22.155,47.98 22.737,47.398 22.737,33.887 21.365,32.515 21.365,22.61 v1(21.775,22.2)
  Bottom Layer w0.12: v1(21.775,22.2) 22.18,21.795 22.18,20.994 26.519,16.655 33.253,16.655 33.258,16.66 33.506,16.66 36.36,19.514 36.36,20.099 37.161,20.9 39.098,20.9 40.475,20.9 40.9,20.475 43.475,20.475 v1(44.075,21.075)
UCPD_SINK: Q6.5 Q6.6 SB15.1
  other v1: 25.375,33.2 24.625,33.25 18.925,41.55 19.6,42.1
UCPD_SOURCE: Q2.5 Q2.6 SB16.1
  other v1: 26.625,39.675 26.625,40.425 25.95,48.675 25.8,49.4
USB.C_N: CN1.A7 CN1.B7 U5.1 U5.6 U13.G13 | length 49.2
  Top Layer w0.12: CN1.A7@19.28,59.42 19.28,57.525 v1(19.505,57.3) 19.78,57.025 25.235,57.025 25.541,56.719 28.904,56.719 29.29,56.332 29.29,56.015 29.58,55.725 29.58,55.52 U5.1@30.05,55.05 U5.6@30.05,52.75 30.05,52.525 29.29,51.765 29.29,51.635 29.425,51.5 30.1,51.5 30.88,50.72 30.88,46.312 30.18,45.612 30.18,44.338 30.768,43.751 30.768,42.208 31.3,41.675 31.3,33.7 31.625,33.375 33.675,33.375 34.075,32.975 34.51,32.54 38.584,32.54 38.644,32.6 U13.G13@38.829,32.6
  Bottom Layer w0.12: v1(19.505,57.3) 19.31,57.495 19.31,59.405 19.72,59.815 19.72,60.46 CN1.B7@19.93,60.67
USB.C_P: CN1.A6 CN1.B6 U5.3 U5.4 U13.F13 | length 49.5
  Top Layer w0.12: v1(18.738,57.283) 19.375,56.645 25.078,56.645 25.384,56.339 28.746,56.339 28.91,56.175 28.91,56.015 28.62,55.725 28.62,55.52 U5.3@28.15,55.05 U5.4@28.15,52.75 28.15,52.525 28.91,51.765 28.91,51.477 29.267,51.12 29.942,51.12 30.5,50.562 30.5,46.469 29.8,45.769 29.8,44.181 30.388,43.593 30.388,42.05 30.92,41.518 30.92,33.543 31.468,32.995 33.518,32.995 33.918,32.595 ; CN1.B6@19.13,60.67 19.78,60.02 CN1.A6@19.78,59.42 ; 33.918,32.595 34.155,32.358 34.353,32.16 38.584,32.16 38.644,32.1 U13.F13@38.829,32.1
  Bottom Layer w0.12: v1(18.738,57.283) 18.93,57.475 18.93,59.562 19.34,59.972 19.34,60.46 CN1.B6@19.13,60.67
USB.IANA: U8.4 U13.K12 | length 38.2
  Top Layer w0.08: 34.7,37.375 35.375,37.375 38.4,34.35 38.933,34.35 39.079,34.35 U13.K12@39.329,34.1
  Top Layer w0.12: v1(17.45,38.85) 17.45,46.475 18.425,47.45 19.952,47.45 21.25,48.748 U8.4@21.25,50.2 ; v1(32.5,38.3) 33.425,37.375 34.7,37.375
  Bottom Layer w0.12: v1(17.45,38.85) 18.625,37.675 29.3,37.675 29.925,38.3 v1(32.5,38.3)
USB.UCPD_CC2: U8.3 U13.L11 | length 34.9
  Top Layer w0.08: v2(36.95,38.275) 36.95,39 ; v2(39.579,34.85) U13.L11@39.829,34.6
  Top Layer w0.12: v1(20.75,49) U8.3@20.75,50.2 ; v1(33.275,51.175) 33.275,50.45 33.025,50.2 33.025,45.325 36.425,41.925 36.425,39.825 36.95,39.3 36.95,39
  Signal Layer 1 w0.08: v2(36.95,38.275) 36.95,37.479 v2(39.579,34.85)
  Bottom Layer w0.12: v1(20.75,49) 20.758,48.992 23.692,48.992 23.95,49.25 23.95,49.322 23.955,49.327 23.955,50.48 24.425,50.95 25.65,50.95 25.88,51.18 26.218,51.18 26.223,51.175 v1(33.275,51.175)
USB.UCPD_FLT: U8.19 U13.K7 | length 54
  Top Layer w0.1: U13.K7@41.829,34.1 v2(42.079,34.35)
  Top Layer w0.12: v1(17.925,51.4) 18.15,51.625 U8.19@18.825,51.625
  Signal Layer 1 w0.08: v2(42.079,34.35) 42.329,34.6 42.329,37.151 42.314,37.166 42.314,37.593 43.095,38.373 43.095,39
  Signal Layer 1 w0.12: v1(42.975,42.85) 43.925,41.9 43.925,41.24 43.475,40.79 43.475,40.405 43.095,40.025 43.095,39
  Signal Layer 2 w0.12: v1(22.85,49.575) 23.7,48.725 23.7,41.85 v1(23.975,41.575)
  Bottom Layer w0.12: v1(17.925,51.4) 17.98,51.455 19.955,51.455 19.975,51.475 ; 20.525,51.475 19.975,51.475 ; v1(22.85,49.575) 22.845,49.58 22.845,51.07 22.995,51.22 25.581,51.22 ; v1(23.975,41.575) 25.75,43.35 30.9,43.35 31.1,43.15 39.309,43.15 39.739,43.58 41.068,43.58 41.798,42.85 v1(42.975,42.85) ; 25.75,51.389 25.581,51.22 ; 19.975,51.475 19.979,51.479 20.879,51.479 21.72,52.32 25.278,52.32 25.805,51.793 25.805,51.444 25.581,51.22
USB.VBUS_SENSE: C4.2 R5.1 R6.2 U13.L6 | length 54.7
  Top Layer w0.1: U13.L6@42.329,34.6 v2(42.579,34.85)
  Top Layer w0.12: v1(26.81,59.935) 26.81,58.981 R5.1@26.804,58.975 C4.2@28.204,58.975 R6.2@29.604,58.975
  Signal Layer 1 w0.08: v2(42.579,34.85) 42.579,37.135 42.479,37.234 42.479,37.524 43.5,38.545 43.5,39
  Signal Layer 1 w0.12: 43.5,39 43.5,39.97 43.905,40.375 43.905,40.58 v3(44.225,40.9)
  Signal Layer 2 w0.1: 44.05,59.553 44.05,63.9
  Signal Layer 2 w0.12: 44.05,59.553 44.05,58.7 44.72,58.03 44.72,48.588 44.88,48.428 44.88,41.555 v3(44.225,40.9) ; 44.05,63.9 v1(44.05,64.775)
  Bottom Layer w0.12: v1(26.81,59.935) 31.396,64.521 43.236,64.521 43.49,64.775 v1(44.05,64.775)
USB_DEV_HS_CN_N: CN8.2 U14.5 | length 3.9
  Top Layer w0.12: U14.5@92.95,31.325 92.95,30.965 93.01,30.905 93.01,30.593 93.383,30.22 94.257,30.22 94.422,30.385 94.955,30.385 95.09,30.25 CN8.2@95.825,30.25
USB_DEV_HS_CN_P: CN8.3 U14.6 | length 3.2
  Top Layer w0.12: U14.6@93.45,31.325 93.45,30.965 93.39,30.905 93.39,30.75 93.54,30.6 94.1,30.6 94.265,30.765 94.955,30.765 95.09,30.9 CN8.3@95.825,30.9
USB_DEV_HS_N: U14.2 U32.R14 | length 34.6
  Top Layer w0.12: v1(92.7,37.65) 93.01,37.34 93.01,33.045 92.95,32.985 U14.2@92.95,32.625
  Bottom Layer w0.12: U32.R14@67.9,40.925 67.9,40.74 67.765,40.605 67.765,38.339 69.329,36.775 92.825,36.775 93.035,36.985 93.035,37.315 v1(92.7,37.65)
USB_DEV_HS_P: U14.1 U32.R15 | length 35.9
  Top Layer w0.12: U14.1@93.45,32.625 93.45,32.985 93.39,33.045 93.39,37.29 v1(93.75,37.65)
  Bottom Layer w0.12: U32.R15@67.25,40.925 67.25,40.74 67.385,40.605 67.385,38.181 69.171,36.395 92.982,36.395 93.415,36.828 93.415,37.315 v1(93.75,37.65)
USB_DM: U1.30 U30.2 | length 7.2
  Top Layer w0.12: U1.30@8.2,59 8.2,58.465 8.165,58.43 8.165,58.125 8.965,57.325 v1(9.55,57.325)
  Bottom Layer w0.12: U30.2@8,54.175 8.36,54.175 8.42,54.235 9.007,54.235 9.9,55.128 9.9,56.975 v1(9.55,57.325)
USB_DP: U1.29 U30.1 | length 6.5
  Top Layer w0.12: U1.29@7.75,59 7.75,58.465 7.785,58.43 7.785,57.968 v1(9.028,56.725) v1@9.053,56.7
  Bottom Layer w0.12: U30.1@8,54.675 8.36,54.675 8.42,54.615 8.85,54.615 9.52,55.285 9.52,56.63 9.425,56.725 v1(9.028,56.725)
USER_Button: C43.2 R39.1 U13.E3 | length 41.3
  Top Layer w0.08: U13.E3@43.829,31.6 v2(44.079,31.35)
  Top Layer w0.12: R39.1@47.275,13.55 47.55,13.825 v1(57.205,13.825) ; v2(48.79,30.665) 49.015,30.665 C43.2@49.475,31.125 50.3,31.125 v2(50.525,31.35) ; v2(53.925,31.35) v1(56.425,31.35)
  Signal Layer 1 w0.08: v2(44.079,31.35) 44.603,31.35 44.663,31.41 46.64,31.41 47.1,30.95 47.1,30.855 47.305,30.65 48.775,30.65 v2(48.79,30.665) ; v2(50.525,31.35) v2(53.925,31.35)
  Signal Layer 2 w0.12: v1(56.425,31.35) 56.425,27.711 57.205,26.931 v1(57.205,13.825)
VBUS_BT: C26.2 C27.2 C75.2 CN12.1 U10.1 U10.3 U31.1 | length 21.3
  Top Layer w0.2: v1(2.75,54.725) 1.525,54.725 1.15,54.35 C27.2@1.15,53.338 1.263,53.225 2.188,53.225 C26.2@2.325,53.087 2.35,53.112 U10.1@3.8,53.112 4.15,53.112 4.875,52.388 4.875,51.875 4.212,51.212 U10.3@3.8,51.212
  Signal Layer 3 w0.2: v1(2.75,54.725) 5.615,51.86 v1(8.615,51.86)
  Bottom Layer w0.2: CN12.1@4.3,53.425 6.075,53.425 6.575,52.925 U31.1@6.575,52.035 7.24,52.035 7.415,51.86 C75.2@7.95,51.86 v1(8.615,51.86)
VBUS_C: CN1.A4 CN1.A9 CN1.B4 CN1.B9 R4.1 R5.2 R7.2 R13.1 U2.1 U8.9 | length 20.1
  Top Layer w0.2: CN1.A9@18.28,59.42 18.33,59.47 CN1.B4@18.33,60.67 ; v1(20.03,57.825) 20.755,57.825 20.83,57.75 20.88,57.8 20.78,57.9 CN1.A4@20.78,59.42 ; U8.9@22.675,52.625 23.35,52.625 v1(23.45,52.725) ; v1(23.2,57.625) R5.2@26.804,57.625 ; v1(26.05,50.775) 26.4,51.125 R7.2@26.4,51.9 ; R4.1@28.95,60.4 v1(29.95,60.4)
  Top Layer w0.45: v1(21.275,48.2) 21.525,48.2 21.8,48.475 R13.1@21.925,48.35 v1(22.8,48.35)
  Bottom Layer w0.2: v1(23.2,57.625) 25.065,59.49 27.615,59.49 28.525,60.4 v1(29.95,60.4)
VDD_MCU: C88.2 C89.2 C90.2 C91.2 C92.2 C93.2 C94.1 C95.2 C96.2 C97.2 C98.2 C99.2 C100.2 C101.2 C103.2 C107.2 C108.2 C109.2 C110.2 C111.2 JP3.1 R21.1 R27.1 R28.1 R59.1 R60.1 SB6.1 U13.A3 U13.A6 U13.A8 U13.A11 U13.B1 U13.D13 U13.E13 U13.G1 U13.H12 U13.J13 U13.L2 U13.N3 U13.N7 U13.N10 U13.N12 | length 61
  Top Layer w0.08: 38.225,33.35 39.079,33.35 U13.H12@39.329,33.1
  Top Layer w0.2: v1(29.25,30.75) R27.1@29.975,30.75 R28.1@29.975,29.325 ; v1(36.125,34.25) 37.325,34.25 38.225,33.35 ; v1(36.125,35.15) 36.885,35.15 38.435,33.6 U13.J13@38.829,33.6 ; v1(36.425,31.7) 36.775,31.35 37.75,31.35 38,31.6 U13.E13@38.829,31.6 ; v1(36.475,30.75) 37.8,30.75 38.15,31.1 U13.D13@38.829,31.1 ; v1(37.35,37.75) 37.675,37.425 37.675,37.174 38.659,36.19 38.739,36.19 U13.N12@39.329,35.6 ; v1(38.625,37.5) 40.329,35.796 U13.N10@40.329,35.6 ; v1(38.65,26.975) 38.9,27.225 38.9,27.825 39.829,28.754 U13.A11@39.829,29.6 ; v1(40.8,27.4) 41.329,27.929 U13.A8@41.329,29.6 ; v1(41.75,36.875) 41.75,36.179 41.829,36.1 U13.N7@41.829,35.6 ; v1(42.175,26.975) 42.175,27.3 42.329,27.454 U13.A6@42.329,29.6 ; U13.A3@43.829,29.6 43.829,28.371 44.625,27.575 44.625,27.375 v1(44.95,27.05) ; U13.N3@43.829,35.6 43.829,35.804 43.975,35.95 v1(43.975,36.375) ; U13.L2@44.329,34.6 v2(44.579,34.85) ; U13.B1@44.829,30.1 45.575,29.354 v1(45.575,28.9) ; U13.G1@44.829,32.6 45.075,32.6 45.225,32.75 v1(45.5,32.75) ; v1(49.775,35.375) 50.225,35.375 R21.1@50.65,35.8
  Signal Layer 1 w0.3: v2(44.579,34.85) 44.825,35.096 v1(44.825,36.575)
  Bottom Layer w0.2: v1(36.125,34.25) C98.2@37.125,34.25 ; v1(36.125,35.15) C97.2@37.125,35.15 C96.2@37.125,36.1 ; v1(36.425,31.7) 36.425,32.283 36.692,32.55 C100.2@37.125,32.55 ; v1(36.475,30.75) C101.2@37.15,30.75 ; v1(37.35,37.75) C91.2@37.35,38.3 ; C111.2@38.6,26.4 38.65,26.45 v1(38.65,26.975) ; v1(38.625,37.5) C90.2@38.625,38.35 ; C90.2@38.65,38.35 C89.2@39.6,38.35 C88.2@40.525,38.35 ; C110.2@40.6,26.4 40.8,26.6 v1(40.8,27.4) ; v1(41.75,36.875) C93.2@41.75,37.475 ; v1(42.175,26.975) 42.175,26.55 C109.2@42.025,26.4 42.75,26.4 C108.2@43.025,26.125 ; C92.2@43.938,38 43.975,37.963 v1(43.975,36.375) ; SB6.1@44.35,29.2 44.65,28.9 v1(45.575,28.9) C103.2@46.225,28.9 ; v1(44.825,36.575) C95.2@45.65,36.575 46.75,36.575 C94.1@46.8,36.625 ; v1(44.95,27.05) 45.15,26.85 45.15,26.6 C107.2@45.35,26.4 46.4,26.4 R60.1@46.5,26.3 ; v1(45.5,32.75) 46.075,32.75 C99.2@46.225,32.6 ; R60.1@46.525,26.325 R59.1@47.95,26.325
VDD_OCTOSPI_FLASH: C76.2 C78.2 C82.2 R12.2 R15.1 SB2.2 U9.B4 U9.D1 U9.E4 | length 7.3
  Top Layer w0.2: v1(39.5,46.1) U9.E4@40,46.6 ; v1(40.5,50.1) U9.D1@41,49.6 ; R12.2@42.675,52.8 42.725,52.85 v1(43.875,52.85) ; U9.B4@43,46.6 v1(43.5,47.1) ; R15.1@48.25,45.2 v1(49.15,45.2)
  Bottom Layer w0.2: C82.2@38.85,46.05 38.9,46.1 v1(39.5,46.1) ; v1(40.5,50.1) 40.5,50.725 C76.2@40.55,50.775 ; v1(43.5,47.1) 44.1,47.1 C78.2@44.15,47.15 ; SB2.2@48.15,45.2 v1(49.15,45.2)
VDD_OCTOSPI_SRAM: C55.2 C60.2 C114.2 C119.2 R37.2 SB8.2 U20.B4 U20.D1 U20.E4 U37.8 | length 12.5
  Top Layer w0.2: v1(37.225,17.875) C60.2@37.225,16.5 37.325,16.6 U20.E4@40,16.6 ; v1(39.925,21.35) C55.2@40.55,21.35 40.55,20.05 U20.D1@41,19.6 ; U20.B4@43,16.6 v1(43.5,16.1) ; R37.2@48.15,18.025 v1(49.275,18.025)
  Bottom Layer w0.2: U37.8@42.184,13.348 42.175,13.339 C119.2@42.175,12.025 v1(42.85,12.025) ; v1(43.5,16.1) 44.1,16.1 C114.2@44.15,16.15 ; SB8.2@48.075,18.025 v1(49.275,18.025)
VIN: C117.2 CN17.8 U38.3 | length 25.1
  Bottom Layer w0.8: CN17.8@40.12,9.024 42.649,9.024 45.65,12.025 59.4,12.025 60.575,13.2 C117.2@60.575,14.6 U38.3@62.075,14.6
VREFP: C38.1 C39.2 C74.1 R21.2 R47.2 U13.L1 | length 29.3
  Top Layer w0.08: U13.L1@44.829,34.6 45.55,34.6 46.45,35.5 46.45,35.9 46.675,36.125 C39.2@47.15,36.125 47.725,36.7 C38.1@47.975,36.7
  Top Layer w0.12: C38.1@47.975,36.7 C38.1@48.3,36.7 v1(49.25,36.7) R21.2@50.65,36.7
  Signal Layer 3 w0.2: v1(49.25,36.7) 52.9,40.35 52.9,43.475 54.5,45.075 54.5,48.275 55.725,49.5 57.8,49.5 59.425,51.125 v1(60.4,51.125)
  Bottom Layer w0.2: v1(60.4,51.125) C74.1@60.975,51.125 R47.2@61.975,51.125
WRLS.FLOW: M1.13 U13.A5 | length 51.1
  Top Layer w0.1: 42.829,25.925 U13.A5@42.829,29.6
  Top Layer w0.12: 42.829,25.925 42.829,24.871 43.175,24.525 44.95,24.525 45.03,24.445 46.381,24.445 46.886,24.95 57.1,24.95 57.78,25.63 57.78,28.685 v1(58.47,29.375) ; v1(81.25,30.3) 81.25,33.292 M1.13@81.28,33.322
  Bottom Layer w0.12: v1(58.47,29.375) 66.175,29.375 67.73,30.93 75.333,30.93 75.963,30.3 v1(81.25,30.3)
WRLS.NOTIFY: M1.14 U13.J10 | length 96.8
  Top Layer w0.1: v2(40.079,33.85) U13.J10@40.329,33.6
  Top Layer w0.12: v1(32.25,51.58) 31.825,51.155 31.825,45.375 35.55,41.65 v2(35.55,39.6) ; v1(79.275,34.625) 79.275,33.327 M1.14@79.28,33.322
  Signal Layer 1 w0.08: 35.55,39 35.55,37.8 39.085,34.265 39.289,34.265 39.454,34.1 39.829,34.1 v2(40.079,33.85)
  Signal Layer 1 w0.12: 35.55,39 v2(35.55,39.6)
  Signal Layer 2 w0.1: v1@66.5,38.25 v1(66.5,38.4)
  Signal Layer 2 w0.12: v1(50.9,40.7) 50.9,40.985 50.47,41.415 50.47,42.245 51.375,43.15 v1(51.375,49.95) ; v1(65.575,32.425) 66.5,33.35 v1@66.5,38.25
  Bottom Layer w0.1: v1@66.5,38.25 v1(66.5,38.4)
  Bottom Layer w0.12: v1(32.25,51.58) 32.52,51.85 34.305,51.85 34.48,51.675 34.48,50.77 35.875,49.375 39.875,49.375 40.625,48.625 42.225,48.625 43.33,49.73 46.945,49.73 47.555,49.12 48.488,49.12 49.318,49.95 v1(51.375,49.95) ; v1(50.9,40.7) 51.925,40.7 54.675,37.95 60.325,37.95 61.9,36.375 65.8,36.375 66.5,37.075 v1@66.5,38.25 ; v1(65.575,32.425) 67.075,32.425 67.505,31.995 78.72,31.995 79.275,32.55 v1(79.275,34.625)
WRLS.SPI2_MISO: M1.7 U13.D8 | length 68.5
  Top Layer w0.1: v2(41.079,30.85) U13.D8@41.329,31.1
  Top Layer w0.12: v1(78.4,20.675) 78.4,22.225 80.322,24.147 M1.7@89.88,24.147
  Signal Layer 1 w0.08: 39.475,25.925 39.475,27.275 40.829,28.629 40.829,30.6 v2(41.079,30.85)
  Signal Layer 1 w0.12: v1(38.275,24.35) 38.573,24.35 39.475,25.252 39.475,25.925
  Signal Layer 2 w0.12: v1(37.375,19.975) 37.375,23.45 v1(38.275,24.35)
  Bottom Layer w0.12: v1(37.375,19.975) 44.575,19.975 45.005,20.405 45.427,20.827 57.188,20.827 57.61,20.405 58.73,20.405 59.095,20.77 75.33,20.77 75.425,20.675 v1(78.4,20.675)
WRLS.SPI2_MOSI: M1.9 U13.C8 | length 196.9
  Top Layer w0.1: v2(41.079,30.35) U13.C8@41.329,30.6
  Top Layer w0.12: M1.9@89.28,33.322 89.28,34.855 89.65,35.225 v1(91.375,35.225)
  Signal Layer 1 w0.08: v2(41.079,30.35) 41.329,30.1 41.329,27.388 41.1,27.158 41.1,25.925
  Signal Layer 1 w0.12: 41.1,25.925 41.1,23.125 v1(41.5,22.725)
  Signal Layer 2 w0.12: v1(17.575,64.3) 15.725,64.3 14.275,62.85 14.275,58.8 16.4,56.675 16.4,51.575 17.45,50.525 17.45,40.975 13.7,37.225 13.7,33.1 15.375,31.425 18.625,31.425 19.125,30.925 19.125,25.55 v1(20.075,24.6) ; v1(90.675,65.1) 90.675,64.625 94.045,61.255 94.045,43.195 91.375,40.525 v1(91.375,35.225)
  Bottom Layer w0.12: v1(17.575,64.3) 25.15,64.3 25.575,63.875 29.875,63.875 32.595,66.595 50.544,66.595 50.683,66.455 54.491,66.455 55.381,65.565 58.185,65.565 59.475,64.275 69.625,64.275 70.45,65.1 v1(90.675,65.1) ; v1(20.075,24.6) 24.975,24.6 25.88,23.695 25.88,22.406 27.076,21.21 29.589,21.21 30.43,22.051 30.43,22.28 30.45,22.3 30.45,23.025 30.45,23.826 31.424,24.8 36.573,24.8 37.988,23.385 ; 38.06,23.385 37.988,23.385 ; v1(41.5,22.725) 40.873,22.725 40.143,23.455 39.055,23.455 38.985,23.385 37.988,23.385
WRLS.SPI2_NSS: M1.8 U13.L10 | length 113.5
  Top Layer w0.08: v2(40.079,34.85) U13.L10@40.329,34.6
  Top Layer w0.12: v1(36.1,48.125) 34.44,48.125 33.415,47.1 33.415,45.735 36.775,42.375 v2(39.65,42.375) ; M1.8@89.88,26.147 91.397,26.147 92.05,26.8 v1(94.45,26.8)
  Signal Layer 1 w0.08: v2(40.079,34.85) 40.079,34.866 40.375,35.162 40.375,39
  Signal Layer 1 w0.12: v2(39.65,42.375) 39.65,40.9 40.375,40.175 40.375,39
  Signal Layer 2 w0.12: v1(94.45,26.8) v1(94.45,53.9)
  Bottom Layer w0.1: 63.95,50.333 64.319,50.333 65.536,51.55 67.809,51.55 70.124,53.865 70.149,53.865 70.184,53.9 71.863,53.9
  Bottom Layer w0.12: v1(36.1,48.125) 42.8,48.125 43.275,48.6 44.7,48.6 45.25,48.05 48.602,48.05 49.802,49.25 54.964,49.25 55.224,49.51 58.446,49.51 59.268,50.333 63.95,50.333 ; 71.863,53.9 v1(94.45,53.9)
WRLS.SPI2_SCK: M1.10 U13.F6 | length 60.7
  Top Layer w0.08: v3(42.329,32.1) v2(42.579,31.85)
  Top Layer w0.12: v1(87.28,28.93) M1.10@87.28,33.322
  Signal Layer 1 w0.08: v3(42.329,32.1) v2(42.579,31.85)
  Signal Layer 2 w0.08: v3(42.329,32.1) 42.579,31.85 42.579,28.204 42.665,28.118 42.665,25.925
  Signal Layer 2 w0.12: 42.665,25.925 42.665,25.232 42.67,25.227 42.67,25.182 43.752,24.1 v1(44.275,24.1)
  Bottom Layer w0.12: v1(44.275,24.1) 44.275,23.65 44.63,23.295 46.981,23.295 47.591,23.905 51.691,23.905 52.271,24.485 56.496,24.485 60.501,28.49 68.615,28.49 69.675,29.55 86.66,29.55 v1(87.28,28.93)
WRLS.SWCLK: CN11.2 M1.3 | length 6.8
  Top Layer w0.12: M1.3@89.88,16.147 90.378,16.147 93.445,13.08 CN11.2@95.4,13.08
WRLS.SWDIO: CN11.4 M1.4 | length 9.9
  Top Layer w0.12: 94.275,18.15 89.883,18.15 M1.4@89.88,18.147 94.275,18.147 95.387,18.147 CN11.4@95.4,18.16
WRLS.UART4_RX: U1.1 U13.A9 | length 92.5
  Top Layer w0.08: 40.195,25.925 40.195,27.495 40.829,28.129 U13.A9@40.829,29.6
  Top Layer w0.12: v1(1.325,66.425) 1.385,66.425 1.56,66.25 U1.1@2.325,66.25 ; 40.195,25.925 40.195,25.005 v1(40.575,24.625)
  Signal Layer 2 w0.12: v1(1.325,66.425) 2.075,65.675 2.075,64.475 6.28,60.27 6.28,57.302 v1(10.811,52.771) ; v1(21.925,26.125) 21.605,26.445 21.605,32.225 23.555,34.175 23.555,40.8 23.3,41.055 23.3,48.525 22.34,49.485 ; 22.34,50.1 22.34,49.485 ; v1(22.34,55.265) 22.34,49.485
  Bottom Layer w0.12: v1(10.811,52.771) 15.921,52.771 16.75,53.6 20.675,53.6 v1(22.34,55.265) ; v1(21.925,26.125) 22.85,25.2 25.36,25.2 26.42,24.14 26.42,22.555 27.2,21.775 29.475,21.775 29.95,22.25 29.95,24.005 31.27,25.325 36.727,25.325 37.87,24.182 38.107,23.945 38.445,23.945 38.725,24.225 39.125,24.625 v1(40.575,24.625)
WRLS.UART4_TX: U1.56 U13.C9 | length 84.7
  Top Layer w0.1: v2(40.579,30.35) U13.C9@40.829,30.6
  Top Layer w0.12: U1.56@4.6,66.25 v1@4.6,66.965
  Signal Layer 1 w0.08: 38.725,25.925 39.175,26.375 39.175,27.3 40.579,28.704 v2(40.579,30.35)
  Signal Layer 1 w0.1: v1(37.85,25.05) 38.725,25.925
  Signal Layer 2 w0.12: v1(4.6,66.975) v1(12.65,66.975) ; v1(23.65,27.125) 23.65,28.214 25.92,30.484 25.92,37.38 24.88,38.42 ; 24.88,39.325 24.88,38.42 ; v1(26.025,60.6) 24.245,58.82 24.245,55.315 24.455,55.105 24.455,47.662 24.88,47.237 24.88,38.42
  Bottom Layer w0.12: v1(12.65,66.975) 15.825,63.8 24.975,63.8 26.025,62.75 v1(26.025,60.6) ; v1(23.65,27.125) 25.65,27.125 25.71,27.185 32.69,27.185 34.275,25.6 37.3,25.6 v1(37.85,25.05)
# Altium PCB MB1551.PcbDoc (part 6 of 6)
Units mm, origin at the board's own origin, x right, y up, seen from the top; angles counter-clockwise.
Board outline 100 x 70 mm, 6 copper layers (Top Layer, Signal Layer 1, Signal Layer 2, Signal Layer 3, Signal Layer 4, Bottom Layer), stack 1.49 mm thick; 325 components, 276 nets, 1540 pads, 1100 vias.

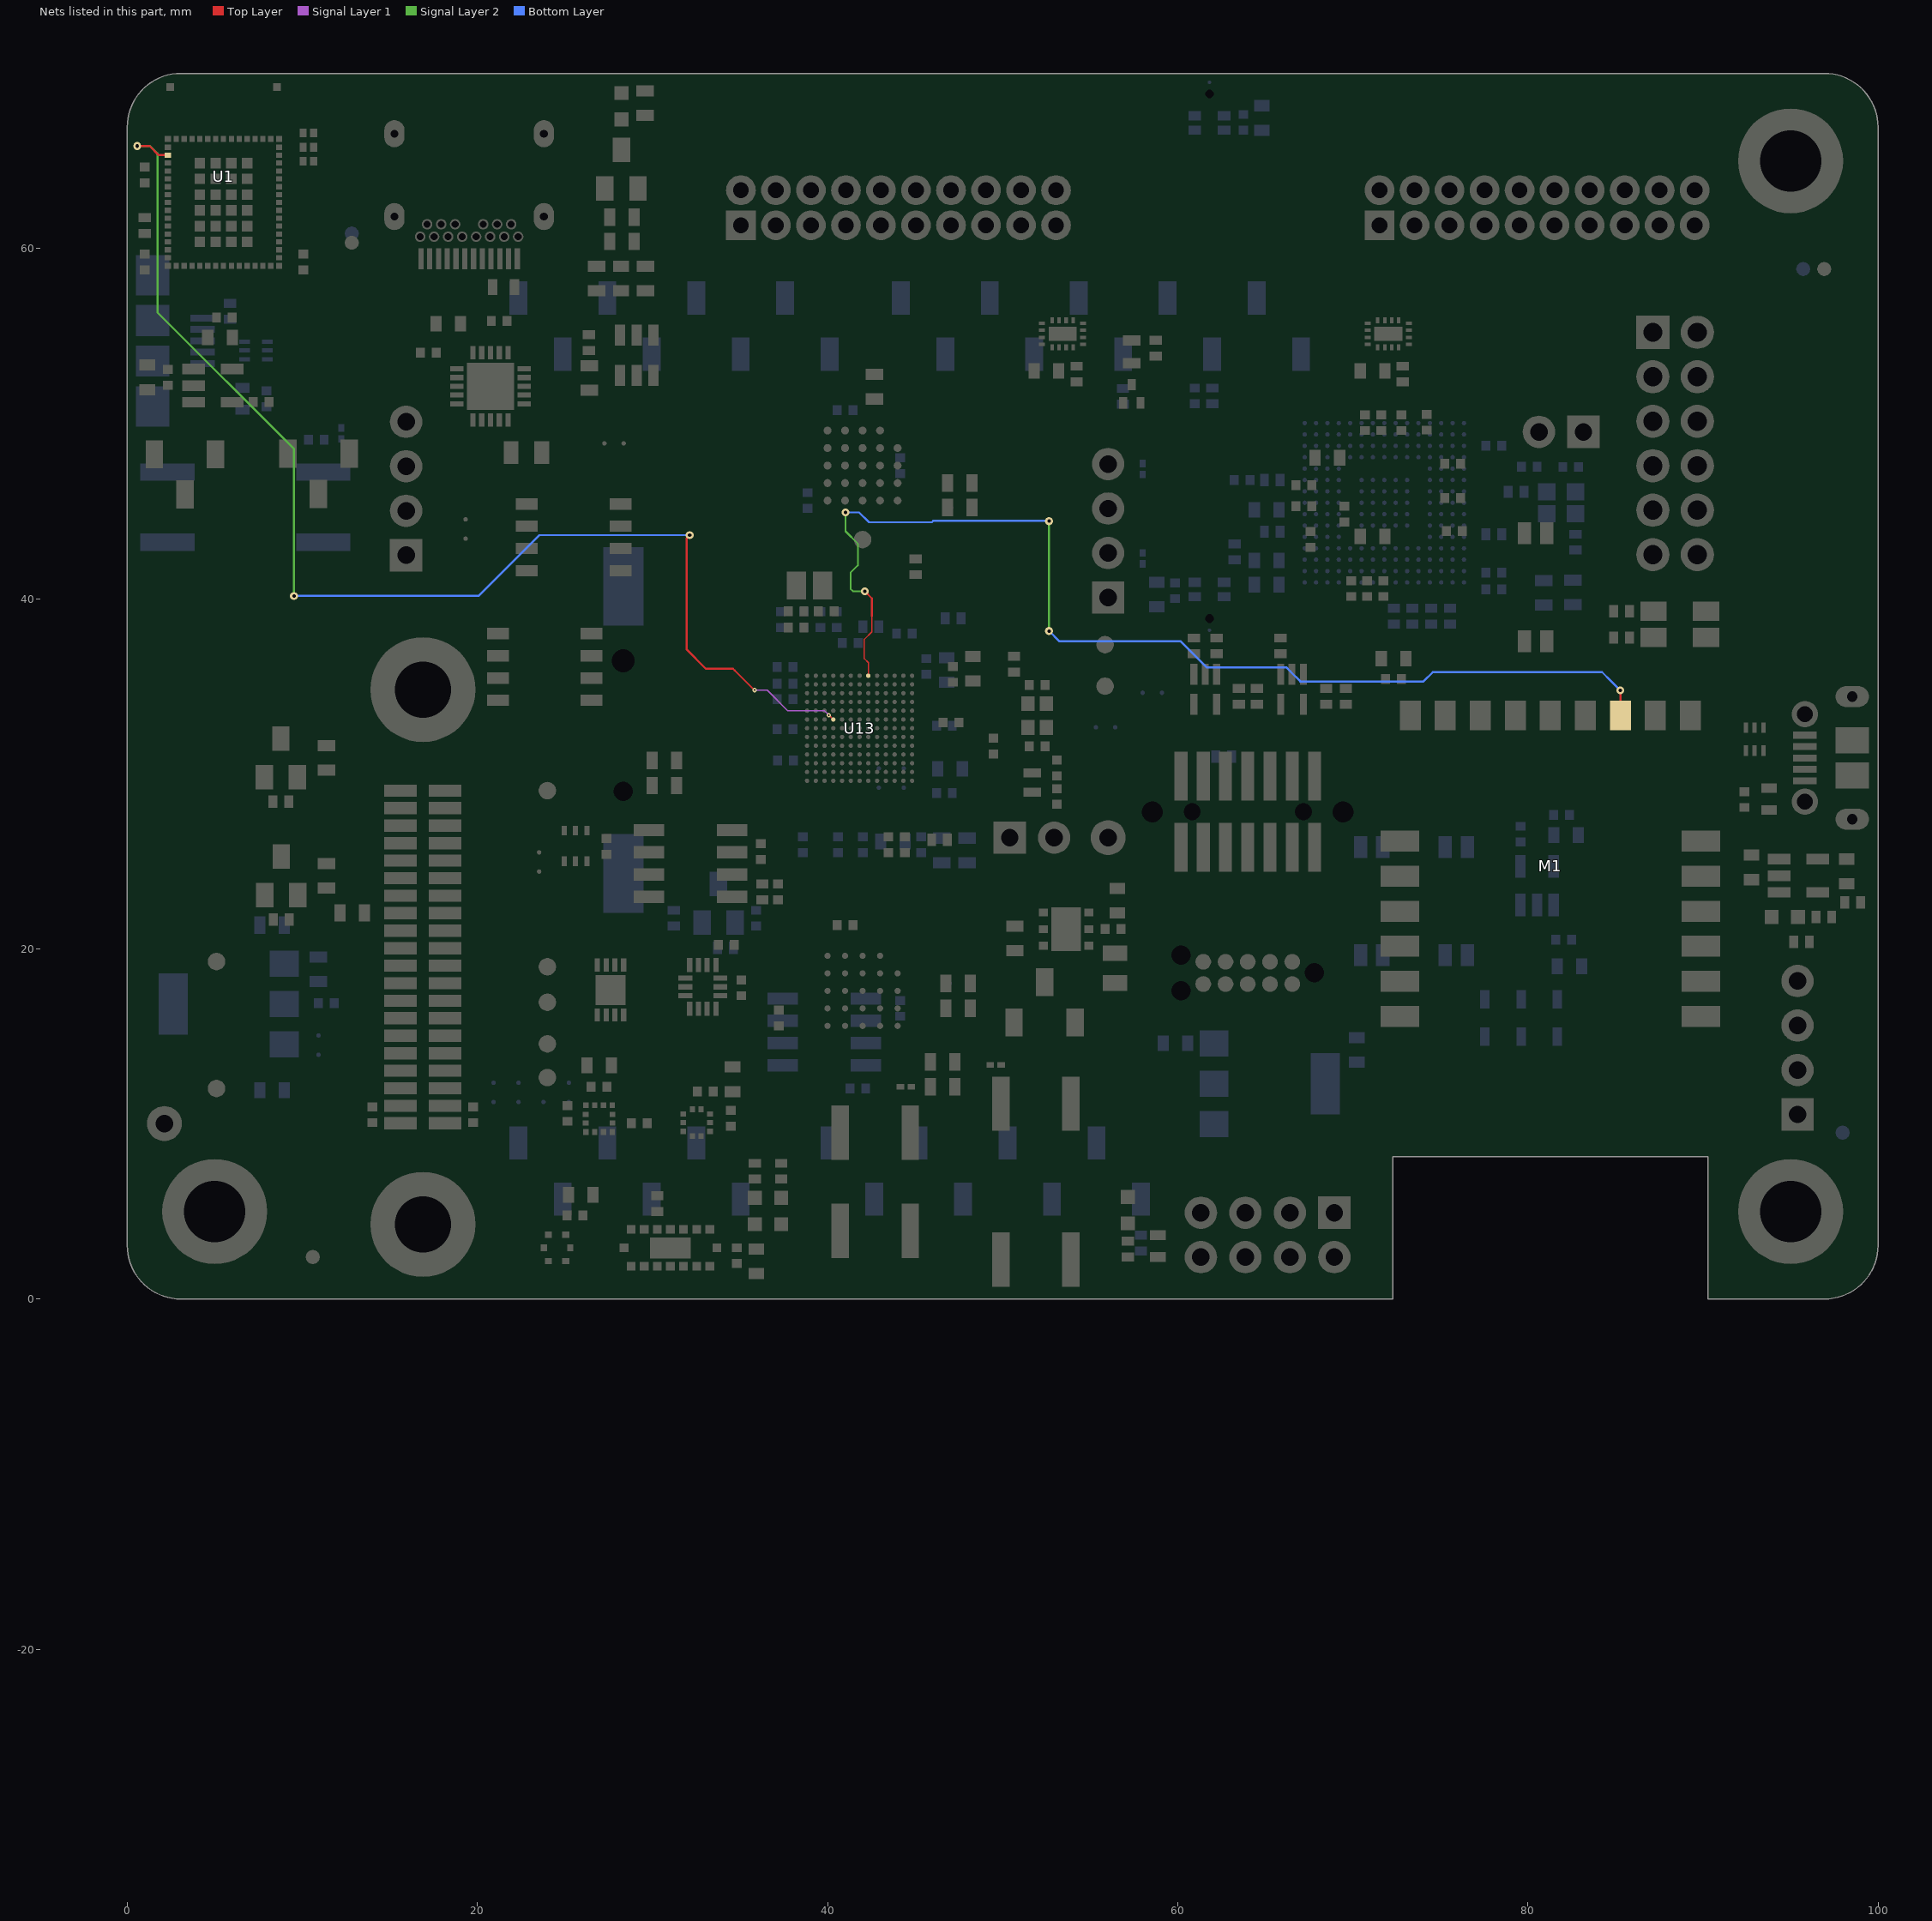
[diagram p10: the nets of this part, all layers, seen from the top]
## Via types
v1: diameter 0.45, hole 0.2, Top Layer to Bottom Layer, tented both sides, 922 vias
v2: diameter 0.25, hole 0.1, Top Layer to Signal Layer 1, tented top, 142 vias
v3: diameter 0.25, hole 0.1, Signal Layer 1 to Signal Layer 2, 36 vias

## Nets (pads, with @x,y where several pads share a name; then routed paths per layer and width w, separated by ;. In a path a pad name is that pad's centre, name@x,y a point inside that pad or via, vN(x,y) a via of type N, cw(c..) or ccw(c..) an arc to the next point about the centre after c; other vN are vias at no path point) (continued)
WRLS.WKUP_B: U1.3 U13.H10 | length 72.5
  Top Layer w0.08: 34.7,35.9 v2(35.825,34.775) ; v2(40.079,33.35) U13.H10@40.329,33.1
  Top Layer w0.12: v1(0.575,65.85) 1.275,65.85 1.8,65.325 U1.3@2.325,65.325 ; v1(32.125,43.625) 31.945,43.445 31.945,37.105 33.05,36 34.6,36 34.7,35.9
  Signal Layer 1 w0.08: v2(35.825,34.775) 36.55,34.775 37.725,33.6 38.976,33.6 39.183,33.6 39.829,33.6 v2(40.079,33.35)
  Signal Layer 2 w0.12: v1(0.575,65.85) 1.3,65.85 1.725,65.425 1.725,56.35 9.525,48.55 v1(9.525,40.15)
  Bottom Layer w0.12: v1(9.525,40.15) 20.064,40.15 23.539,43.625 v1(32.125,43.625)
WRLS.WKUP_W: M1.11 U13.N6 | length 65.1
  Top Layer w0.08: U13.N6@42.329,35.6 42.329,36.346 42.1,36.575 42.1,37.675 42.535,38.11 42.535,39
  Top Layer w0.12: v1(42.125,40.425) 42.535,40.015 42.535,39 ; M1.11@85.28,33.322 v1(85.28,34.755)
  Signal Layer 2 w0.1: v1(41.025,44.925) 41.025,43.845 41.73,43.14 41.73,41.896 41.31,41.476 41.31,40.563 41.448,40.425 v1(42.125,40.425)
  Signal Layer 2 w0.12: v1(52.65,38.15) v1(52.65,44.425)
  Bottom Layer w0.12: v1(41.025,44.925) 41.8,44.925 42.365,44.36 45.96,44.36 46.045,44.445 52.63,44.445 v1(52.65,44.425) ; v1(52.65,38.15) 53.225,37.575 60.15,37.575 61.645,36.08 64.882,36.08 66.195,36.08 66.425,35.85 67.005,35.27 67.832,35.27 74.037,35.27 74.567,35.8 84.235,35.8 84.735,35.3 v1(85.28,34.755)
pads on no net: CN1.A2 CN1.A3 CN1.A8 CN1.A10 CN1.A11 CN1.B2 CN1.B3 CN1.B8 CN1.B10 CN1.B11 CN4.9 CN4.10 CN7.5 CN7.6 CN7.9 CN7.10 CN8.4 CN9.0 CN9.1 CN9.2 CN9.9 CN10.7 CN10.9 CN10.11 CN10.12 CN10.13 CN15.NPTH1 CN15.NPTH2 M1.5 M1.6 M1.12 M1.15 M1.18 M1.20 M1.21 M1.22 MIRE1.1 MIRE2.1 MIRE3.1 MIRE4.1 MIRE5.1 MIRE6.1 SW6.3 U1.2 U1.7 U1.8 U1.9 U1.11 U1.12 U1.14 U1.18 U1.19 U1.20 U1.21 U1.22 U1.23 U1.24 U1.27 U1.28 U1.33 U1.34 U1.35 U1.36 U1.37 U1.38 U1.39 U1.40 U1.41 U1.42 U1.43 U1.44 U1.48 U1.49 U1.50 U1.51 U1.52 U1.53 U1.54 U1.55 U1.61 U1.62 U1.63 U1.64 U1.65 U1.66 U1.67 U1.68 U1.69 U1.70 U1.71 U1.72 U1.73 U1.74 U1.75 U1.76 U1.77 U1.78 U1.79 U1.80 U1.81 U1.82 U1.83 U1.85 U3.17 U4.17 U5.5 U6.6 U7.6 U9.A2 U9.A3 U9.B1 U9.B5 U11.4 U14.4 U16.3 U16.6 U16.8 U19.1 U19.4 U19.5 U20.A2 U20.A5 U20.B1 U20.B5 U20.C2 U20.C5 U21.9 U21.10 U21.11 U27.C2 U27.C5 U28.3 U30.4 U32.A1 U32.A2 U32.A3 U32.A4 U32.A5 U32.A6 U32.A8 U32.A9 U32.A10 U32.A11 U32.A12 U32.A13 U32.B1 U32.B2 U32.B3 U32.B4 U32.B5 U32.B6 U32.B7 U32.B8 U32.B9 U32.B10 U32.B11 U32.B12 U32.B13 U32.B14 U32.B15 U32.C2 U32.C3 U32.C4 U32.C11 U32.C12 U32.C13 U32.C14 U32.C15 U32.D1 U32.D2 U32.D3 U32.D4 U32.D10 U32.D11 U32.D13 U32.D14 U32.E1 U32.E2 U32.E3 U32.E4 U32.E12 U32.E13 U32.E14 U32.E15 U32.F1 U32.F4 U32.F14 U32.G4 U32.G14 U32.G15 U32.H1 U32.H2 U32.H3 U32.H4 U32.H14 U32.H15 U32.J2 U32.J3 U32.J4 U32.K1 U32.K2 U32.K3 U32.K12 U32.K14 U32.K15 U32.L1 U32.L3 U32.L12 U32.L13 U32.L14 U32.L15 U32.M2 U32.M3 U32.M4 U32.M5 U32.M6 U32.M7 U32.M12 U32.M13 U32.M14 U32.M15 U32.N2 U32.N4 U32.N5 U32.N6 U32.N7 U32.N11 U32.N13 U32.N14 U32.N15 U32.P2 U32.P4 U32.P5 U32.P6 U32.P7 U32.P8 U32.P9 U32.P10 U32.P11 U32.P12 U32.P13 U32.P14 U32.P15 U32.R2 U32.R3 U32.R6 U32.R7 U32.R8 U32.R9 U32.R10 U32.R11 U32.R12 U32.R13

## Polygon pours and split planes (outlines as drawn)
GND on Top Layer "GND" (solid, pour order 26): 99.6,72.525 102.8,69.325 102.8,1.2 97.825,-3.775 -0.8,-3.775 -3.725,-0.85 -3.725,70.55 -1.75,72.525
NetQ6_1 on Top Layer "NO_FT" (solid, pour order 10): 22.2,34.92 22.2,38.485 21.63,39.055 19.93,39.055 19.3,38.425 19.3,35.765 20.34,34.725 22.005,34.725
5V on Top Layer "NO_FT" (solid, pour order 6): 57.325,21.75 57.325,22.5 57.1,22.725 56.225,22.725 56,22.95 56,23.75 55.8,23.95 54.95,23.95 54.7,23.7 54.7,23.325 55.225,22.8 55.225,22.575 55.1,22.45 54.65,22.45 54.55,22.35 54.55,21.775 54.65,21.675 57.25,21.675
3V3 on Top Layer "NO_FT" (solid, pour order 4): 54.675,21.625 56.1,21.625 56.3,21.425 56.3,20.775 56.625,20.45 58.45,20.45 58.775,20.125 58.775,19.325 58.475,19.025 55.525,19.025 55.275,19.275 55.275,20.525 55.15,20.65 54.65,20.65 54.55,20.75 54.55,21.5
NetQ2_7 on Top Layer "NO_FT" (solid, pour order 8): 29.725,37.84 28.16,36.275 22.725,36.275 22.625,36.375 22.625,38.775 22.925,39.075 28.025,39.075 29,40.05 29,43.1 28.85,43.25 24.315,43.25 23.85,43.715 23.85,46.55 23.225,47.175 23.225,49.6 23.475,49.85 23.85,49.85 26.275,47.425 28.9,47.425 29.725,46.6
5V on Top Layer "NO_FT" (solid, pour order 20): 28.85,48.15 28.355,48.645 28.355,49.355 29.15,50.15 29.8,50.15 30.05,49.9 30.05,48.625 29.575,48.15
UCPD_SINK on Top Layer "NO_FT" (solid, pour order 24): 19.675,43.425 20.025,43.075 20.025,41.925 19.3,41.2 18.575,41.2 18.45,41.325 18.45,42.875 19,43.425
5V_UCPD on Top Layer "NO_FT" (solid, pour order 22): 19.325,44.525 19.65,44.525 20.225,45.1 20.225,46.05 19.925,46.35 18.675,46.35 18.25,45.925 18.25,45.3 19.025,44.525
UCPD_SOURCE on Top Layer "NO_FT" (solid, pour order 18): 26.955,48.219 27.255,48.519 27.255,49.32 26.75,49.825 25.5,49.825 25.3,49.625 25.3,48.825 25.906,48.219
UCPD_SOURCE on Top Layer "NO_FT" (solid, pour order 14): 24.35,43.43 28.795,43.43 28.95,43.275 28.95,40.55 27.575,39.175 25.4,39.175 25.225,39.35 25.225,40.04 24.815,40.45 24.45,40.45 24.125,40.775 24.125,43.205
NetQ2_1 on Top Layer "NO_FT" (solid, pour order 12): 23.85,42.32 23.85,45.675 23.525,46 21.625,46 20.898,45.273 20.898,42.452 21.45,41.9 23.43,41.9
UCPD_SINK on Top Layer "NO_FT" (solid, pour order 16): 24.925,32.925 28.15,32.925 28.82,33.625 28.82,34.753 27.523,36.05 22.65,36.05 22.4,35.8 22.4,33.3 22.775,32.925
GND on Bottom Layer "GND" (solid, pour order 28): 99.595,72.532 102.795,69.332 102.795,1.207 97.82,-3.768 -0.805,-3.768 -3.73,-0.843 -3.73,70.557 -1.755,72.532
NetC112_2 on Bottom Layer "NO_FT" (solid, pour order 2): 81.95,23.7 82.275,23.375 82.275,16.422 81.853,16 77.275,16 76.75,16.525 76.75,17.775 77.475,18.5 79.95,18.5 80.85,19.4 80.85,20.65 80.475,21.025 79.225,21.025 78.9,21.35 78.9,23.525 79.075,23.7
GND on Signal Layer 3 "GND" (solid, pour order 60): 98.325,71.725 102.4,67.65 102.4,-0.15 99.25,-3.3 1.75,-3.3 -2.425,0.875 -2.425,68.725 0.575,71.725
3V3_BT on Signal Layer 3 "3V3_BT" (solid, pour order 44): 6.95,48.35 0.275,48.35 -0.225,48.85 -0.225,63.025 1.575,64.825 12.775,64.825 14.15,63.45 14.15,57.375 15.094,56.431 15.094,53.056 16.5,51.65 19.734,51.65 20.55,50.834 20.55,45.281 19.994,44.725 17.575,44.725 16.775,43.925 16.775,42.275 15.7,41.2 14.1,41.2
3V3_STLK on Signal Layer 3 "3V3_STLK" (solid, pour order 40): 54.655,40.755 55.475,41.575 65.7,41.575 67.58,43.455 67.58,48.38 69.125,49.925 78,49.925 80.575,47.35 86.3,47.35 91,42.65 91,40.175 89.925,39.1 82.125,39.1 81.825,38.8 81.825,27.95 81.5,27.625 81.025,27.625 80.25,28.4 80.25,37.6 79.55,38.3 55.705,38.3 54.655,39.35
5V on Signal Layer 3 "5V" (solid, pour order 42): 33.65,57.375 32.775,58.25 32.775,70.525 33.325,71.075 100.675,71.075 101.8,69.95 101.8,-1.25 98.45,-4.6 95.45,-1.6 -2.075,-1.6 -2.075,8.925 -1.2,9.8 5.775,9.8 7.425,11.45 10.275,11.45 13.45,8.275 19.725,8.275 23.65,4.35 52.4,4.35 52.425,4.375 52.823,3.977 69.002,3.977 69.95,4.925 69.95,11.6 72.475,14.125 86.725,14.125 92.875,20.275 92.875,56.525 92.025,57.375
UCPD_SINK on Signal Layer 3 "NO_FT" (solid, pour order 58): 25.625,32.75 25.625,34.525 20.975,39.175 20.975,43.205 19.761,44.419 18.094,44.419 17.625,43.95 17.625,39.625 23.725,33.525 23.725,32.925 24.1,32.55 25.425,32.55
UCPD_SOURCE on Signal Layer 3 "NO_FT" (solid, pour order 56): 24.604,50.177 26.948,50.177 27.637,49.488 27.637,39.837 27.058,39.258 25.817,39.258 24.125,40.95 24.125,49.702
VBUS_C on Signal Layer 3 "VBUS_C" (solid, pour order 36): 23.112,48.212 23.112,50.071 23.51,50.469 25.369,50.469 26.469,50.469 26.7,50.7 26.7,52.25 25.8,53.15 22.998,53.15 22.573,53.575 22.568,56.518 24.6,58.55 24.6,61.15 22.3,63.475 15.2,63.475 14.3,62.575 14.3,57.725 15.4,56.625 15.4,53.2 16.675,51.925 19.706,51.925 20.75,50.881 20.75,48.291 21.016,48.025 22.925,48.025
VDD_OCTOSPI_FLASH on Signal Layer 3 "VDD_OCTOSPI_FLASH" (solid, pour order 50): 38.95,49.5 42.675,53.225 44.55,53.225 44.9,52.875 44.9,48.15 47.275,45.775 49.255,45.775 49.575,45.455 49.575,44.85 49.35,44.625 39.75,44.625 38.95,45.425
VDD_OCTOSPI_SRAM on Signal Layer 3 "VDD_OCTOSPI_SRAM" (solid, pour order 52): 40.55,21.8 43.975,18.375 49.525,18.375 49.625,18.275 49.625,17.875 47.95,16.2 44.9,16.2 43.425,14.725 43.425,12.05 42.95,11.575 42.4,11.575 42.025,11.95 42.025,15.725 40.375,17.375 36.9,17.375 36.575,17.7 36.575,18.925 39.45,21.8
2V8 on Signal Layer 3 "2V8" (solid, pour order 38): 13.7,8.65 10.65,11.7 7.375,11.7 4.275,8.65 1.35,8.65 0.6,9.4 0.6,10.7 5.7,15.8 5.7,29.175 5.925,29.4 7.575,29.4 9.725,27.25 9.725,17.375 17.275,9.825 19.925,9.825 20.275,9.475 20.275,9.025 19.9,8.65
VDD_MCU on Signal Layer 3 "NO_TH" (solid, pour order 46): 48.925,38.45 49.7,37.675 49.7,29.525 51.725,27.5 51.725,25.425 51.28,24.98 47.77,24.98 46.4,26.35 37.575,26.35 33.875,30.05 29.1,30.05 28.65,30.5 28.65,31.75 29.4,32.5 33.625,32.5 35.275,34.15 35.275,36.65 37.075,38.45
GND on Signal Layer 1 "GND" (solid, pour order 32): 99.6,72.525 102.8,69.325 102.8,1.2 97.825,-3.775 -0.8,-3.775 -3.725,-0.85 -3.725,70.55 -1.75,72.525
3V3 on Signal Layer 4 "3V3" (solid, pour order 54): 98.325,71.675 102.4,67.6 102.4,-0.2 99.25,-3.35 1.75,-3.35 -2.425,0.825 -2.425,68.675 0.575,71.675
GND on Signal Layer 2 "GND" (solid, pour order 30): 99.6,72.525 102.8,69.325 102.8,1.2 97.825,-3.775 -0.8,-3.775 -3.725,-0.85 -3.725,70.55 -1.75,72.525

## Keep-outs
Keep-Out Layer:
  rectangle: 0.5,67.225 8.1,69.725
  region: 0,69.725 0,57.875 0.5,57.875 0.5,69.725

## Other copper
Top Layer:
  pour cut-out: 31.325,11.8 31.325,8.8 33.995,8.8 33.995,11.8
  pour cut-out: 23.25,4.235 25.943,4.235 25.943,1.675 23.25,1.675
  text "1" at 2.131,31.25 h1.5 r90
  text ".Layer_Name" at 12.297,-25.77 h3
  text ".GTL" at 53.992,-25.77 h3
Signal Layer 1:
  pour cut-out: 31.325,11.8 31.325,8.8 33.995,8.8 33.995,11.8
  pour cut-out: 23.25,4.235 25.943,4.235 25.943,1.675 23.25,1.675
  text "2" at 2.131,32.5 h1.5 r90
  text ".Layer_Name" at 12.297,-25.77 h3
  text ".G1" at 53.992,-25.77 h3
Signal Layer 2:
  pour cut-out: 31.325,11.8 31.325,8.8 33.995,8.8 33.995,11.8
  pour cut-out: 23.25,4.235 25.943,4.235 25.943,1.675 23.25,1.675
  text "3" at 2.131,33.75 h1.5 r90
  text ".Layer_Name" at 12.297,-25.77 h3
  text ".G2" at 53.992,-25.77 h3
Signal Layer 3:
  pour cut-out: 31.325,11.8 31.325,8.8 33.995,8.8 33.995,11.8
  pour cut-out: 23.25,4.235 25.943,4.235 25.943,1.675 23.25,1.675
  text "4" at 2.131,35 h1.5 r90
  text ".Layer_Name" at 12.329,-25.753 h3
  text ".G3" at 54.024,-25.753 h3
Signal Layer 4:
  pour cut-out: 31.325,11.8 31.325,8.8 33.995,8.8 33.995,11.8
  pour cut-out: 23.25,4.235 25.943,4.235 25.943,1.675 23.25,1.675
  text "5" at 2.131,36.25 h1.5 r90
  text ".Layer_Name" at 12.329,-25.753 h3
  text ".G4" at 54.024,-25.753 h3
Bottom Layer:
  pour cut-out: 31.325,11.8 31.325,8.8 33.995,8.8 33.995,11.8
  pour cut-out: 23.25,4.235 25.943,4.235 25.943,1.675 23.25,1.675
  text "6" at 2.131,37.5 h1.5 r90
  text ".GBL" at 42.789,-25.802 h3
  text ".Layer_Name" at 84.103,-25.802 h3
Multi-Layer:
  pour cut-out: 0.756,31.125 2.506,31.125 2.506,38.75 0.756,38.75

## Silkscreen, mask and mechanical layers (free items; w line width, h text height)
Top Overlay:
  lines w0.1: 22.885,1.535 22.885,4.197 ; 22.885,5.385 22.885,33.09 ; 60.487,38.388 60.487,41.321 63.237,41.321 63.237,38.3 ; 60.487,66.266 63.237,66.266 63.237,69.866 60.487,69.866 60.487,66.266
  lines w0.12: 8.375,6.045 13.885,0.535
  text "STMod+1" at 64.7,68.67 h1.3
  text "STMod+2" at 55.125,68.625 h1.3
  text "5V_USB" at 26.95,65.575 h1.27 r90
  text "MIC1" at 60.65,65.05 h1.3
  text "J" at 59.862,59.537 h12
  text "PMOD" at 91.95,58.325 h1.3
  text "MB1551D" at 59.387,58.312 h2
  text "USB-C" at 13.75,57.075 h1.27
  text "ARD" at 56.6,52.925 h1.27 r90
  text "K" at 77.175,52.25 h12
  text "OCTOSPI" at 36.75,52.175 h1.27
  text "FLASH" at 37.675,51.025 h1.27
  text "SYS" at 11.5,49.475 h1.2
  text "USB" at 7.95,49.45 h1.2
  text "3V3" at 0.425,49.275 h1.5
  text "0" at 4.75,49.275 h1.5
  text "BT_PWR" at 8.325,43.8 h1.4
  text "0" at 81.9,43.4 h1.3
  text "0" at 78.365,43.375 h1.3
  text "RESERVED" at 18.425,42.8 h1.5 r90
  text "SELECT" at 8.475,42.325 h1.4
  text "VPP" at 42.275,41.6 h1.27
  text "MIC2" at 60.587,41.575 h1.3
  text "RESERVED" at 54.2,40.075 h1.5 r90
  text "NC" at 76.825,37.075 h1.3
  text "NC" at 82.05,37.05 h1.3
  text "OPAMP1" at 56.25,36.975 h1
  text "STLK" at 96.575,36.475 h1.27
  text "VINM" at 55.575,36.225 h1
  text "BOOT" at 76.825,35.725 h1.3
  text "ESLK" at 80.83,35.741 h1.3
  text "COM" at 87.525,35.475 h1.27
  text "OPAMP2" at 56.225,34.425 h1
  text "VINM" at 55.55,33.675 h1
  text "MIPI10" at 62.15,23.1 h1.27
  text "TAG" at 59.4,22.175 h1.27
  text "STLK" at 91.15,21.625 h1
  text "OVC" at 91.35,20.8 h1
  text "0" at 54.9,14.7 h1.27
  text "1" at 49.575,14.675 h1.27
  text "BOOT0" at 50.55,13.95 h1.3
  text "OCTOSPI" at 37.9,13.35 h1.27
  text "SRAM" at 38.475,12.275 h1.27
  text "RESERVED" at 93.625,10.575 h1.5 r90
  text "2V8" at 3.7,9.65 h1.27
  text "PWR" at 55.95,6.7 h1.27
  text "5V_USB_CHGR" at 61.675,6.5 h1.27 r90
  text "5V UCPD" at 64.3,6.5 h1.27 r90
  text "5V VIN" at 66.775,6.5 h1.27 r90
  text "5V_USB_STLK" at 69.375,6.5 h1.27 r90
  text "USER" at 41.2,0.875 h1.27
  text "RST" at 50.85,0.675 h1.27
  text ".Layer_Name" at 12.297,-25.77 h3
  text ".GTO" at 53.992,-25.77 h3
Bottom Overlay:
  text "G" at 78.75,64.265 h10
  text "F" at 89.125,63.84 h12
  text "USB_BT" at 4.825,61.4 h1.27
  text "D0" at 20.775,57.05 h1.27 r270
  text "D2" at 25.875,57.05 h1.27 r270
  text "CS" at 46.875,57.05 h1.3 r270
  text "RX" at 19.775,57.025 h1.27 r270
  text "D4" at 30.925,57.025 h1.27 r270
  text "D6" at 35.025,57.025 h1.27 r270
  text "PWM" at 45.925,57.025 h1.3 r270
  text "D10" at 47.775,57.025 h1.3 r270
  text "MISO" at 51.875,57.025 h1.3 r270
  text "D12" at 52.9,57.025 h1.3 r270
  text "D8" at 42.65,57 h1.27 r270
  text "GND" at 57.8,56.975 h1.3 r270
  text "D14" at 61.925,56.975 h1.3 r270
  text "PWM" at 36.1,56.95 h1.27 r270
  text "SDA" at 60.95,56.95 h1.3 r270
  text "D9" at 45.175,52.775 h1.27 r270
  text "D7" at 38.475,52.75 h1.27 r270
  text "D11" at 50.25,52.3 h1.27 r270
  text "D13" at 55.3,52.15 h1.27 r270
  text "D15" at 65.45,52.025 h1.27 r270
  text "SCL" at 64.4,51.95 h1.27 r270
  text "SCK" at 54.3,51.825 h1.27 r270
  text "PWM" at 44.2,51.5 h1.27 r270
  text "PWM" at 48.35,51.475 h1.27 r270
  text "MOSI" at 49.3,51.35 h1.27 r270
  text "STLK_NRST" at 85.25,51.275 h1.27
  text "D1/TX" at 23.25,50.825 h1.27 r270
  text "VREFP" at 59.475,50.275 h1.3 r270
  text "D5/PWM" at 33.55,49.775 h1.27 r270
  text "D3/PWM" at 28.425,49.7 h1.27 r270
  text "UK / CA" at 98.4,44.675 h5
  text "BT_RST" at 8.925,41.025 h1.3
  text "I" at 8.85,32.75 h12
  text "SWD / BLE" at 72.225,29.187 h1.27
  text "SWD / MCU" at 77.2,29.187 h1.27
  text "SWD / OFF" at 72.775,26.6 h1.27
  text "SWD / OFF" at 77.1,26.6 h1.27
  text "E" at 21.625,23.65 h12
  text "H" at 10.45,23.195 h12
  text "SWD / ON" at 72.3,16.955 h1.27
  text "SWD / ON" at 77.175,16.95 h1.27
  text "IOREF" at 53.75,8.875 h1.27 r270
  text "A3" at 25.85,8.85 h1.27 r270
  text "3V3" at 48.6,8.85 h1.27 r270
  text "A5" at 20.8,8.8 h1.27 r270
  text "GND" at 43.525,8.8 h1.27 r270
  text "VIN" at 38.55,8.775 h1.27 r270
  text "A1" at 30.95,8.75 h1.27 r270
  text "A2" at 28.375,4.375 h1.27 r270
  text "A0" at 33.425,4.35 h1.27 r270
  text "5V" at 46.025,4.35 h1.27 r270
  text "A4" at 23.275,4.3 h1.27 r270
  text "NC" at 56.25,4.05 h1.27 r270
  text "GND" at 41.025,3.375 h1.27 r270
  text "NRST" at 51.225,2.875 h1.27 r270
  text ".GBO" at 42.789,-25.802 h3
  text ".Layer_Name" at 84.103,-25.802 h3
Top Paste:
  text ".Layer_Name" at 12.297,-25.77 h3
  text ".GTP" at 53.992,-25.77 h3
Bottom Paste:
  text ".GBP" at 42.789,-25.802 h3
  text ".Layer_Name" at 84.103,-25.802 h3
Top Solder:
  region: 0.756,31.125 2.506,31.125 2.506,38.75 0.756,38.75
  text ".Layer_Name" at 12.297,-25.77 h3
  text ".GTS" at 53.992,-25.77 h3
Bottom Solder:
  region: 0.756,31.125 2.506,31.125 2.506,38.75 0.756,38.75
  text ".GBS" at 42.789,-25.802 h3
  text ".Layer_Name" at 84.103,-25.802 h3
M1-Board Shape:
  the board outline again, w0.1
M2-Board Dimensions:
  text ".Layer_Name" at 12.297,-25.77 h3
  text ".GM2" at 53.992,-25.77 h3
M3-Top Dimensions:
  lines w0.254: 34.363,60.109 ccw(c34.373,60.109) 34.373,60.099 64.363,60.099
M14-Top Assembly:
  text ".Layer_Name" at 12.297,-25.77 h3
  text ".GM14" at 53.992,-25.77 h3
M15-Bottom Assembly:
  text ".GM15" at 42.789,-25.802 h3
  text ".Layer_Name" at 84.103,-25.802 h3
Drill Drawing:
  drawing of 549 lines, arcs and shapes, not listed
  text "PCB SPECIFICATIONS :" at 1.825,137.4 h3
  text "MINIMUM PARAMETERS" at 152.275,137.242 h3
  text "A.   MATERIAL :" at 1.825,133.4 h3
  text "FR-4" at 40.325,133.4 h3
  text "TG-170" at 56.825,133.4 h3
  text "X  TG-150" at 75.075,133.4 h3
  text "TG-140" at 91.075,133.4 h3
  text "DEFAULT" at 152.275,131.742 h3
  text "B.   MATERIAL FAMILY :" at 1.825,130.4 h3
  text "N/A" at 40.325,130.4 h3
  text "C.   SOLDERMASK COLOR :" at 1.825,127.4 h3
  text "GREEN" at 40.325,127.4 h3
  text "X  BLUE" at 56.825,127.4 h3
  text "RED" at 75.075,127.4 h3
  text "BLACK" at 91.075,127.4 h3
  text "TRACKS : 0.12mm           / GAPS : 0.12mm" at 152.275,125.992 h3
  text "D.   SILKSCREEN COLOR :" at 1.825,124.4 h3
  text "X  WHITE" at 40.325,124.4 h3
  text "YELLOW" at 56.825,124.4 h3
  text "BLACK" at 75.075,124.4 h3
  text "E.   SURFACE FINISH :" at 1.825,121.4 h3
  text "X  ENIG" at 40.325,121.4 h3
  text "IMMERSION SILVER" at 56.825,121.4 h3
  text "IMMERSION TIN" at 91.075,121.4 h3
  text "BGA (MCU) :" at 152.375,121.242 h3
  text "HASL" at 40.325,118.4 h3
  text "HASL (PB-FREE)" at 56.825,118.4 h3
  text "GOLDEN FINGER" at 91.075,118.4 h3
  text "TRACKS : 0.08mm           / GAPS : 0.085mm" at 152.375,115.492 h3
  text "F.   IMPEDANCE CONTROL :" at 1.825,115.4 h3
  text "NO" at 40.325,115.4 h3
  text "X  YES  (SEE IMPEDANCE TABLE FOR DETAIL INFORMATION)" at 56.825,115.4 h3
  text "G.   THROUGH VIA :" at 1.825,112.4 h3
  text "PLUG THE VIAS WHICH ARE COVERED WITH SOLDERMASK ONE OR TWO SIDE." at 40.325,112.4 h3
  text "BGA (STLink) :" at 152.525,111.617 h3
  text "PLUG MATERIAL :" at 40.325,109.4 h3
  text "X  SOLDERMASK" at 65.825,109.4 h3
  text "NON-CONDUCTIVE EPOXY." at 91.075,109.4 h3
  text "H.   STACK-UP :" at 1.825,106.4 h3
  text "SEE LAYER STACK-UP SEQUENCE FOR OVERALL THICKNESS." at 40.325,106.4 h3
  text "TRACKS : 0.09mm           / GAPS : 0.09mm" at 152.525,105.867 h3
  text "THE COMPONENTS WITH PLATED THROUGH HOLE (PTH) MAY BE WELDED (CABLED) IN \"PIN-IN-PASTE\" MODE (IF NECESSARY)" at 3.253,101.129 h3
  text "Layer" at 118.729,94.6 h2
  text "Name" at 127.103,94.6 h2
  text "Material" at 143.3,94.6 h2
  text "Thickness" at 157.854,94.6 h2
  text "Constant" at 169.809,94.6 h2
  text "Board Layer Stack" at 180.873,94.6 h2
  text "Top Overlay" at 127.103,90.6 h2
  text "Top Solder" at 127.103,86.6 h2
  text "Solder Resist" at 143.3,86.6 h2
  text "0,015mm" at 157.854,86.6 h2
  text "3,5" at 169.809,86.6 h2
  text "1" at 118.729,82.6 h2
  text "Top Layer" at 127.103,82.6 h2
  text "Copper" at 143.3,82.6 h2
  text "0,035mm" at 157.854,82.6 h2
  text "Dielectric 1" at 127.103,78.6 h2
  text "TU-768P" at 143.3,78.6 h2
  text "0,070mm" at 157.854,78.6 h2
  text "3,85" at 169.809,78.6 h2
  text "2" at 118.728,74.6 h2
  text "Signal Layer 1" at 127.103,74.6 h2
  text "Copper" at 143.3,74.6 h2
  text "0,035mm" at 157.854,74.6 h2
  text "Dielectric2" at 127.103,70.6 h2
  text "TU-768P" at 143.3,70.6 h2
  text "0,070mm" at 157.854,70.6 h2
  text "3,85" at 169.809,70.6 h2
  text "3" at 118.729,66.6 h2
  text "Signal Layer 2" at 127.103,66.6 h2
  text "Copper" at 143.3,66.6 h2
  text "0,035mm" at 157.854,66.6 h2
  text "Dielectric3" at 127.103,62.6 h2
  text "TU-768" at 143.3,62.6 h2
  text "1,000mm" at 157.854,62.6 h2
  text "4,5" at 169.809,62.6 h2
  text "4" at 118.729,58.6 h2
  text "Signal Layer 3" at 127.103,58.6 h2
  text "Copper" at 143.3,58.6 h2
  text "0,035mm" at 157.854,58.6 h2
  text "Dielectric4" at 127.103,54.6 h2
  text "TU-768P" at 143.3,54.6 h2
  text "0,070mm" at 157.854,54.6 h2
  text "3,85" at 169.809,54.6 h2
  text "5" at 118.729,50.6 h2
  text "Signal Layer 4" at 127.103,50.6 h2
  text "Copper" at 143.3,50.6 h2
  text "0,035mm" at 157.854,50.6 h2
  text "Dielectric5" at 127.103,46.6 h2
  text "TU-768P" at 143.3,46.6 h2
  text "0,070mm" at 157.854,46.6 h2
  text "3,85" at 169.809,46.6 h2
  text "6" at 118.729,42.6 h2
  text "Bottom Layer" at 127.103,42.6 h2
  text "Copper" at 143.3,42.6 h2
  text "0,035mm" at 157.854,42.6 h2
  text "Bottom Solder" at 127.103,38.6 h2
  text "Solder Resist" at 143.3,38.6 h2
  text "0,015mm" at 157.854,38.6 h2
  text "3,5" at 169.809,38.6 h2
  text "Bottom Overlay" at 127.103,34.6 h2
  text "Symbol" at 119.47,27.784 h2.4
  text "Count" at 128.869,27.784 h2.4
  text "Hole Size" at 139.5,27.784 h2.4
  text "Plated" at 158.771,27.784 h2.4
  text "Hole Type" at 167.022,27.784 h2.4
  text "Drill Layer Pair" at 179.034,27.784 h2.4
  text "Via/Pad" at 201.814,27.784 h2.4
  text "Pad Shape" at 211.657,27.784 h2.4
  text "1" at 128.869,23.64 h2
  text "1,300mm (51,18mil)" at 139.5,23.64 h2
  text "NPTH" at 158.771,23.64 h2
  text "Round" at 167.022,23.64 h2
  text "Top Layer - Bottom Layer" at 179.034,23.64 h2
  text "Pad" at 201.814,23.64 h2
  text "Rounded" at 211.657,23.64 h2
  text "2" at 128.869,19.497 h2
  text "0,500mm (19,69mil)" at 139.5,19.497 h2
  text "NPTH" at 158.771,19.497 h2
  text "Round" at 167.022,19.497 h2
  text "Top Layer - Bottom Layer" at 179.034,19.497 h2
  text "Pad" at 201.814,19.497 h2
  text "Rounded" at 211.657,19.497 h2
  text "2" at 128.869,15.354 h2
  text "0,600mm (23,62mil)" at 139.5,15.354 h2
  text "PTH" at 158.771,15.354 h2
  text "Slot" at 167.022,15.354 h2
  text "Top Layer - Bottom Layer" at 179.034,15.354 h2
  text "Pad" at 201.814,15.354 h2
  text "Rounded" at 211.657,15.354 h2
  text "2" at 128.869,11.211 h2
  text "0,970mm (38,19mil)" at 139.5,11.211 h2
  text "NPTH" at 158.771,11.211 h2
  text "Round" at 167.022,11.211 h2
  text "Top Layer - Bottom Layer" at 179.034,11.211 h2
  text "Pad" at 201.814,11.211 h2
  text "Rounded" at 211.657,11.211 h2
  text "2" at 128.869,7.068 h2
  text "1,190mm (46,85mil)" at 139.5,7.068 h2
  text "NPTH" at 158.771,7.068 h2
  text "Round" at 167.022,7.068 h2
  text "Top Layer - Bottom Layer" at 179.034,7.068 h2
  text "Pad" at 201.814,7.068 h2
  text "Rounded" at 211.657,7.068 h2
  text "2" at 128.869,2.925 h2
  text "3,200mm (125,98mil)" at 139.5,2.925 h2
  text "PTH" at 158.771,2.925 h2
  text "Round" at 167.022,2.925 h2
  text "Top Layer - Bottom Layer" at 179.034,2.925 h2
  text "Pad" at 201.814,2.925 h2
  text "Rounded" at 211.657,2.925 h2
  text "3" at 128.869,-1.218 h2
  text "3,500mm (137,79mil)" at 139.5,-1.218 h2
  text "PTH" at 158.771,-1.218 h2
  text "Round" at 167.022,-1.218 h2
  text "Top Layer - Bottom Layer" at 179.034,-1.218 h2
  text "Pad" at 201.814,-1.218 h2
  text "Rounded" at 211.657,-1.218 h2
  text "4" at 128.869,-5.361 h2
  text "0,450mm (17,72mil)" at 139.5,-5.361 h2
  text "PTH" at 158.771,-5.361 h2
  text "Slot" at 167.022,-5.361 h2
  text "Top Layer - Bottom Layer" at 179.034,-5.361 h2
  text "Pad" at 201.814,-5.361 h2
  text "Rounded" at 211.657,-5.361 h2
  text "4" at 128.869,-9.504 h2
  text "1,100mm (43,31mil)" at 139.5,-9.504 h2
  text "NPTH" at 158.771,-9.504 h2
  text "Round" at 167.022,-9.504 h2
  text "Top Layer - Bottom Layer" at 179.034,-9.504 h2
  text "Pad" at 201.814,-9.504 h2
  text "Rounded" at 211.657,-9.504 h2
  text "12" at 128.869,-13.647 h2
  text "1,100mm (43,31mil)" at 139.5,-13.647 h2
  text "PTH" at 158.771,-13.647 h2
  text "Round" at 167.022,-13.647 h2
  text "Top Layer - Bottom Layer" at 179.034,-13.647 h2
  text "Pad" at 201.814,-13.647 h2
  text "(Mixed)" at 211.657,-13.647 h2
  text "14" at 128.869,-17.79 h2
  text "0,400mm (15,75mil)" at 139.5,-17.79 h2
  text "PTH" at 158.771,-17.79 h2
  text "Round" at 167.022,-17.79 h2
  text "Top Layer - Bottom Layer" at 179.034,-17.79 h2
  text "Pad" at 201.814,-17.79 h2
  text "Rounded" at 211.657,-17.79 h2
  text "26" at 128.869,-21.934 h2
  text "1,000mm (39,37mil)" at 139.5,-21.934 h2
  text "PTH" at 158.771,-21.934 h2
  text "Round" at 167.022,-21.934 h2
  text "Top Layer - Bottom Layer" at 179.034,-21.934 h2
  text "Pad" at 201.814,-21.934 h2
  text "Rounded" at 211.657,-21.934 h2
  text ".Layer_Name" at 12.297,-25.77 h3
  text ".DRL" at 53.992,-25.77 h3
  text "42" at 128.869,-26.077 h2
  text "0,900mm (35,43mil)" at 139.5,-26.077 h2
  text "PTH" at 158.771,-26.077 h2
  text "Round" at 167.022,-26.077 h2
  text "Top Layer - Bottom Layer" at 179.034,-26.077 h2
  text "Pad" at 201.814,-26.077 h2
  text "(Mixed)" at 211.657,-26.077 h2
  text "178" at 128.869,-30.22 h2
  text "0,100mm (3,94mil)" at 139.5,-30.22 h2
  text "PTH" at 158.771,-30.22 h2
  text "Round" at 167.022,-30.22 h2
  text "(Mixed)" at 179.034,-30.22 h2
  text "Via" at 201.814,-30.22 h2
  text "Rounded" at 211.657,-30.22 h2
  text "922" at 128.869,-34.363 h2
  text "0,200mm (7,87mil)" at 139.5,-34.363 h2
  text "PTH" at 158.771,-34.363 h2
  text "Round" at 167.022,-34.363 h2
  text "Top Layer - Bottom Layer" at 179.034,-34.363 h2
  text "Via" at 201.814,-34.363 h2
  text "Rounded" at 211.657,-34.363 h2
  text "1216 Total" at 128.869,-38.506 h2
  text "Slot definitions :" at 119.47,-41.406 h2
  text "Routed Path Length" at 133.123,-41.406 h2
  text "= Calculated from tool start centre position to tool end centre position." at 150.036,-41.406 h2
  text "Hole Length" at 133.123,-43.063 h2
  text "= Routed Path Length + Tool Size = Slot length as defined in the PCB layout" at 143.757,-43.063 h2
M20-Top Title Box:
  circle w0.254: c90.301,-32.49 r1.3
  region: 89.826,-25.254 74.299,-25.254 73.605,-27.029 72.394,-28.254 70.997,-26.394 70.997,-24.743 72.14,-23.346 73.576,-22.968 89.826,-22.968
  region: 75.823,-33.583 65.067,-33.583 66.061,-31.091 73.918,-31.091 74.367,-30.331 76.576,-32.88
  lines w0.254: 66.061,-31.091 74.852,-31.091 71.786,-27.553 cw(c73.59,-25.609) 73.83,-22.968 90.594,-22.968 89.832,-25.254 ; 69.374,-22.721 cw(c71.8,-23.691) 72.037,-21.089 ; 69.413,-22.688 65.067,-33.583 84.39,-33.583 ccw(c84.638,-30.849) 87.188,-31.869 ; 71.153,-26.623 76.576,-32.88 ; 71.407,-26.623 76.712,-32.744 ; 71.407,-26.369 76.712,-32.49 ; 71.505,-25.254 84.498,-25.254 ; 71.534,-26.242 76.839,-32.363 ; 71.661,-26.115 76.966,-32.236 ; 71.788,-25.988 77.093,-32.109 ; 71.915,-25.861 77.22,-31.982 ; 71.97,-23.909 77.275,-30.03 ; 72.038,-21.089 91.488,-21.089 87.189,-31.866 ; 72.042,-25.734 77.293,-31.792 ; 72.042,-25.48 77.347,-31.601 ; 72.042,-25.226 77.347,-31.347 ; 72.042,-24.337 77.347,-30.458 ; 72.169,-25.099 77.474,-31.22 ; 72.169,-24.718 77.474,-30.839 ; 73.541,-31.104 ccw(c73.646,-30.569) 73.944,-30.112 ; 74.627,-25.241 ccw(c74.601,-25.808) 74.271,-26.27 76.636,-28.999 cw(c74.832,-30.942) 75.565,-33.491 ; 80.909,-33.379 83.798,-25 ; 81.131,-33.329 84,-25.009 ; 81.258,-33.329 84.127,-25.009 ; 81.512,-33.329 84.381,-25.009 ; 81.766,-33.329 84.635,-25.009 ; 82.02,-33.329 84.889,-25.009 ; 82.274,-33.329 85.143,-25.009 ; 82.528,-33.329 85.397,-25.009 ; 82.782,-33.329 85.651,-25.009 ; 83.036,-33.329 85.905,-25.009 ; 83.245,-33.379 86.134,-25 ; 86.134,-25.254 89.826,-25.254 ; 89.158,-25.251 89.92,-22.965 ; 89.324,-25.254 90.086,-22.968 ; 89.578,-25.254 90.34,-22.968
  lines w0.3: 3.297,-32.47 63.297,-32.47 ; 3.297,-27.47 63.297,-27.47 ; 3.297,-22.47 63.297,-22.47 ; 43.297,-37.47 43.297,-22.47 ; 63.297,-37.47 63.297,-17.47 ; 80.909,-33.379 83.245,-33.379 ; 3.297,-37.47 3.297,-17.47 93.297,-17.47 93.297,-37.47 3.297,-37.47
  text "Project: '.Board_Name'" at 4.297,-20.686 h3
  text "Layer:" at 4.297,-25.77 h3
  text "Gerber:" at 44.286,-25.77 h3
  text "Variant: '.VariantName'" at 4.297,-30.77 h3
  text "Ref: MB1551" at 44.413,-30.77 h3
  text "R" at 89.793,-33.252 h1.52
  text "Date: '.Board_Document_Date'" at 4.297,-35.77 h3
  text "Rev: '.Board_PCB_Revision'" at 44.356,-35.77 h3
M21-Bottom Title Box:
  circle w0.254: c6.48,-32.49 r1.3
  region: 20.958,-33.583 31.714,-33.583 30.72,-31.091 22.863,-31.091 22.414,-30.331 20.205,-32.88
  region: 6.954,-25.254 22.482,-25.254 23.176,-27.029 24.387,-28.254 25.784,-26.394 25.784,-24.743 24.641,-23.346 23.205,-22.968 6.954,-22.968
  lines w0.254: 6.441,-22.968 7.203,-25.254 ; 6.695,-22.968 7.457,-25.254 ; 6.861,-22.965 7.623,-25.251 ; 6.949,-25.254 6.187,-22.968 22.951,-22.968 cw(c23.191,-25.609) 24.995,-27.553 21.929,-31.091 30.72,-31.091 ; 6.954,-25.254 10.647,-25.254 ; 9.593,-31.869 ccw(c12.143,-30.849) 12.391,-33.583 31.714,-33.583 27.368,-22.688 ; 9.592,-31.866 5.293,-21.089 24.743,-21.089 ; 10.647,-25 13.536,-33.379 ; 10.876,-25.009 13.745,-33.329 ; 11.13,-25.009 13.999,-33.329 ; 11.384,-25.009 14.253,-33.329 ; 11.638,-25.009 14.507,-33.329 ; 11.892,-25.009 14.761,-33.329 ; 12.146,-25.009 15.015,-33.329 ; 12.283,-25.254 25.276,-25.254 ; 12.4,-25.009 15.269,-33.329 ; 12.654,-25.009 15.523,-33.329 ; 12.781,-25.009 15.65,-33.329 ; 12.983,-25 15.872,-33.379 ; 19.307,-31.22 24.612,-25.099 ; 19.307,-30.839 24.612,-24.718 ; 19.434,-31.601 24.739,-25.48 ; 19.434,-31.347 24.739,-25.226 ; 19.434,-30.458 24.739,-24.337 ; 19.488,-31.792 24.739,-25.734 ; 19.506,-30.03 24.811,-23.909 ; 19.561,-31.982 24.866,-25.861 ; 19.688,-32.109 24.993,-25.988 ; 19.815,-32.236 25.12,-26.115 ; 19.942,-32.363 25.247,-26.242 ; 20.069,-32.744 25.374,-26.623 ; 20.069,-32.49 25.374,-26.369 ; 20.205,-32.88 25.628,-26.623 ; 21.216,-33.491 cw(c21.949,-30.942) 20.145,-28.999 22.51,-26.27 ccw(c22.179,-25.808) 22.153,-25.241 ; 22.837,-30.112 ccw(c23.135,-30.569) 23.24,-31.104 ; 24.744,-21.089 cw(c24.981,-23.691) 27.407,-22.721
  lines w0.3: 13.536,-33.379 15.872,-33.379 ; 33.297,-37.47 33.297,-17.47 ; 33.297,-32.47 93.297,-32.47 ; 33.297,-27.47 93.297,-27.47 ; 33.297,-22.47 93.297,-22.47 ; 53.297,-37.47 53.297,-22.47 ; 3.297,-37.47 93.297,-37.47 93.297,-17.47 3.297,-17.47 3.297,-37.47
  text "Project: '.Board_Name'" at 92.103,-20.686 h3
  text "Gerber:" at 52.114,-25.77 h3
  text "Layer:" at 92.103,-25.77 h3
  text "Ref: MB1551" at 52.114,-30.77 h3
  text "Variant: '.VariantName'" at 92.103,-30.77 h3
  text "R" at 6.988,-33.252 h1.52
  text "Rev: '.Board_PCB_Revision'" at 52.171,-35.77 h3
  text "Date: '.Board_Document_Date'" at 92.103,-35.77 h3

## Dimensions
3.072,70 to 3.061,0 on M2-Board Dimensions
0,66.928 to 100,66.927 on M2-Board Dimensions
